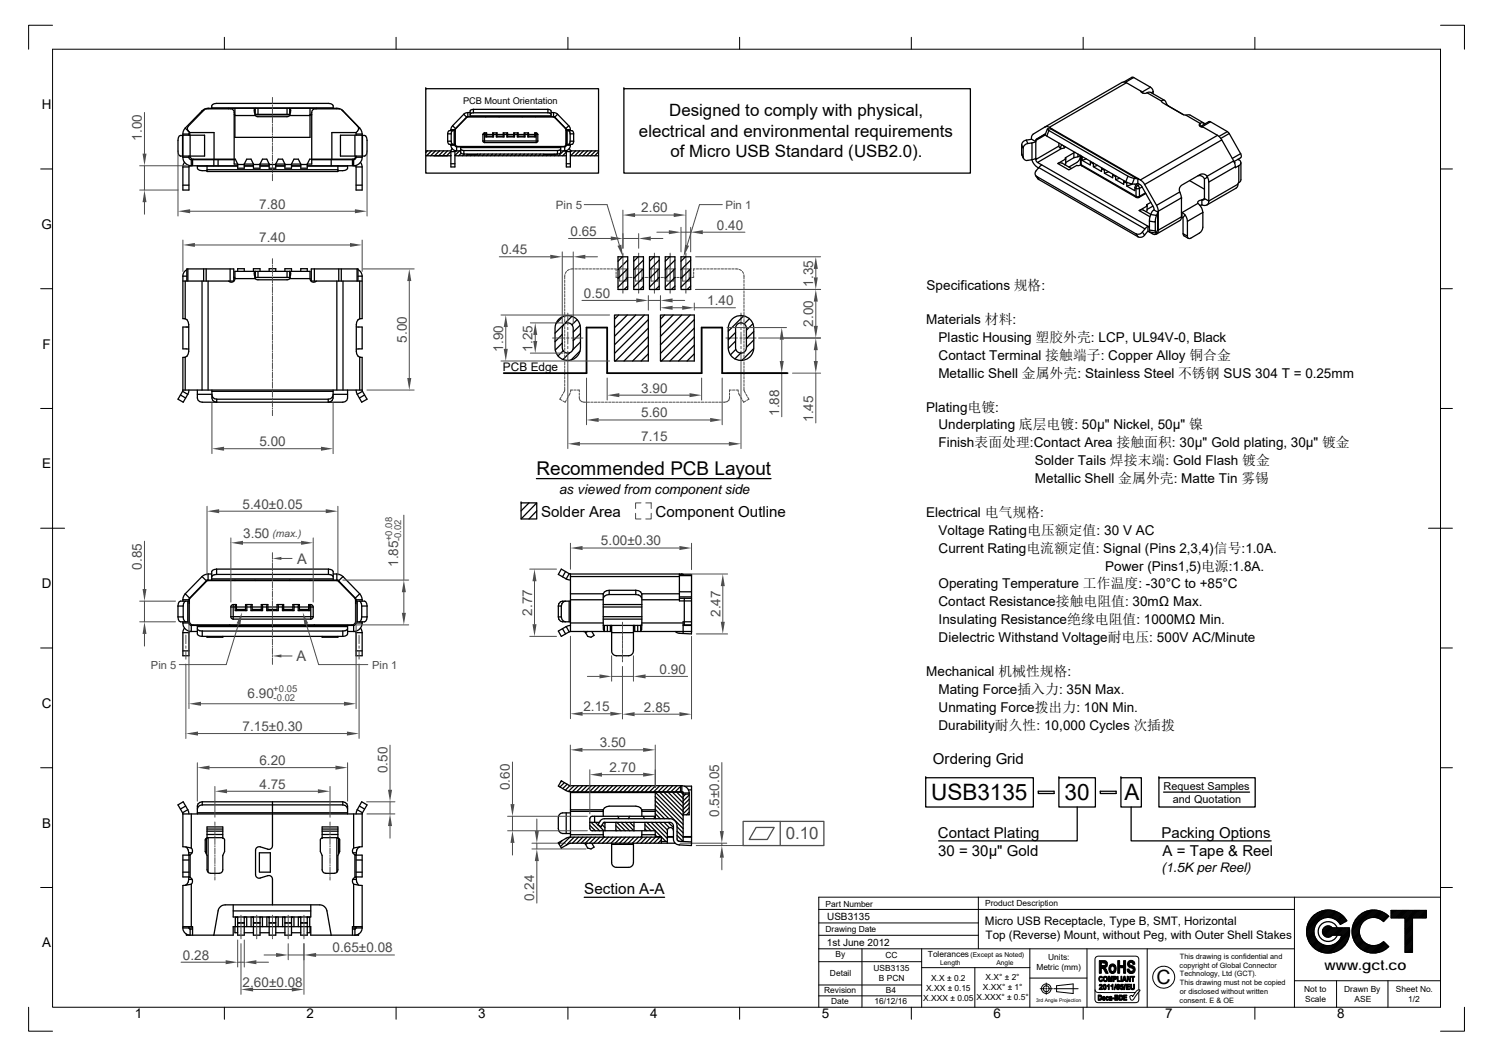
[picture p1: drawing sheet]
<svg xmlns="http://www.w3.org/2000/svg" width="297mm" height="210mm" viewBox="0 0 297 210" stroke-linecap="round" stroke-linejoin="round" font-family="sans-serif">
<defs><g id="words">
<g font-size="4.5">
<text x="185.3" y="159.1">USB3135</text>
<text x="211.8" y="159.1">30</text>
<text x="223.7" y="159.2">A</text>
</g>
<text font-size="3.9" x="230.1" y="195.8">C</text>
<text font-size="3.8" x="106.7" y="94.4">Recommended PCB Layout</text>
<g font-size="3.4">
<text x="133.1" y="23.1">Designed to comply with physical,</text>
<text x="127.1" y="27.2">electrical and environmental requirements</text>
<text x="133.4" y="31.2">of Micro USB Standard (USB2.0).</text>
</g>
<text font-size="3.4" fill="#4b4b4b" x="156.3" y="166.9">0.10</text>
<g font-size="3">
<text x="107.7" y="102.7">Solder Area</text>
<text x="130.4" y="102.8">Component Outline</text>
<text x="185.6" y="151.9">Ordering Grid</text>
<text x="186.6" y="166.6">Contact Plating</text>
<text x="231.1" y="166.5">Packing Options</text>
<text x="186.6" y="170.2">30 = 30µ&quot; Gold</text>
<text x="231.3" y="170.1">A = Tape &amp; Reel</text>
<text x="116.2" y="177.8">Section A-A</text>
</g>
<g font-size="2.9" fill="#4b4b4b">
<text x="59.1" y="112.1">A</text>
<text x="59" y="131.3">A</text>
</g>
<text font-size="2.8" x="263.5" y="192.9">www.gct.co</text>
<g font-size="2.7">
<text x="8.3" y="21.7">H</text>
<text x="8.2" y="45.5">G</text>
<text x="184.3" y="57.7">Specifications 规格:</text>
<text x="184.3" y="64.4">Materials 材料:</text>
<text x="8.5" y="69.3">F</text>
<text x="186.7" y="71.6">Contact Terminal 接触端子: Copper Alloy 铜合金</text>
<text x="186.7" y="68">Plastic Housing 塑胶外壳: LCP, UL94V-0, Black</text>
<text x="186.7" y="75.1">Metallic Shell 金属外壳: Stainless Steel 不锈钢 SUS 304 T = 0.25mm</text>
<text x="184.3" y="81.9">Plating电镀:</text>
<text x="186.7" y="88.9">Finish表面处理:Contact Area 接触面积: 30µ&quot; Gold plating, 30µ&quot; 镀金</text>
<text x="186.7" y="85.4">Underplating 底层电镀: 50µ&quot; Nickel, 50µ&quot; 镍</text>
<text x="8.4" y="93.1">E</text>
<text x="205.9" y="92.5">Solder Tails 焊接末端: Gold Flash 镀金</text>
<text x="111.2" y="98.1">as viewed from component side</text>
<text x="205.9" y="96.1">Metallic Shell 金属外壳: Matte Tin 雾锡</text>
<text x="184.2" y="102.8">Electrical 电气规格:</text>
<text x="186.7" y="106.4">Voltage Rating电压额定值: 30 V AC</text>
<text x="186.7" y="109.9">Current Rating电流额定值: Signal (Pins 2,3,4)信号:1.0A.</text>
<text x="219.9" y="113.5">Power (Pins1,5)电源:1.8A.</text>
<text x="8.3" y="117">D</text>
<text x="186.7" y="117">Operating Temperature 工作温度: -30°C to +85°C</text>
<text x="186.7" y="120.6">Contact Resistance接触电阻值: 30mΩ Max.</text>
<text x="186.7" y="124.1">Insulating Resistance绝缘电阻值: 1000MΩ Min.</text>
<text x="186.7" y="127.7">Dielectric Withstand Voltage耐电压: 500V AC/Minute</text>
<text x="184.3" y="134.4">Mechanical 机械性规格:</text>
<text x="186.7" y="138">Mating Force插入力: 35N Max.</text>
<text x="8.3" y="140.8">C</text>
<text x="186.7" y="141.5">Unmating Force拨出力: 10N Min.</text>
<text x="186.7" y="145.1">Durability耐久性: 10,000 Cycles 次插拨</text>
<text x="8.4" y="164.6">B</text>
<text x="8.4" y="188.4">A</text>
<text x="26.8" y="202.4">1</text>
<text x="61" y="202.4">2</text>
<text x="95.1" y="202.4">3</text>
<text x="129.3" y="202.4">4</text>
<text x="163.5" y="202.4">5</text>
<text x="197.7" y="202.4">6</text>
<text x="231.8" y="202.4">7</text>
<text x="266" y="202.4">8</text>
</g>
<g font-size="2.7" fill="#4b4b4b">
<text x="28.2" y="27.9" transform="rotate(-90 28.2 27.9)">1.00</text>
<text x="51.6" y="41.5">7.80</text>
<text x="113.5" y="46.9">0.65</text>
<text x="127.6" y="42.2">2.60</text>
<text x="142.6" y="45.6">0.40</text>
<text x="51.6" y="48.2">7.40</text>
<text x="99.7" y="50.5">0.45</text>
<text x="116.2" y="59.2">0.50</text>
<text x="161.8" y="57" transform="rotate(-90 161.8 57)">1.35</text>
<text x="140.7" y="60.7">1.40</text>
<text x="161.8" y="65" transform="rotate(-90 161.8 65)">2.00</text>
<text x="80.9" y="68.1" transform="rotate(-90 80.9 68.1)">5.00</text>
<text x="100.1" y="69.9" transform="rotate(-90 100.1 69.9)">1.90</text>
<text x="106" y="69.9" transform="rotate(-90 106 69.9)">1.25</text>
<text x="127.6" y="83">5.60</text>
<text x="127.6" y="78.1">3.90</text>
<text x="155" y="82.7" transform="rotate(-90 155 82.7)">1.88</text>
<text x="161.8" y="83.9" transform="rotate(-90 161.8 83.9)">1.45</text>
<text x="51.6" y="88.7">5.00</text>
<text x="127.6" y="87.7">7.15</text>
<text x="48.2" y="101.1">5.40±0.05</text>
<text x="48.4" y="107">3.50</text>
<text x="28.2" y="113.2" transform="rotate(-90 28.2 113.2)">0.85</text>
<text x="79.2" y="112.7" transform="rotate(-90 79.2 112.7)">1.85</text>
<text x="119.6" y="108.5">5.00±0.30</text>
<text x="105.9" y="122.5" transform="rotate(-90 105.9 122.5)">2.77</text>
<text x="143.3" y="122.7" transform="rotate(-90 143.3 122.7)">2.47</text>
<text x="131.2" y="134">0.90</text>
<text x="49.3" y="138.8">6.90</text>
<text x="116.1" y="141.4">2.15</text>
<text x="128.1" y="141.5">2.85</text>
<text x="48.2" y="145.4">7.15±0.30</text>
<text x="119.3" y="148.6">3.50</text>
<text x="51.6" y="152.1">6.20</text>
<text x="77.1" y="153.8" transform="rotate(-90 77.1 153.8)">0.50</text>
<text x="121.3" y="153.5">2.70</text>
<text x="51.6" y="156.8">4.75</text>
<text x="101.4" y="157.1" transform="rotate(-90 101.4 157.1)">0.60</text>
<text x="143.1" y="162.5" transform="rotate(-90 143.1 162.5)">0.5±0.05</text>
<text x="106.3" y="179.2" transform="rotate(-90 106.3 179.2)">0.24</text>
<text x="36.4" y="190.8">0.28</text>
<text x="66.1" y="189.4">0.65±0.08</text>
<text x="48.3" y="196.2">2.60±0.08</text>
</g>
<text font-size="2.6" x="231.1" y="173.5">(1.5K per Reel)</text>
<g font-size="2.3" fill="#4b4b4b">
<text x="110.6" y="41.5">Pin 5</text>
<text x="144.3" y="41.5">Pin 1</text>
</g>
<g font-size="2.3">
<text x="100" y="73.7">PCB Edge</text>
<text x="195.9" y="183.8">Micro USB Receptacle, Type B, SMT, Horizontal</text>
<text x="196.1" y="186.7">Top (Reverse) Mount, without Peg, with Outer Shell Stakes</text>
</g>
<g font-size="2.2" fill="#4b4b4b">
<text x="30" y="133">Pin 5</text>
<text x="74" y="133">Pin 1</text>
</g>
<g font-size="2.2">
<text x="231.5" y="157.1">Request Samples</text>
<text x="233.3" y="159.7">and Quotation</text>
</g>
<text font-size="2" fill="#4b4b4b" x="54.2" y="106.8">(max.)</text>
<g font-size="2">
<text x="164.5" y="182.9">USB3135</text>
<text x="164.5" y="188.1">1st June 2012</text>
</g>
<g font-size="1.9" fill="#4b4b4b">
<text x="78" y="107.6" transform="rotate(-90 78 107.6)">+0.08</text>
<text x="79.8" y="107.6" transform="rotate(-90 79.8 107.6)">-0.02</text>
<text x="54.4" y="137.6">+0.05</text>
<text x="54.4" y="139.4">-0.02</text>
</g>
<text font-size="1.8" x="92.1" y="20.7">PCB Mount Orientation</text>
<g font-size="1.7">
<text x="164.3" y="180.3">Part Number</text>
<text x="164.3" y="185.3">Drawing Date</text>
<text x="196" y="180.2">Product Description</text>
<text x="166.2" y="190.4">By</text>
<text x="176.2" y="190.5">CC</text>
<text x="184.6" y="190.4">Tolerances</text>
<text x="208.5" y="191">Units:</text>
<text x="164" y="197.5">Revision</text>
<text x="165.1" y="194.1">Detail</text>
<text x="173.8" y="193.2">USB3135</text>
<text x="174.9" y="195.1">B PCN</text>
<text x="176.3" y="197.5">B4</text>
<text x="184.2" y="197">X.XX ± 0.15</text>
<text x="185.3" y="195">X.X ± 0.2</text>
<text x="195.5" y="196.9">X.XX° ± 1°</text>
<text x="196.1" y="195">X.X° ± 2°</text>
<text x="206.2" y="192.9">Metric (mm)</text>
<text x="259.5" y="197.2">Not to</text>
<text x="267.4" y="197.2">Drawn By</text>
<text x="277.7" y="197.3">Sheet No.</text>
<text x="165.4" y="199.7">Date</text>
<text x="174" y="199.7">16/12/16</text>
<text x="183.7" y="199">X.XXX ± 0.05</text>
<text x="194.3" y="198.9">X.XXX° ± 0.5°</text>
<text x="259.7" y="199.2">Scale</text>
<text x="269.5" y="199.2">ASE</text>
<text x="280.1" y="199.2">1/2</text>
</g>
<g font-size="1.5">
<text x="234.7" y="190.6">This drawing is confidential and</text>
<text x="234.7" y="192.4">copyright of Global Connector</text>
<text x="234.7" y="197.6">or disclosed without written</text>
<text x="234.7" y="194.1">Technology, Ltd (GCT).</text>
<text x="234.7" y="195.9">This drawing must not be copied</text>
<text x="234.7" y="199.4">consent. E &amp; OE</text>
</g>
<g font-size="1.3">
<text x="187" y="191.9">Length</text>
<text x="193.1" y="190.4">(Except as Noted)</text>
<text x="198.2" y="191.9">Angle</text>
</g>
<text font-size="1" x="206.1" y="199.2">3rd Angle Projection</text>
</g></defs>
<path d="M184.2 154.7h21.4v5.8h-21.4zM184.2 154.7h.1M206.6 157.3h3.1v.5h-3.1zM210.7 154.7h7.2v5.8h-7.2zM210.7 154.7h.1M218.9 157.3h3.2v.5h-3.2zM223 154.7h4.1v5.8h-4.1zM223 154.7h.1M214.3 160.5v6.7h-27.5M225 160.5v6.7h27.9" fill="none" stroke="#000" stroke-width=".25"/>
<path d="M105.8 168.8h10.8M105.8 167.7h6.7M106.8 162.8v2.5M106.8 167.7v1.1M106.8 171.2v8.4" fill="none" stroke="#4b4b4b" stroke-width=".2"/>
<g fill="#4b4b4b">
<path d="M106.4 165.3h.8l-.4 2.4z"/>
<path d="M106.8 168.8l.4 2.4h-.8z"/>
</g>
<path d="M147.8 163.3h16.1v4.8h-16.1zM150.4 164.5h3.6l-1.3 2.4h-3.6zM155.2 163.3v4.8" fill="none" stroke="#4b4b4b" stroke-width=".25"/>
<path d="M143.6 151.6v13.7M135.3 167.7h9.3M138.5 168.1h6.1M143.6 167.7v.4M143.6 170.5v2.5" fill="none" stroke="#4b4b4b" stroke-width=".2"/>
<g fill="#4b4b4b">
<path d="M143.6 168.1l.4 2.4h-.8z"/>
<path d="M143.2 165.3h.8l-.4 2.4z"/>
</g>
<g fill="none" stroke="#000" stroke-width=".25">
<path d="M111.8 155.3l-.3 .2M112.3 155.6l-.9 .9M112.8 155.9l-.8 .9M113.4 156.2l-.9 .9M113.5 157.4h22.2M113.5 157.6h16.9M113.5 157.4v9M114.2 156.2l-1.1 1.2M115.1 156.2l-1.2 1.2M115.9 156.2l-1.2 1.2M116.8 156.2l-1.2 1.2M117.6 156.2l-1.2 1.2"/>
<path d="M118.5 156.2l-1.2 1.2M119.3 156.2l-1.2 1.2M120.2 156.2l-1.2 1.2M121.1 156.2l-1.3 1.2M121.9 156.2l-1.2 1.2M122.7 156.2l-1.2 1.2M123.6 156.2l-1.2 1.2M124.5 156.2l-1.2 1.2M125.3 156.2l-1.2 1.2M126.2 156.2l-1.3 1.2M127 156.2l-1.2 1.2M127.9 156.2l-1.2 1.2"/>
<path d="M128.7 156.2l-1.2 1.2M129.6 156.2l-1.2 1.2M130.4 156.2l-1.2 1.2M131.3 156.2l-1.2 1.2M132.1 156.2l-1.2 1.2M133 156.2l-1.2 1.2M133.8 156.2l-1.2 1.2M134.7 156.2l-1.2 1.2M135.4 157.2l-.2 .2M135.4 156.2v1.2M135.4 156.3l-1.1 1.1M135.7 156.2h-22.2l-1.8-.9-.6 1 1.5 .9 .9 .2"/>
<path d="M135.7 156.2v1.2M135.7 157.4l.1 .1M135.7 156.2a1.46 1.46 0 0 1 1.4 1.5M135.9 157.7h1.2M135.9 157.9h1.2M136.2 156.3h1.4v11.8l-2.5-.1M136.4 157.9l-.5 .5M136.9 157.1h.7M137.1 158.1l-1.2 1.2M137.1 158.9l-1.2 1.2M137.1 159.8l-1.2 1.2M137.1 157.7v4.3h-1.2"/>
<path d="M111.8 167.1l-.6 .7M112.6 161.6v4.1M113.4 166.5l-1.9 1.8M113.5 161h6.5M113.5 161.3h6.5M113.5 161.6h-1.6l-.4 .2-.3 .3-.1 .5 .1 2.7 .3 .3 .4 .1h1.6M113.5 166h6.5M114.2 166.5l-1.6 1.6M115.1 166.5l-1.2 1.2M116 166.5l-1.3 1.2M116.1 167.7l.4 .2M116.8 166.5l-1.2 1.2"/>
<path d="M116.9 167.7l-.4 .2M117.6 166.5l-1.2 1.2M117.8 167.7l.4 .8-.6 .3-.7-.2-.4-.7M118.3 162.3v1.2M118.5 166.5l-1.2 1.2M119.3 163.5h-1.9M119.4 166.5l-1.2 1.2M120 161l.2-.3 1-.4h5.3l1 .4 .2 .3M120 161v1.3M120 165.2v.8M120 166v.3l.2 .2M120.2 166.5l-1.2 1.2"/>
<path d="M121.1 166.5l-1.3 1.2M121.7 167.7v3.8l.1 .5 .6 .5h2.7l.4-.2 .5-.5v-4.1M121.7 167.9h4.3M121.9 166.5l-1.2 1.2M122.8 166.5l-1.2 1.2M123.6 166.5l-1.2 1.2M124.5 166.5l-1.2 1.2M125.3 166.5l-1.2 1.2M126.2 166.5l-1.2 1.2M127 166.5l-1.2 1.2M127.7 161h2.7M127.7 161v.2"/>
<path d="M127.7 161.3h2.7M127.7 166v.3l-.2 .2M127.7 161v1.3M127.7 165.2v.8M127.7 166h2.7M127.9 166.5l-1.2 1.2M128.7 166.5l-1.2 1.2M129.6 166.5l-1.2 1.2M130.4 162.8v-5.3h5.5v9.8M130.4 162.3h-12.6l-.3 .2-.2 .3v1.9l.2 .4 .3 .1h12.6v1.2h1.2v1.3M130.4 166.5l-1.2 1.2M131.3 166.5l-1.2 1.2"/>
<path d="M131.6 167l-.7 .7M131.6 166.5h-18.1l-.9 .2-1.5 .9 .6 1 1.8-.9h20.8M132.8 167.3v.4M132.8 166.5h1.2M132.8 166.4h1.2M134 165.1a.6 .6 0 0 0-.6-.5 .6 .6 0 0 0-.6 .5v2.2h-1.2M135.9 166.4h1.7M135.9 166.5h1.7M137.1 161.5l-.5 .5M137.1 160.6l-1.2 1.2M137.6 167.4l-2.5-.1-.3-.2-.1-.3v-2.6a1.44 1.44 0 0 0-1.5-1.4h-13.2a1.61 1.61 0 0 0-1 1.2l.6 .4 .4-.8 .2-.1h13.3l.3 .3 .2 .4v2.6a1.16 1.16 0 0 0 1.2 1.2"/>
</g>
<path d="M102 151.5v8.4M101 165.2h15.9M101 162.3h15.9M102 162.3v2.9M102 167.6v2.4" fill="none" stroke="#4b4b4b" stroke-width=".2"/>
<g fill="#4b4b4b">
<path d="M102 165.2l.4 2.4h-.8z"/>
<path d="M101.6 159.9h.8l-.4 2.4z"/>
</g>
<path d="M117.3 153.1v8.7M119.8 154h8.2M130.4 153.1v3.5" fill="none" stroke="#4b4b4b" stroke-width=".2"/>
<g fill="#4b4b4b">
<path d="M117.3 154l2.5-.4v.8z"/>
<path d="M128 153.6l2.4 .4-2.4 .4z"/>
</g>
<path d="M113.5 148.2v8.3M115.9 149.1h12.1M130.4 148.2v8.4" fill="none" stroke="#4b4b4b" stroke-width=".2"/>
<g fill="#4b4b4b">
<path d="M128 148.7l2.4 .4-2.4 .4z"/>
<path d="M113.5 149.1l2.4-.4v.8z"/>
</g>
<g fill="none" stroke="#000" stroke-width=".25">
<path d="M130.4 159.2l5.5 5.6M130.4 158.4l5.5 5.5M130.4 157.5l5.5 5.6M131.2 157.5l4.7 4.7M132.1 157.5l3.8 3.9M132.9 157.5l3 3M133.8 157.5l2.1 2.2M134.6 157.5l1.3 1.3M135.5 157.5l.4 .5M117.3 164.1l1.1 1.1M117.6 163.5l1.7 1.7M118.4 163.5l1.7 1.7"/>
<path d="M119.8 164l.6 .6M120.2 163.5l.2 .2M120.4 163.5v1.7M122.5 163.5v1.7M122.5 164.2l1 1M122.5 165l.2 .2M122.7 163.5l1.7 1.7M122.9 162.3l.3 .5M123.6 163.5l1.7 1.7M124.4 163.5l1.7 1.7M125.3 163.5l.8 .9M125.3 162.3l-.3 .5"/>
<path d="M126.1 163.5v1.7M128 162.3l.2 .5M128.3 164l1.2 1.2M128.3 164.9l.4 .3M128.3 163.5v1.7M128.7 163.5l2.8 2.9M129.5 163.5l3.3 3.3M130.4 162.6l.1 .2M130.4 160.1l2.7 2.7M130.4 166l.3 .4M130.4 160.9l1.8 1.9M130.4 161.8l1 1"/>
<path d="M130.4 162.3l-.3 .5M130.4 163.5l2.4 2.4M131.2 163.5l1.6 1.5M131.6 166.4l.9 .9M131.6 167.2v.1M132.1 163.5l1.1 1.1M132.9 163.5l1.1 1M134.7 166.1l1.2 1.2M134.7 165.3l1.2 1.2M134.7 164.4l1.2 1.2M134.7 167l.3 .2"/>
</g>
<path d="M138.4 57.6h24.9M138.4 51.1h24.9M162.3 53.5v1.7" fill="none" stroke="#4b4b4b" stroke-width=".2"/>
<g fill="#4b4b4b">
<path d="M161.9 55.2h.8l-.4 2.4z"/>
<path d="M162.3 51.1l.4 2.4h-.8z"/>
</g>
<g fill="none" stroke="#4b4b4b" stroke-width=".2">
<path d="M54.2 51.4v1.1M54.2 52.7v.3M54.2 53.2v1.2M54.2 54.6v.2M54.2 55.1v1.2M54.2 56.5v.3M54.2 57v1.2M54.2 58.4v.2M54.2 58.9v1.2M112.4 55.7v.5M112.4 56.4v.5M112.4 57.1v.5"/>
<path d="M112.4 57.9v.4M112.4 58.6v.4M112.4 59.3v.4M112.4 60v.5M112.4 54.6v.9M112.7 54l-.2 .4M113.3 53.6l-.4 .2M114.2 53.5h-.7M114.4 53.5h.5M115.1 53.5h.5M115.8 53.5h.5M116.5 53.5h.5"/>
<path d="M117.2 53.5h.5M118 53.5h.4M118.7 53.5h.4M119.4 53.5h.4M120.1 53.5h.4M120.8 53.5h.5M121.5 53.5h.5M122.2 53.5h.4v.3M122.6 54.1v.5M122.6 54.8v.4h.7M123.3 53.5h1.3v2.4h-1.3zM124.6 55.2h.4"/>
<path d="M125.3 55.2h.4M126 55.2h.4M126.4 53.5h1.3v2.4h-1.3zM127.7 55.2h.4M128.4 55.2h.5M129.1 55.2h.4M129.5 53.5h1.4v2.4h-1.4zM130.9 55.2h.4M131.5 55.2h.5M132.2 55.2h.5M132.7 53.5h1.3v2.4h-1.3zM134 55.2h.4"/>
<path d="M134.7 55.2h.4M135.4 55.2h.4M135.8 53.5h1.3v2.4h-1.3zM137.1 55.2h.3M138 54.1v.5M138 54.8v.4h-.3M138.3 53.5h-.3v.3M138.5 53.5h.5M139.2 53.5h.5M139.9 53.5h.5M140.6 53.5h.5M141.4 53.5h.4"/>
<path d="M142 53.5h.5M142.8 53.5h.4M143.5 53.5h.5M144.2 53.5h.5M144.9 53.5h.5M145.6 53.5h.5M146.3 53.5h.6M147.1 53.6l.4 .2M147.7 54l.2 .4M148 54.6v.9M148 55.7v.5M148 56.4v.5"/>
<path d="M148 57.1v.5M148 57.9v.4M148 58.6v.4M148 59.3v.4M148 60v.5M54.2 60.3v.2M54.2 60.8v1.2M54.2 62.2v.2M54.2 62.7v1.1M54.2 64.1v.2M54.2 64.6v1.1M54.2 66v.2"/>
<path d="M54.2 66.4v1.2M54.2 67.9v.2M54.2 68.3v1.2M54.2 69.8v.2M54.2 70.2v1.2M54.2 71.7v.2M54.2 72.1v1.2M54.2 73.5v.3M54.2 74v1.2M54.2 75.4v.3M54.2 75.9v1.2M54.2 77.3v.3"/>
<path d="M54.2 77.8v1.2M54.2 79.2v.3M54.2 79.7v1.2M109.9 67.2h2.3M111.6 79l-.2 .4 .4 .2M112 78.4l-.3 .4M112.4 77v.6l-.3 .6M112.4 60.7v.5M112.4 61.4v.5M112.4 62.1v.5M112.4 62.8v.5M112.4 63.5v.5"/>
<path d="M112.4 64.2v.5M112.4 64.9v.5M112.4 65.6v.5M112.4 66.4v.4M112.4 67.1v.4M112.4 67.8v.4M112.4 68.5v.5M112.4 69.2v.5M112.4 69.9v.5M112.4 70.6v.5M112.4 71.3v.5M112.4 72v.5"/>
<path d="M112.4 72.8v.4M112.4 73.5v.4M112.4 74.2v.4M112.4 74.9v.5M112.4 75.6v.5M112.4 76.3v.5M112.6 79.6l-.2 .4-.4-.3M112.7 67.2h.5M113 62.3v2.3M113 65.1v.5M113 66v2.4M113 68.9v.4"/>
<path d="M113 69.8v2.3M113 79l-.2 .4M113.5 78.1l-.4 .7M113.7 67.2h2.3M113.9 77.6h-.3l-.1 .3M114.2 77.6h.4M114.9 77.6h.4v.3M115.3 78.8a1 1 0 0 0 1.3 1.2M115.3 78.1v.5M116.8 80h.5M117.5 80h.5M118.2 80h.5"/>
<path d="M119 80h.4M119.7 80h.4M120.4 80h.4M121.1 80h.5M121.8 80h.5M122.5 80h.5M123.2 80h.5M123.9 80h.5M124.6 80h.5M125.3 80h.5M126 80h.5M126.8 80h.4"/>
<path d="M127.5 80h.5M128.2 80h.5M128.9 80h.5M129.6 80h.5M130.3 80h.5M131 80h.5M131.7 80h.5M132.4 80h.5M133.2 80h.4M133.9 80h.4M134.6 80h.4M135.3 80h.5"/>
<path d="M136 80h.5M136.7 80h.5M137.4 80h.5M138.1 80h.5M138.8 80h.5M139.5 80h.5M140.3 80h.4M140.9 80h.5M141.7 80h.4M142.4 80h.5M143.1 80h.5M144.4 67.2h2.3"/>
<path d="M145.1 78.1v.5M145.1 78.8a1 1 0 0 1-1.3 1.2M145.5 77.6h-.4v.3M145.7 77.6h.5M146.5 77.6h.3l.1 .3M146.9 78.1l.4 .7M147.2 67.2h.5M147.4 79l.2 .4M147.4 62.3v2.3M147.4 65.1v.5M147.4 66v2.4M147.4 68.9v.4"/>
<path d="M147.4 69.8v2.3M147.7 79.6l.3 .4 .4-.3M148 60.7v.5M148 61.4v.5M148 62.1v.5M148 62.8v.5M148 63.5v.5M148 64.2v.5M148 64.9v.5M148 65.6v.5M148 66.4v.4M148 67.1v.4"/>
<path d="M148 67.8v.4M148 68.5v.5M148 69.2v.5M148 69.9v.5M148 70.6v.5M148 71.3v.5M148 72v.5M148 72.8v.4M148 73.5v.4M148 74.2v.4M148 74.9v.5M148 75.6v.5"/>
<path d="M148 76.3v.5M148 77v.6l.3 .6M148.1 67.2h2.3M148.4 78.4l.3 .4M148.8 79l.2 .4-.4 .2M42.2 80.1v10.1M44.6 89.2h19.3M54.2 81.1v.3M54.2 81.6v1M66.3 80.1v10.1"/>
</g>
<g fill="none" stroke="#000" stroke-width=".25">
<path d="M35.6 27.1l.3-.2h4.8v4.1h-4.8l-.3-.1a6.1 6.1 0 0 1-.1-3.5zM36.3 26.9v4.1M36.4 36.8h1.2M36.4 33.2h1.2M36.4 26.7v4.6M36.4 31.3h1.2M36.4 26.7h1.2M36.4 31.3a1.67 1.67 0 0 0 1.7 1.7v-1.2M36.7 32.3l-.3 .9M36.9 25.5l.8 .8-.1 .4M36.9 25.5l-.5 .7v.5M37.6 33.2v4.6h-1.2v-4.6"/>
<path d="M37.6 26.7v.2M37.6 31v.3M37.6 31.3l.1 .3 .4 .2M37.8 26.4l-.4-.5a.69 .69 0 0 1 .1-.8l3.4-3.4 5-.1 .4 .2 .3 .6v10.2h.7M37.8 26.4v.5M37.8 26.4h4.8v5.3M37.8 26.9v4.1l.3 .5 .4 .2h8.3l.5 .9M38.1 31.8h8.5M38.3 31.8v1.2M39.3 33v.5l.5 .4h1.4M39.3 33h8M40.2 22l-3.3 3.5"/>
<path d="M40.2 22l.1 .2M41.2 33v1.1h26v-1.1M41.2 33.7h26M41.4 21.5v.1M41.4 21.5l-.7 .2-.5 .3M41.4 21.5h25.6M42.1 21.5l.1-.7 .9-.2h22.2l.9 .2 .1 .7M42.1 21.5h24.2M42.5 31.8v1.2M43.4 31.8v1.2M45.5 21.5v.1M46.6 22.7h.1"/>
<path d="M46.7 21.5v5.8h15v-5.8M46.7 23h4.1M47.3 33h-9.5l-.2 .2M47.3 32.7h1.3M48.6 32.6v.9h-1.3v-.9M48.6 32.6h1.8M48.6 33h1.8M50.4 32.6l-.4-.9h-.9l-.5 .9M50.4 32.6v.9h1.3v-.9M50.4 32.7h1.3M50.8 22.8h6.9M50.8 23l-.2-1.1 .2-.4v1.2h6.8v-1.2l.2 .4-.2 1.1"/>
<path d="M50.8 23l.5 .2h5.8l.5-.2M51.3 21.5v1.2M51.7 32.6h1.9M51.7 33h1.9M53.6 32.7h1.3M53.6 32.6l-.5-.9h-.9l-.5 .9M53.6 32.6v.9h1.3v-.9M54.9 32.6h1.8M54.9 33h1.8M54.9 32.6l.5-.9h.8l.5 .9v.9h1.3v-.9M56.7 32.7h1.3M57.1 21.5v1.2"/>
<path d="M57.6 23h4.1M58 32.6h1.8M58 33h1.8M59.8 32.7h1.3M61.1 33h9.5l.2 .2M61.1 33h8.1M61.1 32.6v.9h-1.3v-.9l-.4-.9h-.9l-.5 .9M61.7 22.8h.3M61.7 22.7h.3M62 31.8h8.4M62.9 21.5v.1M65.9 31.8v1.2"/>
<path d="M67 21.5l.6 .1M67 21.5v.1M67.7 26.9h4.8l.3 .2a5.6 5.6 0 0 1 .2 3.5l-.5 .4h-4.8zM68 21.9l-.5-.3h-4.8l-.6 .3-.1 .5v10.2h-.9M68 21.9l3.6 3.6M68 21.9l3.1 3.2a.81 .81 0 0 1-.3 1.3M69.2 33v.5l-.5 .4h-1.5M70.1 31.8v1.2M70.6 26.9v4.1M70.8 36.8h1.3M70.8 33.2h1.3M70.8 31.3h1.3"/>
<path d="M70.8 26.7h1.3M70.8 31.3l-.1 .3-.3 .2M70.8 26.4h-4.8v5.3M70.8 31.3v-.2a.74 .74 0 0 1-.7 .6h-8.5l-.5 .9M70.8 33.2v4.6h1.3v-4.6M70.8 26.4v.5M71.6 25.5l.4 .7 .1 .5M71.6 25.5l-.3 .2M71.7 32.3l.4 .9M72.1 31.3a1.71 1.71 0 0 1-1.7 1.7v-1.2M72.1 26.7v4.6M72.1 26.9v4.1"/>
<path d="M36.4 54.9v8.5h.5M36.4 54.9h.8M36.4 55.9h10.1v-2.4h-9.3v2.4M36.9 55.9v7.5M37.2 53.6l-.7 .7-.1 .6M37.4 53.5v2.4M40.2 55.9v21.7M40.5 53.5v2.4M41 53.5v2.4M41.4 55.9v21.7M45.8 53.5v2.4M46.5 55.2h.2"/>
<path d="M46.7 55.4a.72 .72 0 0 1-.4 .7 .72 .72 0 0 1-.8-.2M46.7 55.4h4.1M47.3 54v-.6h1.3v.6M50.7 55.2h7M50.8 55.4l.5 .2h5.8l.5-.2M50.8 55.2v-1.2l-.2 .4 .2 1M51.3 54v1.2M51.7 54v-.6h-1.3v.6M54.9 54v-.6h-1.3v.6M56.7 54v-.6h1.3v.6M57.1 54v1.2M57.6 55.2v-1.2l.2 .4-.2 1"/>
<path d="M57.6 55.4h4.1M61.1 54v-.6h-1.3v.6M61.7 55.4a.73 .73 0 0 0 .4 .7 .73 .73 0 0 0 .8-.2M61.7 55.4v-1.4h-15v1.4M62.5 53.5v2.4M67 55.9v21.7M67.4 53.5v2.4M67.9 53.5v2.4M68.2 55.9v21.7M71 53.5v2.4M71.2 53.6l.5 .4 .4 .9M71.2 54.9h.9"/>
<path d="M71.6 55.9v7.5M72.1 54.9v8.5h-.5M72.1 55.9h-10.2v-2.4h9.3v2.4M124.9 51.7l-1.9 1.9M35.9 78.5l1 .6M36.3 77.8l-.9 1.6 1 .6 1-1.6M36.3 77.8l1.1 .6M36.4 77.6h35.7M36.4 77.6l-.1 .2M36.9 71l-.5 .1v6.5M36.9 63.4l.3 .2 .3 1v5.3l-.3 .9-.3 .2M36.9 71v6.6"/>
<path d="M37.5 65h-1.1v4.4h1.1M37.6 77.6l-.2 .8M39.3 77.6v1.5l.1 .5 .4 .3 .4 .1h28l.5-.1 .3-.3 .2-.5v-1.5M39.3 78.4h2.9M42.2 77.8h24.1M42.2 77.6v1.5l.1 .5 .4 .3 .4 .1v-.6M42.2 78.5l.1 .5 .4 .3 .4 .1M43.1 79.4h22.2M66.3 78.4h2.9M66.3 78.5l-.2 .5-.3 .3-.5 .1M66.3 77.6v1.5l-.2 .5-.3 .3-.5 .1v-.6M70.8 77.6l.3 .8"/>
<path d="M70.9 65h1.2v4.4h-1.2M71.6 71l.5 .1v6.5M71.6 71v6.6M71.6 63.4l-.4 .2-.2 .4-.1 .6v5.3l.1 .5 .6 .6M72.1 77.6v.2M72.1 77.8l-1 .6M72.1 77.8l.9 1.6-1 .6-.9-1.6M72.5 78.5l-1 .6M111 63.7a2.52 2.52 0 0 1 2.8-.8 2.52 2.52 0 0 1 1.7 2.4v3.8a2.53 2.53 0 0 1-2.5 2.6 2.53 2.53 0 0 1-2.6-2.6l.1-4.3zM111.9 68.2l-1.4 1.4M111.9 66.5l-1.5 1.5M112 62.9l-1.4 1.5"/>
<path d="M112.1 69.7l-1.1 1.1M112.4 64.4a1.09 1.09 0 0 1 1.6 .9v3.8a1.09 1.09 0 0 1-1 1.1 1.09 1.09 0 0 1-1.1-1.1v-3.8l.1-.6zM113.3 70.2l-1.3 1.3M113.8 62.9l-3.4 3.3M114.8 63.6l-1 1M115.4 69.8l-1.8 1.8M115.4 64.7l-1.4 1.3M115.5 66.3l-1.5 1.4M115.5 68l-1.5 1.5M145.4 63.7a2.54 2.54 0 0 1 2.9-.8 2.54 2.54 0 0 1 1.7 2.4v3.8a2.54 2.54 0 0 1-2.6 2.6 2.54 2.54 0 0 1-2.5-2.6v-4.3zM146.3 67.8l-1.4 1.5M146.3 66.1l-1.4 1.5"/>
<path d="M146.4 69.5l-1.1 1.1M146.8 64.4a1.08 1.08 0 0 1 1.7 .9v3.8a1.08 1.08 0 0 1-1.1 1.1 1.08 1.08 0 0 1-1.1-1.1l.1-4.1zM147.4 70.2l-1.2 1.2M148 62.8l-3.1 3.1M149.1 63.4l-1 1M149.8 64.4l-1.3 1.2M149.9 69.3l-2.3 2.4M150 65.9l-1.5 1.5M150 67.6l-1.5 1.5M36.4 119.3v.2M36.4 119.3h1.2M36.9 118.1l.8 .8"/>
<path d="M36.9 118.1l-.5 .7v.5M36.9 119.5l-.4 .5-.1 .5M37.4 119.5v4.1M37.6 119.3v4.6M37.6 119.5h-1.7l-.3 .2-.2 .8M37.7 118.9l3.5-3.6h26l3.5 3.6M37.7 118.9l-.1 .4M40.2 114.6l-3.3 3.5M41.1 115.6l.3-.1h25.7l3.6 3.6v4.7l-.3 .3-.4 .2-31.8-.1-.4-.2-.1-.5v-4.4zM41.4 114.1h.7M41.4 114.1v1.2l-.3 .2-.9-.9M41.4 114.1l-.7 .2-.5 .3"/>
<path d="M42.1 115.1h24.2M43.1 114.2h22.2M43.1 113.2v1M43.1 113.2l-.9 .2-.1 .3v1.6M43.1 113.2h22.2M43.1 114.2l-.9 .3-.1 .2M46.7 115.3v.2M50.7 115.3l.1 .2M57.7 115.3v.2M61.7 115.3v.2M65.3 113.2l.9 .2 .1 .3v1.6M65.3 113.2v1"/>
<path d="M65.3 114.2l.9 .3 .1 .2M66.3 114.1h.7M67 114.1v1.2l.4 .2 .8-.9M67 114.1l.7 .2 .5 .3M68.2 114.6l3.4 3.5M70.7 118.9l.1 .4M70.8 119.3h1.3M70.8 119.5h1.7l.5 .5v.5M70.8 119.3v4.6M71.1 119.5v4.1M71.5 119.5l.2 .2 .3 .8M71.6 118.1l-.9 .8"/>
<path d="M71.6 118.1l.4 .7 .1 .5M72.1 119.3v.2M112.5 119.5l-.4 .2-.3 .3-.1 .5M112.5 113.7l-.6 1M112.6 115.1l.9 .2M113.2 114.1l-1.5-.9-.6 1 1.5 .9M113.2 114.1h.3M113.2 119.5v4.1M113.2 114.1l-.6 1M113.5 114.6h21.7M113.5 114.1h22.2M113.5 118.1h6.5"/>
<path d="M113.5 119.3h6.5M113.5 119.5h-1.6l-.4 .2-.3 .3-.1 .5M113.5 114.1v11.5M120 118.1v7l.2 .5v-1.2M121.2 117.4v.8M126.5 117.4l.5 .1 .5 .2 .2 .4M126.5 117.4h-5.3l-.5 .1-.5 .2-.2 .4M126.5 118.2l.5 .1 .5 .3 .2 .3M126.5 118.2h-5.3l-.5 .1-.5 .3-.2 .3M126.5 117.4v.8M127.7 118.1v5.8v1.2l-.2 .5v-1.2l.2-.2M127.7 118.1h7.5"/>
<path d="M127.7 119.3h7.5M135.2 114.2h2.4v10.1h-1.7M135.2 114.5h2.4M135.2 114.1v5.4h2.4M135.2 117.7h2.4M135.2 118.7h2.4M135.2 119h2.4M135.7 114.1v.1M135.7 114.1l.5 .1M136.1 119v5.3M35.4 120.5h1M35.4 122.7l.2 .8 .3 .1h1.7"/>
<path d="M35.4 120.5v2.2M35.4 122.7h1M36.4 125.8v4.6h1.2v-4.6M36.4 123.6v.3M36.4 129.4h1.2M36.4 123.9a1.66 1.66 0 0 0 1.7 1.7v-1.2M36.4 125.8h1.2M36.4 123.9h1.2M36.4 122.7l.1 .5 .4 .4M36.4 120.5v2.2M36.7 124.9l-.3 .9M37.6 123.9l.1 .3 .4 .2"/>
<path d="M38.1 124.4h32.3M39.3 124.4v1.7l.5 .4h.4M39.3 125l.1 .3 .8 .2M39.3 124.6h29.9M39.3 125.6h-1.5l-.2 .2M40.2 125.5v1M40.2 125.5h28M40.2 126.5h28M41.2 126.5v.2h3.1v-.2M45.7 124.3v.1M45.9 120.7v1.9M45.9 120.7h.9"/>
<path d="M45.9 122.6h16.4M45.9 122.6l.2 .4 .3 .1M46.4 120.2v2.9M46.4 120.2h.6v1.2M46.4 120.2l-.3 .2-.2 .3M46.4 123.1h15.4M46.9 120.2l-.1 .5M47 120.7h1.9M47 121.2h1.9M48.9 121.4v-1.2h1.3v1.2M49 120.2l.1 1.2h-2.3v-.7M49.1 120.7h.8"/>
<path d="M50 120.2l-.1 .5M50.2 120.7h1.8M50.2 121.2h1.8M52 121.4v-1.2h1.3v1.2M52.1 120.2l.1 .5M52.2 120.7h.9M52.2 120.7v.7h-2.3v-.7M53.1 120.7v.7h2.3v-.7M53.2 120.2l-.1 .5M53.3 120.7h1.8M53.3 121.2h1.8M55.1 121.4v-1.2h1.3v1.2"/>
<path d="M55.2 120.2l.2 .5M55.4 120.7h.8M56.2 120.7v.7h2.3v-.7M56.3 120.2l-.1 .5M56.4 120.7h1.9M56.4 121.2h1.9M58.3 121.4v-1.2h1.3v1.2M58.4 120.2l.1 .5M58.5 120.7h.8M59.3 120.7v.7h2.3v-.7M59.4 120.2l-.1 .5M59.6 120.7h1.8"/>
<path d="M59.6 121.2h1.8M61.5 120.2l.1 .5M61.6 120.7h.7M61.8 120.2v2.9M61.8 120.2h-.4v1.2M61.8 120.2l.4 .2 .1 .3M62.3 120.7v1.9M62.3 122.6l-.1 .4-.4 .1M62.5 124.3l.1 .1M64.1 126.5v.2h3.1v-.2M68.2 125.5v1M69.2 124.4v1.7l-.5 .4h-.5"/>
<path d="M69.2 125l-.2 .3-.8 .2M69.2 125.6h1.4l.2 .2M70.8 129.4h1.3M70.8 125.8h1.3M70.8 125.8v4.6h1.3v-4.6M70.8 123.9h1.3M70.8 123.9l-.1 .3-.3 .2M71.7 124.9l.4 .9M72 120.5h1M72 122.7h1M72 120.5v2.2M72 122.7l-.3 .8-.2 .1"/>
<path d="M72.1 123.6v.3M72.1 123.9a1.7 1.7 0 0 1-1.7 1.7v-1.2M73 122.7v.5l-.5 .4h-1.7M73 120.5v2.2M111.1 120.5h.6M111.1 122.7h.6M111.1 122.7l.1 .5 .3 .3 .4 .1h1.6M111.1 120.5v2.2M111.7 122.7l.1 .5 .3 .3 .4 .1M111.7 120.5v2.2M111.9 125l.6 1.1M112.6 124.6l-1.5 .9 .6 1 1.5-.9"/>
<path d="M112.6 124.6l.6 1M113.5 125.6h-.3M113.5 123.9h6.5M113.5 124.4l-.9 .2M113.5 125.6h8.2M116.1 125.6l.4 .2M116.9 125.6l-.4 .2M117.8 125.6l.4 .8-.6 .3-.7-.2-.4-.7M120 120.2h7.7M120 120.7h7.7M120 122.6h7.7M120 123.1h7.7"/>
<path d="M120 124.4h7.7M120.8 124.4v1.2M121.4 124.4v1.2M121.7 125.8h4.3M126 125.6h11.6M126.1 125.6v-1.2l-.1 5-.1 .5-.4 .4-.4 .1h-2.5l-.4-.1-.5-.6-.1-5.3v1.2M126.3 124.4v1.2M126.9 124.4v1.2M127.7 123.9h8.2M135.9 124.4h1.7v1.2M137.6 125.6v.5l-2.5-.2-.8-.3M137.6 123.6h-1.7v2.4"/>
<path d="M40.2 159.4v.6M40.2 159.4l-.4 .2-.4 .3-.1 .4v1.5M40.2 159.4h28M54.2 159.4v9a.71 .71 0 0 1-.9 .5l-1.7-.5a.7 .7 0 0 0-.8 .7l.1 5a.71 .71 0 0 0 .9 .5l1.7-.5 .6 .3 .1 5.5M68.2 159.4l.5 .2 .3 .3 .2 .4v1.5M68.2 159.4v.6M36.3 161.6l.1 .2M36.4 171h1.2M36.4 173.4h1.2M36.4 161.8h35.7M36.4 161.8v6.6l1.7 .2M36.9 160.3l-1 .6"/>
<path d="M37.1 168.4l.3 .6 .1 .6M37.4 161l-1-1.6-1 .6 .9 1.6M37.4 161l-1.1 .6M37.4 161l.2 .8M37.5 174.9h.7M37.5 169.6h.7M37.5 174.9l-.3 .9-.3 .2M37.5 169.6v.4M37.5 174.4v.5M37.6 170v4.4M37.8 170h-1.4v4.4l1.4 .1M37.8 170v4.5"/>
<path d="M37.8 174.5a.84 .84 0 0 1 .3 1.3M38.1 175.8l-1.7 .3v8.4M38.1 161.8v6.8M38.1 175.8v8.5M38.1 168.6a.84 .84 0 0 1-.3 1.4M39.3 161.6h29.9M40.2 160h28M40.2 160l-.4 .2-.4 .3-.1 .4M41.1 166.7v3.1M41.2 166.7h.1M41.2 164.4h3.1v2.3h.2l.2 .3v2.3l-.4 .8v3.1l-.5 .4-1.9 .1-.4-.2-.3-.3v-3.1l-.4-.8v-2.3l.4-.3zM41.2 164.9h3.1"/>
<path d="M41.2 165.3h3.1M41.2 165.9h3.1M41.2 166.6h3.1M41.4 166.6v6.8M51.6 169.6h2.2v3.8h-2.2zM61.8 179.9v2.4h-15.4v-2.4M64.1 164.4h3.1v2.3h.2l.2 .3v2.3l-.4 .8v2.8a.7 .7 0 0 1-.7 .8l-1.9-.1-.5-.4v-3.1l-.4-.8v-2.3l.2-.3h.2zM64.1 164.9h3.1M64.1 165.3h3.1M64.1 165.9h3.1M64.1 166.6h3.1M67 166.6v6.8"/>
<path d="M67.2 166.7h.1M67.4 166.7v3.1M68.2 160l.5 .2 .3 .3 .2 .4M70.2 174.9h.7M70.2 169.6h.7M70.4 175.8l1.7 .3v8.4M70.4 161.8v6.8M70.4 175.8v8.5M70.4 168.6a.83 .83 0 0 0 .2 1.4M70.6 170h1.5v4.4l-1.5 .1M70.6 170v4.5M70.6 174.5a.83 .83 0 0 0-.2 1.3"/>
<path d="M70.8 171h1.3M70.8 173.4h1.3M70.8 170v4.4M70.9 174.9l.1 .5 .3 .6M70.9 174.4v.5M71.1 161l.9-1.6 1 .6-.9 1.6M71.1 161l1 .6M71.1 161l-.3 .8M71.5 160.3l1 .6M71.5 168.4a1.42 1.42 0 0 0-.6 1.6M72.1 161.8v6.6l-1.7 .2M72.1 161.6v.2"/>
<path d="M36.4 184.3h1.9v1.7M36.4 184.5h1.9M36.4 184.5a1.44 1.44 0 0 0 1.4 1.5v-1.3M37.1 185.7v.3h9.3v-1.7h15.4v1.7h4M37.6 184.3v.3l.2 .1M37.8 184.7h.5M46.4 181.1h15.4M46.7 184.3v1.2h.6M46.8 182.3v2M47 182.3l.3 .2M47.3 183.5h1.3M47.3 182.3v3.7h1.3v-3.7"/>
<path d="M48.6 185.5h1.8M48.9 182.3l-.3 .2M49.1 182.3v2M50 182.3v2M50.1 182.3l.3 .2M50.4 183.5h1.3M50.4 182.3v3.7h1.3v-3.7M51.7 185.5h1.9M52 182.3l-.3 .2M52.2 182.3v2M53.1 182.3v2M53.3 182.3l.3 .2"/>
<path d="M53.6 183.5h1.3M54.9 185.5h1.8M54.9 182.3v3.7h-1.3v-3.7M55.1 182.3l-.2 .2M55.4 182.3v2M56.2 182.3v2M56.4 182.3l.3 .2M56.7 183.5h1.3M56.7 182.3v3.7h1.3v-3.7M58 185.5h1.8M58.3 182.3l-.3 .2M58.5 182.3v2"/>
<path d="M59.4 182.3v2M59.5 182.3l.3 .2M59.8 183.5h1.3M61.1 182.3v3.7h-1.3v-3.7M61.4 182.3l-.3 .2M61.6 182.3v2M61.7 184.3v1.2h-.6M70.1 184.5h.6M70.1 184.7h.5M70.7 184.3v.4M70.8 184.5h1.3M70.8 184.3v.2"/>
<path d="M70.8 184.5l-.2 .2M71.3 185.7v.3h-5.4l-1-5.2a1.47 1.47 0 0 0-1.3-.9h-18.8a1.43 1.43 0 0 0-1.4 1.2l-.9 4.9M72.1 184.3h-2v1.7M72.1 184.5a1.46 1.46 0 0 1-1.5 1.5v-1.3"/>
</g>
<g fill="#4b4b4b">
<path d="M42.2 89.2l2.4-.4v.8z"/>
<path d="M63.9 88.8l2.4 .4-2.4 .4z"/>
</g>
<path d="M35.4 29.9v13.1M73 29.9v13.1M37.8 42h32.8" fill="none" stroke="#4b4b4b" stroke-width=".2"/>
<g fill="#4b4b4b">
<path d="M35.4 42l2.4-.4v.8z"/>
<path d="M70.6 41.6l2.4 .4-2.4 .4z"/>
</g>
<path d="M36.4 47.7v6.3M38.8 48.7h30.8M72.1 47.7v6.3" fill="none" stroke="#4b4b4b" stroke-width=".2"/>
<g fill="#4b4b4b">
<path d="M36.4 48.7l2.4-.4v.8z"/>
<path d="M69.6 48.3l2.5 .4-2.5 .4z"/>
</g>
<path d="M72.2 53.5h10.2M81.4 55.9v19.3M73 77.6h9.4" fill="none" stroke="#4b4b4b" stroke-width=".2"/>
<g fill="#4b4b4b">
<path d="M81 75.2h.8l-.4 2.4z"/>
<path d="M81.4 53.5l.4 2.4h-.8z"/>
</g>
<g fill="none" stroke="#4b4b4b" stroke-width=".2">
<path d="M54.2 109.9v1.3M54.2 111.4v.3M54.2 111.9v1.2M54.2 113.3v.3M54.2 113.8v1.2M54.2 115.2v.3M54.2 115.7v1.2M54.2 117.1v.2M54.2 117.6v1.2M54.2 119v.2M54.2 119.5v1.2M54.2 120.9v.2"/>
<path d="M54.2 121.4v1.1M54.2 122.8v.2M54.2 123.3v1.1M54.2 124.7v.2M54.2 125.1v1.2M54.2 126.6v.2M54.2 127v1.2M54.2 128.5v.2M54.2 128.9v1.2M54.2 130.4v.2M54.2 130.8v1.3"/>
</g>
<path d="M54.2 111l1.8-.3v.6z" fill="#4b4b4b"/>
<path d="M56 111h2.1" fill="none" stroke="#4b4b4b" stroke-width=".2"/>
<path d="M54.2 130.4l1.8-.3v.6z" fill="#4b4b4b"/>
<path d="M41.2 100.7v13.7M43.6 101.6h21.2M67.2 100.7v13.7M56 130.4h2.1" fill="none" stroke="#4b4b4b" stroke-width=".2"/>
<g fill="#4b4b4b">
<path d="M41.2 101.6l2.4-.4v.9z"/>
<path d="M64.8 101.2l2.4 .4-2.4 .5z"/>
</g>
<path d="M37.6 120.2v20.7M40 139.9h28.4M70.8 120.2v20.7" fill="none" stroke="#4b4b4b" stroke-width=".2"/>
<g fill="#4b4b4b">
<path d="M37.6 139.9l2.4-.4v.8z"/>
<path d="M68.4 139.5l2.4 .4-2.4 .4z"/>
</g>
<path d="M68.2 115.3h13.1M80.3 102.4v12.9M80.3 117.8v4.1M71 124.3h10.3" fill="none" stroke="#4b4b4b" stroke-width=".2"/>
<g fill="#4b4b4b">
<path d="M79.9 121.9h.9l-.5 2.4z"/>
<path d="M80.3 115.3l.5 2.5h-.9z"/>
</g>
<path d="M45.9 107v12.7M48.3 107.9h11.6M62.3 107v12.7" fill="none" stroke="#4b4b4b" stroke-width=".2"/>
<g fill="#4b4b4b">
<path d="M59.9 107.5l2.4 .4-2.4 .4z"/>
<path d="M45.9 107.9l2.4-.4v.8z"/>
</g>
<path d="M37 126.3v1.7M37 128.4v.5M37 129.4v1.7M37 132v14.8M71.4 126.3v1.7M71.4 128.4v.5M71.4 129.4v1.7M71.4 132v14.8M39.4 145.9h29.6" fill="none" stroke="#4b4b4b" stroke-width=".2"/>
<g fill="#4b4b4b">
<path d="M37 145.9l2.4-.4v.8z"/>
<path d="M69 145.5l2.4 .4-2.4 .4z"/>
</g>
<g fill="none" stroke="#4b4b4b" stroke-width=".2">
<path d="M42.8 156.4v6.1M45.2 157.3h18M65.7 156.4v6.1M42.8 163.5v.6M42.8 164.4v.2M42.8 164.9v1.1M42.8 166.3v.2M42.8 166.7v1.2M42.8 168.2v.2M42.8 168.6v1.2M42.8 170.1v.2M42.8 170.5v1.2"/>
<path d="M42.8 171.9v.3M42.8 172.4v1.2M42.8 173.8v.3M42.8 174.3v.7M65.7 163.5v.6M65.7 164.4v.2M65.7 164.9v1.1M65.7 166.3v.2M65.7 166.7v1.2M65.7 168.2v.2M65.7 168.6v1.2M65.7 170.1v.2"/>
<path d="M65.7 170.5v1.2M65.7 171.9v.3M65.7 172.4v1.2M65.7 173.8v.3M65.7 174.3v.7"/>
</g>
<g fill="#4b4b4b">
<path d="M42.8 157.3l2.4-.4v.8z"/>
<path d="M63.2 156.9l2.5 .4-2.5 .4z"/>
</g>
<path d="M39.3 151.7v7.6M41.7 152.6h25M69.2 151.7v7.6" fill="none" stroke="#4b4b4b" stroke-width=".2"/>
<g fill="#4b4b4b">
<path d="M39.3 152.6l2.4-.4v.8z"/>
<path d="M66.7 152.2l2.5 .4-2.5 .4z"/>
</g>
<path d="M52.5 189.9h2.4M57.3 187.6v3.2M57.3 189.9h3.2M60.5 187.6v3.2M62.9 189.9h15.6" fill="none" stroke="#4b4b4b" stroke-width=".2"/>
<g fill="#4b4b4b">
<path d="M54.9 189.5l2.4 .4-2.4 .4z"/>
<path d="M60.5 189.9l2.4-.4v.8z"/>
</g>
<path d="M47.9 187.6v10.1M50.4 196.8h7.7M60.5 187.6v10.1" fill="none" stroke="#4b4b4b" stroke-width=".2"/>
<g fill="#4b4b4b">
<path d="M47.9 196.8l2.5-.5v.9z"/>
<path d="M58.1 196.3l2.4 .5-2.4 .4z"/>
</g>
<path d="M36 191.3h8.9M47.3 191.3h1.3M47.3 186.9v5.4M48.6 186.9v5.4M51 191.3h2.4" fill="none" stroke="#4b4b4b" stroke-width=".2"/>
<g fill="#4b4b4b">
<path d="M48.6 191.3l2.4-.4v.8z"/>
<path d="M44.9 190.9l2.4 .4-2.4 .4z"/>
</g>
<g fill="none" stroke="#4b4b4b" stroke-width=".2">
<path d="M116.9 134.5h2.4M121.7 130.4v5.1M121.7 134.5h4.3M123.8 123.7v.5M123.8 124.3v.1M123.8 124.5v.6M123.8 125.2v.2M123.8 125.5v.6M123.8 126.2v.1M123.8 126.4v.6M123.8 127.1v.1M123.8 127.4v.6"/>
<path d="M123.8 128.1v.1M123.8 128.3v.6M123.8 129v.1M123.8 129.3v.5M123.8 130v.1M123.8 130.2v.6M123.8 130.9v.1M123.8 131.2v.4M126 130.4v5.1M128.4 134.5h8.4M47.9 182v.3M47.9 182.3v.1"/>
<path d="M47.9 182.5v.3M47.9 182.9v.1M47.9 183v.4M47.9 183.5h.1M47.9 183.6v.3M47.9 184v.1M47.9 184.2v.3M47.9 184.6v.1M47.9 184.7v.4M47.9 185.2h.1M47.9 185.3v.4M47.9 185.7v.1"/>
<path d="M47.9 185.9v.3M47.9 186.3v.1M47.9 186.4v.3M51.1 182v.3M51.1 182.3v.1M51.1 182.5v.3M51.1 182.9v.1M51.1 183v.4M51.1 183.5h.1M51.1 183.6v.3M51.1 184v.1M51.1 184.2v.3"/>
<path d="M51.1 184.6v.1M51.1 184.7v.4M51.1 185.2h.1M51.1 185.3v.4M51.1 185.7v.1M51.1 185.9v.3M51.1 186.3v.1M51.1 186.4v.3M54.2 182v.3M54.2 182.3v.1M54.2 182.5v.3M54.2 182.9v.1"/>
<path d="M54.2 183v.4M54.2 183.5h.1M54.2 183.6v.3M54.2 184v.1M54.2 184.2v.3M54.2 184.6v.1M54.2 184.7v.4M54.2 185.2h.1M54.2 185.3v.4M54.2 185.7v.1M54.2 185.9v.3M54.2 186.3v.1"/>
<path d="M54.2 186.4v.3M57.3 182v.3M57.3 182.3v.1M57.3 182.5v.3M57.3 182.9v.1M57.3 183v.4M57.3 183.5h.1M57.3 183.6v.3M57.3 184v.1M57.3 184.2v.3M57.3 184.6v.1M57.3 184.7v.4"/>
<path d="M57.3 185.2h.1M57.3 185.3v.4M57.3 185.7v.1M57.3 185.9v.3M57.3 186.3v.1M57.3 186.4v.3M60.5 182v.3M60.5 182.3v.1M60.5 182.5v.3M60.5 182.9v.1M60.5 183v.4M60.5 183.5h.1"/>
<path d="M60.5 183.6v.3M60.5 184v.1M60.5 184.2v.3M60.5 184.6v.1M60.5 184.7v.4M60.5 185.2h.1M60.5 185.3v.4M60.5 185.7v.1M60.5 185.9v.3M60.5 186.3v.1M60.5 186.4v.3"/>
</g>
<g fill="#4b4b4b">
<path d="M119.3 134.1l2.4 .4-2.4 .4z"/>
<path d="M126 134.5l2.4-.4v.8z"/>
</g>
<path d="M113.5 126.5v16.4M123.8 132.6v10.3M115.9 141.9h5.5" fill="none" stroke="#4b4b4b" stroke-width=".2"/>
<g fill="#4b4b4b">
<path d="M113.5 141.9l2.4-.4v.8z"/>
<path d="M121.4 141.5l2.4 .4-2.4 .4z"/>
</g>
<path d="M113.5 108v5.2M115.9 109h19.3M137.6 108v5.3" fill="none" stroke="#4b4b4b" stroke-width=".2"/>
<g fill="#4b4b4b">
<path d="M113.5 109l2.4-.4v.8z"/>
<path d="M135.2 108.6l2.4 .4-2.4 .4z"/>
</g>
<path d="M105.4 113.2h5.3M106.3 115.6v8.5M105.4 126.5h5.3" fill="none" stroke="#4b4b4b" stroke-width=".2"/>
<g fill="#4b4b4b">
<path d="M106.3 113.2l.4 2.4h-.8z"/>
<path d="M105.9 124.1h.8l-.4 2.4z"/>
</g>
<path d="M27.8 119.5h7.1M28.7 107.6v9.5M28.7 119.5v4.1M27.8 123.6h7.1M28.7 126.1v2.4" fill="none" stroke="#4b4b4b" stroke-width=".2"/>
<g fill="#4b4b4b">
<path d="M28.7 123.6l.4 2.5h-.7z"/>
<path d="M28.4 117.1h.7l-.4 2.4z"/>
</g>
<g fill="none" stroke="#4b4b4b" stroke-width=".2">
<path d="M54.2 19.4v1.3M27.8 33h9.3M27.8 37.8h7.6M28.7 22.4v8.2M28.7 33v4.8M54.2 20.9v.3M54.2 21.4v1.2M54.2 22.8v.2M54.2 23.3v1.2M54.2 24.7v.2M54.2 25.2v1.2M54.2 26.6v.2"/>
<path d="M54.2 27.1v1.1M54.2 28.5v.2M54.2 29v1.1M54.2 30.4v.2M54.2 30.8v1.2M54.2 32.3v.2M54.2 32.8v1.1M54.2 34.2v.2M54.2 34.6v1.3M28.7 40.2v2.4"/>
</g>
<g fill="#4b4b4b">
<path d="M28.7 37.8l.4 2.4h-.7z"/>
<path d="M28.4 30.6h.7l-.4 2.4z"/>
</g>
<path d="M138.4 57.6h24.9M162.3 60v4.8M155.5 67.2h7.8" fill="none" stroke="#4b4b4b" stroke-width=".2"/>
<g fill="#4b4b4b">
<path d="M161.9 64.8h.8l-.4 2.4z"/>
<path d="M162.3 57.6l.4 2.4h-.8z"/>
</g>
<path d="M144.7 74.2h11.8M144.7 65.1h11.8M155.5 67.5v4.3M155.5 74.2v8.7" fill="none" stroke="#4b4b4b" stroke-width=".2"/>
<g fill="#4b4b4b">
<path d="M155.5 65.1l.4 2.4h-.8z"/>
<path d="M155.1 71.8h.8l-.4 2.4z"/>
</g>
<path d="M113 72.3v16.9M147.4 72.3v16.9M115.4 88.3h29.6" fill="none" stroke="#4b4b4b" stroke-width=".2"/>
<g fill="#4b4b4b">
<path d="M113 88.3l2.4-.5v.9z"/>
<path d="M145 87.8l2.4 .5-2.4 .4z"/>
</g>
<path d="M116.7 75.2v9.3M143.7 75.2v9.3M119.1 83.5h22.2" fill="none" stroke="#4b4b4b" stroke-width=".2"/>
<g fill="#4b4b4b">
<path d="M116.7 83.5l2.4-.4v.8z"/>
<path d="M141.3 83.1l2.4 .4-2.4 .4z"/>
</g>
<path d="M120.8 75.2v4.4M123.2 78.6h14M139.6 75.2v4.4" fill="none" stroke="#4b4b4b" stroke-width=".2"/>
<g fill="#4b4b4b">
<path d="M120.8 78.6l2.4-.4v.8z"/>
<path d="M137.2 78.2l2.4 .4-2.4 .4z"/>
</g>
<path d="M113.1 47.4h8.4M123.9 46.4v3M123.9 47.4h3.2M127.1 46.4v3M129.5 47.4h2.4" fill="none" stroke="#4b4b4b" stroke-width=".2"/>
<g fill="#4b4b4b">
<path d="M127.1 47.4l2.4-.4v.8z"/>
<path d="M121.5 47l2.4 .4-2.4 .4z"/>
</g>
<path d="M150.9 67.2h12.4M157.7 74.2h5.6M162.3 69.6v2.2M162.3 74.2v9.9" fill="none" stroke="#4b4b4b" stroke-width=".2"/>
<g fill="#4b4b4b">
<path d="M162.3 67.2l.4 2.4h-.8z"/>
<path d="M161.9 71.8h.8l-.4 2.4z"/>
</g>
<path d="M123.9 41.8v7.6M126.3 42.8h7.7M136.5 41.8v7.6" fill="none" stroke="#4b4b4b" stroke-width=".2"/>
<g fill="#4b4b4b">
<path d="M123.9 42.8l2.4-.4v.8z"/>
<path d="M134 42.4l2.5 .4-2.5 .4z"/>
</g>
<path d="M130.7 46.2h2.4M135.5 45.2v4.9M135.5 46.2h1.9M137.4 45.2v4.9M139.8 46.2h8.4" fill="none" stroke="#4b4b4b" stroke-width=".2"/>
<g fill="#4b4b4b">
<path d="M133.1 45.8l2.4 .4-2.4 .4z"/>
<path d="M137.4 46.2l2.4-.4v.8z"/>
</g>
<g fill="none" stroke="#4b4b4b" stroke-width=".2">
<path d="M123.9 50.3v.2M123.9 50.6v.1M123.9 50.7v.4M123.9 51.2h.1M123.9 51.3v.4M123.9 51.7v.1M123.9 51.9v.3M123.9 52.3v.1M123.9 52.4v.4M123.9 52.9h.1M123.9 53v.3M123.9 53.4v.1"/>
<path d="M123.9 53.6v.3M123.9 54v.1M123.9 54.1v.4M123.9 54.6h.1M123.9 54.7v.4M123.9 55.1v.1M123.9 55.3v.3M123.9 55.7v.1M123.9 55.8v.4M123.9 56.3h.1M123.9 56.4v.4M123.9 56.8v.1"/>
<path d="M123.9 57v.3M123.9 57.4v.1M123.9 57.5v.4M123.9 58h.1M123.9 58.1v.2M127.1 50.3v.2M127.1 50.6v.1M127.1 50.7v.4M127.1 51.2h.1M127.1 51.3v.4M127.1 51.7v.1M127.1 51.9v.3"/>
<path d="M127.1 52.3v.1M127.1 52.4v.4M127.1 52.9h.1M127.1 53v.3M127.1 53.4v.1M127.1 53.6v.3M127.1 54v.1M127.1 54.1v.4M127.1 54.6h.1M127.1 54.7v.4M127.1 55.1v.1M127.1 55.3v.3"/>
<path d="M127.1 55.7v.1M127.1 55.8v.4M127.1 56.3h.1M127.1 56.4v.4M127.1 56.8v.1M127.1 57v.3M127.1 57.4v.1M127.1 57.5v.4M127.1 58h.1M127.1 58.1v.2M130.2 50.3v.2M130.2 50.6v.1"/>
<path d="M130.2 50.7v.4M130.2 51.2h.1M130.2 51.3v.4M130.2 51.7v.1M130.2 51.9v.3M130.2 52.3v.1M130.2 52.4v.4M130.2 52.9h.1M130.2 53v.3M130.2 53.4v.1M130.2 53.6v.3M130.2 54v.1"/>
<path d="M130.2 54.1v.4M130.2 54.6h.1M130.2 54.7v.4M130.2 55.1v.1M130.2 55.3v.3M130.2 55.7v.1M130.2 55.8v.4M130.2 56.3h.1M130.2 56.4v.4M130.2 56.8v.1M130.2 57v.3M130.2 57.4v.1"/>
<path d="M130.2 57.5v.4M130.2 58h.1M130.2 58.1v.2M133.3 50.3v.2M133.3 50.6v.1M133.3 50.7v.4M133.3 51.2h.1M133.3 51.3v.4M133.3 51.7v.1M133.3 51.9v.3M133.3 52.3v.1M133.3 52.4v.4"/>
<path d="M133.3 52.9h.1M133.3 53v.3M133.3 53.4v.1M133.3 53.6v.3M133.3 54v.1M133.3 54.1v.4M133.3 54.6h.1M133.3 54.7v.4M133.3 55.1v.1M133.3 55.3v.3M133.3 55.7v.1M133.3 55.8v.4"/>
<path d="M133.3 56.3h.1M133.3 56.4v.4M133.3 56.8v.1M133.3 57v.3M133.3 57.4v.1M133.3 57.5v.4M133.3 58h.1M133.3 58.1v.2M136.5 50.3v.2M136.5 50.6v.1M136.5 50.7v.4M136.5 51.2h.1"/>
<path d="M136.5 51.3v.4M136.5 51.7v.1M136.5 51.9v.3M136.5 52.3v.1M136.5 52.4v.4M136.5 52.9h.1M136.5 53v.3M136.5 53.4v.1M136.5 53.6v.3M136.5 54v.1M136.5 54.1v.4M136.5 54.6h.1"/>
<path d="M136.5 54.7v.4M136.5 55.1v.1M136.5 55.3v.3M136.5 55.7v.1M136.5 55.8v.4M136.5 56.3h.1M136.5 56.4v.4M136.5 56.8v.1M136.5 57v.3M136.5 57.4v.1M136.5 57.5v.4M136.5 58h.1"/>
<path d="M136.5 58.1v.2M105.5 70.2h6.5M105.5 64.2h6.5M106.5 66.6v1.2"/>
</g>
<path d="M100.2 74.2h16.5v-9.1h4.1v9.1h18.8v-9.1h4.1v9.1h13" fill="none" stroke="#000" stroke-width=".36"/>
<path d="M123 51.1h1.9v6.5h-1.9zM126.1 51.1h1.9v6.5h-1.9zM129.2 51.1h1.9v6.5h-1.9zM132.4 51.1h1.9v6.5h-1.9zM135.5 51.1h1.9v6.5h-1.9z" fill="none" stroke="#000" stroke-width=".25"/>
<g fill="#4b4b4b">
<path d="M106.1 67.8h.8l-.4 2.4z"/>
<path d="M106.5 64.2l.4 2.4h-.8z"/>
</g>
<path d="M99.3 51.1h10.2M111.9 51.1h2.1M111.9 50.1v14.2M114 50.1v14.2M116.5 51.1h2.4" fill="none" stroke="#4b4b4b" stroke-width=".2"/>
<g fill="#4b4b4b">
<path d="M114 51.1l2.5-.4v.8z"/>
<path d="M109.5 50.7l2.4 .4-2.4 .4z"/>
</g>
<path d="M136.1 114.1h8.7M143.8 116.6v7M138.5 126.1h6.3" fill="none" stroke="#4b4b4b" stroke-width=".2"/>
<g fill="#4b4b4b">
<path d="M143.8 114.1l.4 2.5h-.8z"/>
<path d="M143.4 123.6h.8l-.4 2.5z"/>
</g>
<g fill="none" stroke="#000" stroke-width=".25">
<path d="M124.1 17.6h69v16.8h-69zM124.1 17.6h.1M223.2 16.4l.6-.1 .3 .2M223.3 16.4l-15.4 8.8M225.6 15.4l-1.7 1M225.6 15.4l3.3 1.9M225.6 15.4h-.4l-1.6 .9M227 18.1l-2.9-1.6-15.3 8.8 17.6 10.2h-.2M227 18.1a.85 .85 0 0 0 1.2 .3M227 18.1v.1M227 18.2l.4 .3M228.2 18.4h.7l2.8 1.5"/>
<path d="M228.2 18.4l7.2 4.4 .5 .1 2.9 1.6M228.9 17.3l.4 .4 .1 .5M228.9 17.3l-1.7 1M229.4 18.2l-.3 .2M229.4 18.2v.4M203.3 30.6l.3 .9M203.3 28.8v1.8l.3 .6M203.6 29.5v1.7M204.2 27.9l.3 .6M204.2 27.9a1.05 1.05 0 0 0-.9 .9M204.5 28.5l.8-.1v3.4a1.46 1.46 0 0 1-1.4 0l-.3-.6M204.5 28.5l-.3 .1a1.06 1.06 0 0 0-.6 .9l-.3-.7"/>
<path d="M205.2 27.7l-1 .2M205.3 31.8a2.63 2.63 0 0 0 1.3 1.6M205.3 28.4l.8-.2v3.3l-.8 .3M206 34.9l.7 .8M206.1 31.7l.3 .6M206.2 35.1l19.8 11.4M206.2 35.1l-.3-.5a1.53 1.53 0 0 1 .8-1.3l21.1 12.2-.5 .7M206.2 35.1l.5 .6 19.7 11.4M207.3 32.8l-.6 .5M207.9 25.2h.3l.6 .1M207.9 25.2l-2.4 1.5a.99 .99 0 0 0-.3 1l.9 .5 .1-.5 1.8-1.1M208 26.8l-1.9 1.1"/>
<path d="M208 26.7l-1.8 1M208.4 25.7l-.5 1.1 .4 .3M208.7 26l-.3-.4 .7 .1 17.1 9.8h-.5M208.7 26l15.7 9M208.7 26l-.4 1.1 15.7 9M209.3 25.6l-.2 .1M210.5 32.5l.2-.1h.6l1.9 1.1M210.7 29a.51 .51 0 0 0 .5 .5M210.7 28.5v.5l-4.6 2.7v-.2M211.3 28.8l-.3 .7M211.6 29l.2 .4M211.9 32.7v.1"/>
<path d="M212 29.2l-5.6 3.1 22 12.7-.6 .5M212 32.6l-.2 .1M212 31.3v1.3M213.7 30.4v1l-1.7 .9M213.9 30.3l-1.9 1.1v.2l-1.5 .9 2.2 1.3 1.5-.9h.4l.4-.1M214.5 30.6v.6l-.8 .2M214.5 31.2l.5-.3v1.7l.2 .4M214.9 30.9v.2a1.45 1.45 0 0 1-.7 1.2l-1.5 .9M215 32.6l.2 .4M215 31l.1 .2v-.2M215.2 33l10.9 6.3M215.3 31.1v.2"/>
<path d="M216.1 31.6l-.8 .3M217 32.1l-.1 .1M217.6 32.4l-.1 .2M218.4 32.9l-.9 .3M219.2 33.3v.2M219.8 33.7l-.1 .2M220.6 34.1l-.9 .3M221.4 34.6v.2M222 35v.1M222.8 35.4l-.8 .3M223.6 35.9v.2M224 36.1l.4-1.1 1.3 .5-.4 1.1"/>
<path d="M224 36.1l1.3 .5M224.2 36.2v.2M225 36.5v.2M225.2 36.6l-1 .4M225.8 37.3v.6l-1.6-.9v-.6l-.6-.3v.6l-1.6-1v-.6l-.6-.3v.6l-1.7-1v-.5l-.5-.4v.6l-1.7-.9v-.6l-.6-.4v.6l-1.6-.9v-.6l-.2-.1v1.6l10.9 6.2M225.8 37.3l.2 .2M226 37.5h.7M226 39h.7M226 37.5v1.5M226 39l.1 .3M226.1 36.7l-.3 .6M226.1 39.3h.5"/>
<path d="M226.3 36.5l-.2 .2 .3 .2M226.4 36.9l-.4 .6M226.4 36.9l.3 .6M226.4 36.5l.7 .5 2.4 4.2 .1 .5 .8 .5v-.2M226.4 36.5l-.6 .1h-.5M226.7 37.5v1.5M226.7 39l-.1 .3M226.7 36.7l-.3 .2M226.9 35.8l.8 .9M226.9 35.8l-.5-.3v1M227.2 37.2l-.5 .3M227.7 36.7l2.4 4.1"/>
<path d="M227.7 36.7l15.4-8.9 2.3 4.2-5.3 3.1a1.07 1.07 0 0 0-1.3-.4l-3.7 2.1a1.06 1.06 0 0 0-.4 1.4l-4.6 2.6M227.9 38.4l-1.2 .6M228 38.5l-1.4 .8M231.1 20.1l.3-.2 .4 .2 .3 .6-.2 .1M232.1 20.7l.4 .4M232.5 21.1h.1M232.5 21.1l3 1.7M234.7 38.2l.4 1.1M235.1 39.3v.2M235.1 39.3l-4.7 2.7M235.1 39.3v3.8l-4.7 2.7v-.2M235.9 22.9h.9"/>
<path d="M236.7 35.9l2.9 1.7M236.8 22.9l2.7 1.6M238.4 35h.7l.5 .6 .6-.4-.1-.1M238.8 24.5l-.1 .1a.5 .5 0 0 0 .1 .6 .5 .5 0 0 0 .6 .1l2.8 1.6M238.8 24.5l.4-.1 .5 .2M238.8 24.5v.6M239.1 39.8a.59 .59 0 0 0-.8 .6l-3.2 1.9M239.1 39.8v1M239.1 39.8l.5-.3-.1 .2zM239.1 25.2l1.7-1 3.4 2M239.1 25.2l.1 .1M239.6 35.6v3.9l.9 .5v-3.8"/>
<path d="M240.8 24.2h-.3l-1.7 1h.3M242.2 26.9l.9 .9M242.2 26.9l-15.3 8.9M244.2 26.2l.4 .4M244.2 26.2l-1.7 .9M244.6 26.6l2.2 4M244.6 26.5l-1.7 1M245.4 32l.4 1.2M245.6 32.2v.1M245.6 32.3v.1M245.6 32.3h.1M245.8 33.2l-5.3 3-.3-1"/>
<path d="M245.8 33.2v.1l.7-.4v3.4l-.2 .3-5.8 3.4a.88 .88 0 0 1-.4 .8 .88 .88 0 0 1-1 0M246.3 36.6v.3l-.4 .5-5.8 3.4M246.3 31.7a.67 .67 0 0 1 .6 .5 .67 .67 0 0 1-.4 .7M246.8 30.6l.2 .5-.1 .2-1.4 .9M246.8 30.6l-1.6 .9M246.9 32.3v3.4l-.4 .6M226 46.5l.4 .6M226.7 41.9l1.5-.9v.9l-.2 .2M226.7 41.9l.5-.2 .3 .1 1.4 .8M226.7 41.9l2.1 1.2M227.3 46.2a1.05 1.05 0 0 1-1.3 .3M227.3 46.2l.4 .6"/>
<path d="M227.7 46.8a1.01 1.01 0 0 1-1.3 .3M228.4 46l-.7 .8M228.7 44v1.7l1.1 .2M228.7 45.2l-.3-.2v1a2.02 2.02 0 0 0 1.5 .6l.5-.4v-.4M228.7 45.7v.5l1.3 .1M228.9 42.7l1.2 .1-.3 1.4-1.1-.2M228.9 42.7l-.2 1.3M229 40.2l-.8 .5v.2v-.2M229.4 41l-1.2 .6M229.6 41.7l-.4 .5-.3 .5M229.8 44.2v1.7M230.1 40.8l.3 1.2"/>
<path d="M230.1 42.8l.2-.4v3.3l-.4 .6-.1-.4M230.3 42.4l.1-.2v3.4l-.1 .1M235.1 43.1l-.1 .5-.3 .3-4.6 2.7M235.2 43.3h.1M235.4 46.5l.2 .4 .8 .5M235.8 42.7l-.5 .6 .1 3.2 .8 .5v-3M238.3 40.4l.3 .3a2.42 2.42 0 0 1 .7 1.5M239.1 40.8h-.4M239.3 42.2l-3.1 1.8a2.02 2.02 0 0 0-1-1.7v1l-.2-.1M239.3 42.2v3a1.55 1.55 0 0 1-.7 1.2l-1.8 1h-.4l-.2-.4M103.7 100h3.1v3.2h-3.1zM103.7 100h.1"/>
<path d="M105.2 100l-1.5 1.6M106.7 95.2h46.7M106.8 100l-3.1 3.2M106.8 101.6l-1.6 1.6M116.2 178.4h16"/>
</g>
<path d="M127.5 100h-1.1v1.1M128.5 100h1.1v1.1M126.4 102.1v1.1h1.1M129.6 102.1v1.1h-1.1M123.8 132.6v10.4M137.6 126.5v16.5M126.3 142h8.9M144.6 168.1h3.2" fill="none" stroke="#4b4b4b" stroke-width=".2"/>
<g fill="#4b4b4b">
<path d="M123.8 142l2.5-.4v.8z"/>
<path d="M135.2 141.6l2.4 .4-2.4 .4z"/>
</g>
<path d="M72.9 159.4h5.7M77.6 148.2v8.8M77.6 159.4v2.4M73 161.8h5.6M77.6 164.3v2.4" fill="none" stroke="#4b4b4b" stroke-width=".2"/>
<g fill="#4b4b4b">
<path d="M77.6 161.8l.4 2.5h-.8z"/>
<path d="M77.2 157h.8l-.4 2.4z"/>
</g>
<g fill="none" stroke="#000" stroke-width=".25">
<path d="M84.7 17.6h34.4v16.8h-34.4zM84.7 17.6h.1M84.7 31h5M84.7 30h5M85 30l-.3 .3M85.9 30l-1 1M86.6 30l-.9 1M87.4 30l-.9 1M88.2 30l-.9 1M89 30l-.9 1M89.1 26.6h.7M89.1 28.1v.3l.3 .3h1.1"/>
<path d="M89.1 28.1h.7M89.1 26.6v1.5M89.7 28.9v.3a1.16 1.16 0 0 0 1.1 .8v-.8M89.7 25.8h.8M89.7 28.9h.8M89.7 30.1h.8M89.7 32.6h.8M89.7 25.8v.2M89.7 28.7v.2M89.7 30.9v.1M89.7 30.1l-.8 .9M89.8 28.1l.1 .5 .2 .1"/>
<path d="M89.8 26.6v1.5M89.9 29.5l-.2 .6M90 25l-.3 .8M90 25l.6 .6M90.1 26l-.2 .1-.1 .5M90.4 26v2.7M90.5 28.9l.3 .3M90.5 31h22.2M90.5 30.1v3.1h-.8v-3.1M90.5 25.8v3.1M90.5 26h-1.1l-.3 .3v.3M90.6 25.6l-.1 .2"/>
<path d="M90.8 29.2h21.6M91.4 30l-.9 .9M91.7 30h-1l-.2 .1M91.7 29.2v1.1v.2l.6 .1M91.7 29.6v.2l.6 .1M91.7 29.3h19.8M91.7 30.5l-.5 .5M92.3 22.7l-2.3 2.3M92.3 29.9h18.6M92.3 30.6h18.6M92.3 29.9v.7M92.4 30.6l-.4 .4"/>
<path d="M92.9 23.3h17.3l2.4 2.4v3.1l-.5 .3h-21.2l-.3-.5v-2.8zM92.9 30.6v.2h2.1v-.2M93 30.8l-.2 .2M93.1 22.4l-.8 .3M93.1 22.4v.8l-.3 .1-.5-.6M93.1 22.4h.4M93.5 23h16.1M93.9 30.8l-.3 .2M94.2 21.7h14.8M94.2 22.4l-.6 .2-.1 .2M94.2 22.4h14.8M94.2 21.7v.7"/>
<path d="M94.2 21.7l-.6 .2-.1 .2v1.1M94.6 30.8l-.2 .2M95.6 30.6l-.4 .4M95.9 29.1v.1M96.1 28l.3 .3M96.1 26.7h.5M96.1 26.7v1.3M96.1 28h10.9M96.4 30.6l-.4 .4M96.4 26.4l-.3 .3M96.4 26.4h.4v.8M96.4 28.3h10.3"/>
<path d="M96.4 26.4v1.9M96.6 23.2h.1M96.7 26.4l-.1 .3M96.8 26.7h1.2M96.8 27.1h1.2M97.2 30.6l-.4 .4M98 30.6l-.4 .4M98.1 26.4l.1 .8h-1.6v-.5M98.2 26.7h.5M98.7 26.7v.5h1.6v-.5M98.7 30.6l-.3 .4M98.8 26.4l-.1 .3"/>
<path d="M98.9 26.7h1.2M98.9 27.1h1.2M98.9 27.2v-.8h-.9v.8M99.3 23.2h.1M99.5 30.6l-.3 .4M100.1 27.2v-.8h.9v.8M100.2 26.4l.1 .3M100.3 26.7h.5M100.3 30.6l-.3 .4M100.9 26.4l-.1 .3M101 26.7h1.2M101 27.1h1.2"/>
<path d="M101.1 30.6l-.3 .4M101.9 30.6l-.3 .4M102.2 27.2v-.8h.9v.8M102.3 26.4l.1 .3M102.4 26.7h.5M102.4 26.7v.5h-1.6v-.5M102.7 30.6l-.3 .4M103 26.4l-.1 .3M103.1 26.7h1.2M103.1 27.1h1.2M103.5 30.6l-.3 .4M103.9 23.2h.1"/>
<path d="M104.3 27.2v-.8h.9v.8M104.3 30.6l-.3 .4M104.4 26.4l.1 .3M104.5 26.7h.5M104.5 26.7v.5h-1.6v-.5M105.1 26.4l-.1 .3M105.1 30.6l-.3 .4M105.2 26.7h1.2M105.2 27.1h1.2M105.9 30.6l-.3 .4M106.5 26.4l.1 .3M106.6 26.7v.5h-1.6v-.5"/>
<path d="M106.6 26.7h.4M106.6 23.2h.1M106.7 26.4l.3 .3M106.7 26.4v1.9M106.7 26.4h-.3v.8M106.7 30.6l-.3 .4M107 28l-.3 .3M107 26.7v1.3M107.1 29.1l.1 .1M107.5 30.6l-.3 .4M108.2 30.6v.2M108.2 30.8l-.2 .2"/>
<path d="M109 30.8l-.2 .2M109 22.4l.3 .1 .3 .3M109 21.7l.6 .2v.2v1.1M109 21.7v.7M109.6 22.4h.5M109.8 30.8l-.2 .2M110.1 22.4l.8 .3M110.1 22.4v.8l.3 .1 .5-.6M110.3 30.6v.2h-2.1M110.7 30.6l-.3 .4M110.9 29.9v.7M110.9 22.7l2.3 2.3"/>
<path d="M111.5 30h1l.2 .1M111.5 29.2v1.1v.2l-.6 .1M111.5 29.6v.2l-.6 .1M112.1 30l-1 1M112.6 25.6l.1 .2M112.6 25.6l-2.3-2.4h-17.4l-2.3 2.4M112.7 28.9l-.3 .3M112.7 26h1.1l.3 .3v.3M112.7 30.1v3.1h.8v-3.1M112.7 25.8v3.1M112.7 25.8h.8M112.7 28.9h.8"/>
<path d="M112.7 30.1h.8M112.7 32.6h.8M112.7 30.2l-.7 .8M112.8 26v2.7M113.1 26l.3 .3v.3M113.2 25l.3 .8M113.2 25l-.6 .6M113.3 29.5l.2 .6M113.4 26.6v1.5M113.4 26.6h.7M113.4 28.1v.3l-.3 .3M113.4 28.1h.7"/>
<path d="M113.5 28.9v.3a1.16 1.16 0 0 1-1.1 .8v-.8M113.5 30h5.6M113.5 31h5.6M113.5 25.8v.2M113.5 28.7v.2M113.7 30l-.2 .2M114.1 28.1v.3l-.3 .3h-1.1M114.1 26.6v1.5M114.5 30l-1 1M115.3 30l-1 1M116.1 30l-1 1M116.9 30l-1 1"/>
<path d="M117.7 30l-1 1M118.5 30l-1 1M119.1 30.2l-.8 .8"/>
</g>
<path d="M47.5 124.1l-2.5 8.1" fill="none" stroke="#4b4b4b" stroke-width=".2"/>
<path d="M48.2 121.8l-.4 2.4-.7-.2z" fill="#4b4b4b"/>
<path d="M35.7 132.2h9.3M60.9 124.1l2.5 8.1" fill="none" stroke="#4b4b4b" stroke-width=".2"/>
<path d="M60.2 121.8l1.1 2.2-.7 .2z" fill="#4b4b4b"/>
<path d="M120.8 40.7l2.4 8.1M63.4 132.2h9.8" fill="none" stroke="#4b4b4b" stroke-width=".2"/>
<path d="M122.9 48.9l.7-.3 .3 2.5z" fill="#4b4b4b"/>
<path d="M116.2 40.7h4.6M139.2 40.7l-2.5 8.1" fill="none" stroke="#4b4b4b" stroke-width=".2"/>
<path d="M136.3 48.6l.8 .3-1.1 2.2z" fill="#4b4b4b"/>
<path d="M139.2 40.7h4.5M131.4 60.2v1.5M133.8 61.2h1.9M138.1 60.2v1.5M138.1 61.2h8.2" fill="none" stroke="#4b4b4b" stroke-width=".2"/>
<g fill="none" stroke="#000" stroke-width=".25">
<path d="M123.8 51.1l-.8 .9M124.9 53.4l-1.9 2M124.9 55.2l-1.9 1.9M124.9 56.9l-.7 .7M127 51.1l-.9 .9M128 51.7l-1.9 1.9M128 53.4l-1.9 2M128 55.2l-1.9 1.9M128 56.9l-.7 .7M130.1 51.1l-.9 .9M131.1 51.7l-1.9 1.9M131.1 53.4l-1.9 2"/>
<path d="M131.1 55.2l-1.9 1.9M131.1 56.9l-.6 .7M133.2 51.1l-.8 .9M134.3 51.7l-1.9 1.9M134.3 53.4l-1.9 2M134.3 55.2l-1.9 1.9M134.3 56.9l-.7 .7M136.4 51.1l-.9 .9M137.4 51.7l-1.9 1.9M137.4 53.4l-1.9 2M137.4 55.2l-1.9 1.9M137.4 56.9l-.7 .7"/>
<path d="M122.3 62.6h6.7v9.2h-6.7zM123.1 62.6l-.8 .9M124.8 62.6l-2.5 2.6M126.5 62.6l-4.2 4.3M128.2 62.6l-5.9 6M129 70.4l-1.4 1.4M129 68.7l-3.1 3.1M129 67l-4.9 4.8M129 63.5l-6.7 6.8M129 65.2l-6.6 6.6M131.4 62.6h6.7v9.2h-6.7zM132.2 62.6l-.8 .9"/>
<path d="M133.9 62.6l-2.5 2.6M135.6 62.6l-4.2 4.3M137.3 62.6l-5.9 6M138.1 70.4l-1.4 1.4M138.1 68.7l-3.1 3.1M138.1 67l-4.8 4.8M138.1 63.5l-6.7 6.8M138.1 65.2l-6.5 6.6M230.6 154.7h19.1v5.8h-19.1zM230.6 154.7h.1M231.5 157.5h17.1"/>
</g>
<g fill="#4b4b4b">
<path d="M131.4 61.2l2.4-.4v.8z"/>
<path d="M135.7 60.8l2.4 .4-2.4 .4z"/>
</g>
<path d="M115.8 59.7h10.8M129 59.7h2.4M129 58.8v2.9M131.4 58.8v2.9M133.8 59.7h2.4" fill="none" stroke="#4b4b4b" stroke-width=".2"/>
<g fill="#4b4b4b">
<path d="M131.4 59.7l2.4-.4v.8z"/>
<path d="M126.6 59.3l2.4 .4-2.4 .4z"/>
</g>
<path d="M99.7 71.8h21.6M99.7 62.6h21.6M100.6 65v4.4" fill="none" stroke="#4b4b4b" stroke-width=".2"/>
<g fill="#4b4b4b">
<path d="M100.2 69.4h.8l-.4 2.4z"/>
<path d="M100.6 62.6l.4 2.4h-.8z"/>
</g>
<g fill="none" stroke="#000" stroke-width=".2">
<path d="M10.5 9.8h276.1v190.5h-276.1zM10.5 5h-4.8v4.8M44.6 7.4v2.4M78.8 7.4v2.4M113 7.4v2.4M147.2 7.4v2.4M181.3 7.4v2.4M215.5 7.4v2.4M249.7 7.4v2.4M286.6 5h4.8v4.8M8.1 33.6h2.4M286.6 33.6h2.4"/>
<path d="M8.1 57.4h2.4M286.6 57.4h2.4M8.1 81.2h2.4M286.6 81.2h2.4M8.1 105h4.7M284.2 105h4.8M8.1 128.8h2.4M286.6 128.8h2.4M8.1 152.7h2.4M286.6 152.7h2.4M8.1 176.5h2.4M194.6 178.4v10.3"/>
<path d="M257.5 178.4v21.9M286.6 176.5h2.4M286.6 178.4h-123.7v21.9M162.9 180.8h94.6M162.9 188.7h94.6M162.9 191.2h20.5M162.9 195.9h20.5M162.9 186h31.7M162.9 183.5h31.7M162.9 198h20.5M171.5 188.7v11.6M183.4 188.7v11.6"/>
<path d="M183.4 192.4h21.5M194 192.4v7.9M204.9 188.7v11.6M204.9 194.5h11.4M206.9 196.6h.9M208 196.6h.3M208.2 195.5v.7M208.2 196.5v.2M208.2 197v.7M208.5 196.6h.9M209.7 196.6h4.8M210.2 196l3.3-.3v1.9l-3.3-.4z"/>
<path d="M216.3 188.7v11.6M217.9 196.8v.2a1.29 1.29 0 0 0 1.3 .4h6.6M224.8 198.1l.3-.2 .2 .3 .5-.8a.74 .74 0 0 1 1-.5l-1.2 1.7a.39 .39 0 0 1-.5 .3 .39 .39 0 0 1-.3-.5zM226.6 196.8v-5.1a1.5 1.5 0 0 0-.3-1.5 7 7 0 0 0-2.9-.1h-4.9a.64 .64 0 0 0-.7 .6v7.3a1.28 1.28 0 0 0 .3 1.3l6.8 .1a1.95 1.95 0 0 0 1.6-.3l.1-1.8M228.2 188.7v11.6M257.5 195h29.1M265.9 195v5.3M276.1 195v5.3M5.7 200.3v4.7h4.8M44.6 200.3v2.4M78.8 200.3v2.4M113 200.3v2.4"/>
<path d="M147.2 200.3v2.4M181.3 200.3v2.4M215.5 200.3v2.4M249.7 200.3v2.4M291.4 200.3v4.7h-4.8"/>
<circle cx="208.2" cy="196.6" r=".95"/>
<circle cx="208.2" cy="196.6" r=".59"/>
<circle cx="231.5" cy="194.3" r="2.2"/>
</g>
<g fill="#000" stroke="#000" stroke-width=".2">
<path d="M218.7 195.9h.3l-.1 .2-.2-.1z" fill-rule="evenodd"/>
<path d="M218.5 197.9l.6 .1h-.4v.7h.4l-.1 .2h-.5z" fill-rule="evenodd"/>
<path d="M218.7 194.3l.3-.2 .3 .2h-.4l-.1 .2v.4l.5 .1-.1 .2h-.3l-.3-.3z" fill-rule="evenodd"/>
<path d="M218.8 195.8l.3-.1 .2 .1v.4l-.4 .4h.4v.2h-.6l.4-.7v-.2h-.4z" fill-rule="evenodd"/>
<path d="M218.7 198l.5 .1-.1 .6h-.4h.2l.1-.2v-.4z" fill-rule="evenodd"/>
<path d="M219.2 194.8l.2 .1-.1 .1h-.3z" fill-rule="evenodd"/>
<path d="M219 194.3l.4 .1-.2 .1z" fill-rule="evenodd"/>
<path d="M219.4 198.3h.2l-.1 .2h.4v.1h-.4l.1 .2h.3a.3 .3 0 0 1-.4 .1 .3 .3 0 0 1-.2-.3z" fill-rule="evenodd"/>
<path d="M218.7 191h1.1l.5 .4h-1.2v.7h1.1l-.3 .4h-.8v1h-.4z" fill-rule="evenodd"/>
<path d="M219.6 194.3h.3l-.2 .1v.4l.1 .2h.4l-.1 .2h-.3l-.2-.2z" fill-rule="evenodd"/>
<path d="M219.4 198.2h.4l.1 .3h-.4l.2-.1-.3-.1z" fill-rule="evenodd"/>
<path d="M219.7 198.7l.2 .1h-.3z" fill-rule="evenodd"/>
<path d="M219.6 195.8l.2-.1 .2 .2h-.2l-.2 .2 .1 .5h.3a.31 .31 0 0 1-.3 .2 .31 .31 0 0 1-.2-.4z" fill-rule="evenodd"/>
<path d="M219.2 192.5h.7l.6 1h-.5l-.5-.9z" fill-rule="evenodd"/>
<path d="M219.7 194.1h.3l.3 .2-.1 .7h-.3l.2-.2v-.3l-.1-.2h-.4z" fill-rule="evenodd"/>
<path d="M219.8 195.9h.2v.7h-.2l.1-.3z" fill-rule="evenodd"/>
<path d="M220 198.3h.3l-.1 .3 .4 .2-.1 .1-.4-.1z" fill-rule="evenodd"/>
<path d="M219.4 191.4h.9l-.1 .7h-1.1l.8-.2v-.4z" fill-rule="evenodd"/>
<path d="M220.3 196h.2l-.2 .2z" fill-rule="evenodd"/>
<path d="M220.1 198.2l.3-.1 .2 .3z" fill-rule="evenodd"/>
<path d="M220.4 198.6l.2 .1v.1h-.3z" fill-rule="evenodd"/>
<path d="M220.3 196l.4-.3v1.1h-.2v-.8z" fill-rule="evenodd"/>
<path d="M220.7 198.8h.4l-.2 .1z" fill-rule="evenodd"/>
<path d="M220.5 194.1h.2l-.1 1.1h-.1z" fill-rule="evenodd"/>
<path d="M220.7 194.1l.2 .7-.1 .4-.2-.8z" fill-rule="evenodd"/>
<path d="M220.7 198.6h.4l-.2 .1 .3 .1 .1 .1-.6-.1z" fill-rule="evenodd"/>
<path d="M220.8 198.2l.3-.1 .1 .2-.4 .1-.1-.1z" fill-rule="evenodd"/>
<path d="M221 196h.3l-.3 .2z" fill-rule="evenodd"/>
<path d="M220.9 198.3h.3v.5h-.3l.2-.2-.4-.1 .4-.1z" fill-rule="evenodd"/>
<path d="M221 194.1h.3l-.3 1.1h-.2z" fill-rule="evenodd"/>
<path d="M221.3 194.1v1.1h-.2v-.8z" fill-rule="evenodd"/>
<path d="M221 191.8l.6-.1 .3 .3-.6 .1a.62 .62 0 0 0-.3 .5 .62 .62 0 0 0 .3 .6l-.6-.1a1.19 1.19 0 0 1 .3-1.3z" fill-rule="evenodd"/>
<path d="M221.4 198.4h.3v.2h-.3z" fill-rule="evenodd"/>
<path d="M221 196l.4-.3v1.1h-.1v-.8z" fill-rule="evenodd"/>
<path d="M221.9 195.7h.2l-.3 1.1h-.1z" fill-rule="evenodd"/>
<path d="M221.5 194.1h.5l.1 .2h-.4v.3h.4l-.1 .2h-.3v.4h-.2z" fill-rule="evenodd"/>
<path d="M221.3 192.1l.6-.1a.97 .97 0 0 1-.7 1.6l-.5-.4h.6a.62 .62 0 0 0 .4-.6 .62 .62 0 0 0-.4-.5z" fill-rule="evenodd"/>
<path d="M221.7 194.3h.4v.3h-.4l.3-.1z" fill-rule="evenodd"/>
<path d="M221.8 197.9l.6 .1h-.4v.3h.4l.1 .1h-.5v.3h.5l-.1 .2h-.6z" fill-rule="evenodd"/>
<path d="M222.3 194.1h.2v.9h.4v.2h-.6z" fill-rule="evenodd"/>
<path d="M222.3 195.8l.2-.1 .2 .2h-.4v.3h.4h-.3a.19 .19 0 0 0-.1 .2 .19 .19 0 0 0 .2 .2h-.3l-.1-.1z" fill-rule="evenodd"/>
<path d="M222.1 198h.4v.2l-.5 .1 .3-.1v-.2z" fill-rule="evenodd"/>
<path d="M222.3 196.2h.4z" fill-rule="evenodd"/>
<path d="M222.1 198.4h.4v.3h-.5h.3v-.2z" fill-rule="evenodd"/>
<path d="M222.4 196.2h.3l.1 .3a.32 .32 0 0 1-.3 .3 .32 .32 0 0 1-.3-.1l.3-.1z" fill-rule="evenodd"/>
<path d="M222.4 195.9l.3 .1z" fill-rule="evenodd"/>
<path d="M222.4 191h.4v1l.7 .4h-.7v1.1h-.4z" fill-rule="evenodd"/>
<path d="M222.7 197.9l.6 .1h-.5v.7h.5l-.1 .2h-.5z" fill-rule="evenodd"/>
<path d="M223 194.1h.2v1.1h-.2z" fill-rule="evenodd"/>
<path d="M222.9 196.5l.6 .1-.4 .2z" fill-rule="evenodd"/>
<path d="M223.1 196.1h.3z" fill-rule="evenodd"/>
<path d="M222.9 198h.4v.7h-.5l.4-.1v-.5z" fill-rule="evenodd"/>
<path d="M223.2 196.2h.3v.4h-.3l.1-.1z" fill-rule="evenodd"/>
<path d="M223 195.7h.5v.2h-.4v.2l.4 .1-.6 .1z" fill-rule="evenodd"/>
<path d="M223.8 195.7h.1l-.2 1.1h-.1z" fill-rule="evenodd"/>
<path d="M223.6 194.1h.2l-.2 .7 .3 .2h-.4v.2h-.2z" fill-rule="evenodd"/>
<path d="M223.8 194.1l.4 1.1h-.2l-.4-.4h.2z" fill-rule="evenodd"/>
<path d="M223.5 191h.4v2.5h-.4v-1.1l-.7-.4h.7z" fill-rule="evenodd"/>
<path d="M223.5 197.9h.7v.1h-.5v.3h.5v.1h-.5v.3h.5v.2h-.7z" fill-rule="evenodd"/>
<path d="M224.2 194.1h.2v1.1h-.2z" fill-rule="evenodd"/>
<path d="M224.4 194.1l.4 .7-.1 .4-.3-.7z" fill-rule="evenodd"/>
<path d="M224.2 192.7h.4l.2 .3 .3 .2h-.7z" fill-rule="evenodd"/>
<path d="M224 195.7h.8v.2h-.6v.2h.5v.2h-.5v.3h.6v.2h-.8z" fill-rule="evenodd"/>
<path d="M224.8 194.1h.1v1.1h-.2z" fill-rule="evenodd"/>
<path d="M224.6 191.1a.79 .79 0 0 1 1.1 .3h-.8a.33 .33 0 0 0-.1 .4 .33 .33 0 0 0 .4 .2 .81 .81 0 0 1 .5 1.3 .81 .81 0 0 1-1.3-.1h.7a.37 .37 0 0 0 .3-.5 .37 .37 0 0 0-.5-.3 .76 .76 0 0 1-.6-.5 .76 .76 0 0 1 .3-.8z" fill-rule="evenodd"/>
<path d="M224.9 195.7h.2v.8l.2 .1h-.3z" fill-rule="evenodd"/>
<path d="M225 191.4h.7l.1 .3-.4 .1-.2-.4z" fill-rule="evenodd"/>
<path d="M225.5 195.7h.2v.9l-.3 .2h-.2l-.2-.2 .5-.1z" fill-rule="evenodd"/>
<path d="M225.1 194.1h.6v.2h-.2v.9h-.2v-.9h-.2z" fill-rule="evenodd"/>
</g>
<g fill="none" stroke="#000" stroke-width=".25">
<path d="M261.4 185.3l-1.2 1.3M261.4 185.1l-1.3 1.3M261.4 185.5l-1.2 1.2M261.4 184.9l-1.3 1.3M261.5 185.7l-1.2 1.2M261.5 182a4.3 4.3 0 0 1 6.4 1.1l-1.2 .7a2.82 2.82 0 0 0-4.5-.6 2.82 2.82 0 0 0 .6 4.5 2.82 2.82 0 0 0 4.2-1.7h-1.9a1.11 1.11 0 0 1-1.6 0 1.11 1.11 0 0 1 0-1.6 1.11 1.11 0 0 1 1.6 .1h3.4a4.3 4.3 0 0 1-5.7 4.8 4.3 4.3 0 0 1-1.3-7.3zM261.5 185.9l-1.1 1.1M261.5 184.6l-1.5 1.4M261.5 186.1l-1.1 1.1M261.6 184.3l-1.6 1.6M261.6 181.9l-.7 .7M261.6 186.2l-1.1 1.1"/>
<path d="M261.7 186.4l-1.1 1.1M261.7 186.5l-1 1.1M261.7 183.9l-1.7 1.8M261.8 186.7l-1 1M261.9 186.8l-1.1 1M262 186.9l-1.1 1.1M262.1 187.1l-1.1 1M262.2 187.2l-1 1M262.2 181.5l-1.7 1.7M262.3 187.3l-1 1M262.4 187.4l-1 1M262.5 187.5l-1 1"/>
<path d="M262.6 181.3l-2.3 2.3M262.7 187.6l-1.1 1M262.8 187.6l-1.1 1.1M262.9 187.7l-1 1.1M263 181.2l-2.9 2.8M263.1 187.8l-1.1 1.1M263.2 187.9l-1.1 1.1M263.3 181.1l-3.2 3.2M263.4 187.9l-1.1 1.1M263.5 181l-3.5 3.5M263.5 188l-1.1 1.1M263.7 188l-1.1 1.2"/>
<path d="M263.8 181l-3.8 3.8M263.9 184.2l-.7 .7M263.9 188l-1.2 1.2M264 181l-4 4M264.1 188.1l-1.2 1.2M264.1 184.1l-1 1M264.2 181l-4.3 4.3M264.4 188.1l-1.3 1.2M264.4 184.1l-1.3 1.3M264.5 181l-4.5 4.5M264.5 184.2l-1.3 1.3M264.6 188l-1.4 1.4"/>
<path d="M264.7 181l-1.8 1.8M264.7 184.2l-1.5 1.5M264.8 184.3l-1.5 1.5M264.9 181l-1.6 1.6M264.9 188l-1.5 1.4M265 184.4l-1.6 1.6M265 181l-1.4 1.5M265.1 184.5l-1.6 1.6M265.2 187.9l-1.6 1.6M265.2 181.1l-1.3 1.3M265.3 184.5l-1.7 1.7M265.4 181.1l-1.3 1.3"/>
<path d="M265.5 184.5l-1.7 1.8M265.5 187.7l-1.7 1.8M265.6 181.2l-1.3 1.2M265.7 184.5l-1.8 1.8M265.7 181.2l-1.2 1.2M265.9 181.3l-1.2 1.2M265.9 184.5l-1.8 1.8M266 181.4l-1.1 1.1M266.1 184.5a1.97 1.97 0 0 0-3.1-.8 1.97 1.97 0 0 0 0 3.1 1.97 1.97 0 0 0 3.1-.8M266.1 184.5l-1.8 1.9M266.2 181.4l-1.1 1.1M266.3 181.5l-1.1 1.1"/>
<path d="M266.4 184.5l-1.8 1.8M266.5 181.6l-1.1 1.1M266.6 181.7l-1.1 1M266.6 184.5l-1.5 1.5M266.7 181.8l-1 1M266.8 184.5l-1.5 1.5M266.8 181.8l-1 1.1M267 182l-1.1 1M267 184.5l-1.4 1.5M267.1 182l-1.1 1.1M267.2 182.1l-1 1.1M267.2 184.5l-1.4 1.5"/>
<path d="M267.3 182.3l-1 1M267.4 182.4l-1 1M267.5 184.5l-1.5 1.5M267.5 182.5l-1 1M267.6 182.6l-1 1M267.7 187.8l-.9 .9M267.7 184.5l-1.5 1.5M267.7 182.7l-1 1.1M267.8 182.9l-.8 .7M267.9 184.5l-1.5 1.5M267.9 183l-.4 .3M268 187.2l-1.8 1.8"/>
<path d="M268.1 184.5l-1.4 1.5M268.2 186.8l-2.4 2.4M268.3 186.5l-2.8 2.8M268.3 184.5l-1.4 1.5M268.4 186.2l-3.2 3.2M268.5 184.6l-1.6 1.6M268.5 185.9l-3.6 3.6M268.5 185.7l-3.9 3.8M268.5 184.8l-1.8 1.7M268.5 185.4l-4.1 4.1M268.5 185.2l-4.3 4.3M268.5 185l-4.5 4.5"/>
<path d="M270.2 182.2a4.3 4.3 0 0 1 6.1 0l-1 1a2.82 2.82 0 0 0-4 0 2.82 2.82 0 0 0 0 4 2.82 2.82 0 0 0 4 0l1 1a4.3 4.3 0 0 1-6 .1 4.3 4.3 0 0 1-.1-6.1zM270.4 185l-1.3 1.3M270.4 185.2l-1.2 1.3M270.4 185.4l-1.2 1.3M270.5 185.6l-1.2 1.2M270.5 184.7l-1.4 1.4M270.5 185.8l-1.1 1.2M270.6 184.5l-1.6 1.5M270.6 186l-1.2 1.1M270.6 186.2l-1.1 1M270.7 184.1l-1.7 1.7M270.7 186.3l-1.1 1.1"/>
<path d="M270.7 186.5l-1 1M270.8 186.6l-1.1 1.1M270.9 186.7l-1 1.1M270.9 183.7l-1.9 1.9M271 186.9l-1.1 1M271 181.6l-1.4 1.4M271.1 187l-1.1 1M271.2 187.1l-1 1M271.3 187.2l-1 1.1M271.4 187.3l-1 1.1M271.5 181.3l-2.1 2.2M271.5 187.4l-1 1.1"/>
<path d="M271.6 187.5l-1 1.1M271.8 187.6l-1.1 1.1M271.9 181.2l-2.7 2.6M271.9 187.7l-1.1 1.1M272 187.8l-1 1M272.2 181.1l-3.1 3M272.2 187.8l-1.1 1.1M272.4 187.9l-1.1 1.1M272.5 181l-3.4 3.4M272.5 187.9l-1.1 1.2M272.7 188l-1.2 1.1M272.7 181l-3.7 3.7"/>
<path d="M272.9 188l-1.2 1.2M273 181l-4 3.9M273.1 188.1l-1.2 1.2M273.2 181l-4.2 4.2M273.3 188.1l-1.3 1.2M273.4 181l-4.4 4.4M273.5 188l-1.3 1.4M273.6 181l-1.9 1.9M273.8 188l-1.4 1.4M273.8 181l-1.6 1.6M274 181l-1.5 1.5M274.1 187.9l-1.5 1.5"/>
<path d="M274.2 181.1l-1.4 1.3M274.4 181.1l-1.4 1.3M274.4 187.8l-1.6 1.7M274.5 181.2l-1.2 1.2M274.7 181.2l-1.2 1.2M274.8 181.3l-1.1 1.1M274.9 187.5l-2 2M275 181.3l-1.1 1.2M275.1 181.4l-1.1 1.1M275.3 181.5l-1.1 1.1M275.3 187.3l-2.1 2.2M275.4 181.6l-1 1"/>
<path d="M275.4 187.4l-2 2.1M275.6 181.6l-1.1 1.1M275.6 187.5l-2 2M275.7 187.6l-1.8 1.8M275.7 181.7l-1.1 1.1M275.8 187.8l-1.7 1.6M275.8 181.8l-1 1M275.9 187.9l-1.5 1.4M275.9 181.9l-1 1.1M276 188l-1.3 1.2M276.1 182l-1.1 1M276.1 188.1l-1 1"/>
<path d="M276.2 182.1l-1.1 1M276.2 188.2l-.6 .6M276.8 181h7v1.5h-2.8M276.8 181v1.5h2.7v6.9h1.5v-6.9M276.8 181v.1M277 181l-.2 .3M277.2 181l-.4 .5M277.5 181l-.7 .7M277.7 181l-.9 1M277.9 181l-1.1 1.2M278.1 181l-1.3 1.4M278.3 181l-1.4 1.5"/>
<path d="M278.6 181l-1.5 1.5M278.8 181l-1.5 1.5M279 181l-1.5 1.5M279.2 181l-1.5 1.5M279.4 181l-1.4 1.5M279.7 181l-1.5 1.5M279.9 181l-1.5 1.5M280.1 181l-1.5 1.5M280.3 181l-1.5 1.5M280.5 181l-1.4 1.5M280.7 181l-1.4 1.5M280.9 181l-1.4 1.5"/>
<path d="M281 189.3l-.1 .1M281 189l-.3 .4M281 188.8l-.5 .6M281 188.6l-.8 .8M281 188.4l-1 1M281 188.2l-1.2 1.2M281 183.8l-1.5 1.5M281 184l-1.5 1.5M281 184.3l-1.5 1.4M281 184.5l-1.5 1.4M281 184.7l-1.5 1.4M281 184.9l-1.5 1.5"/>
<path d="M281 185.1l-1.5 1.5M281 185.3l-1.5 1.5M281 185.6l-1.5 1.4M281 185.8l-1.5 1.4M281 186l-1.5 1.5M281 186.2l-1.5 1.5M281 186.4l-1.5 1.5M281 186.7l-1.5 1.4M281 186.9l-1.5 1.4M281 187.1l-1.5 1.4M281 187.3l-1.5 1.5M281 187.5l-1.5 1.5"/>
<path d="M281 187.8l-1.5 1.4M281 188l-1.4 1.4M281 182.5l-1.5 1.5M281 182.7l-1.5 1.5M281 183l-1.5 1.4M281 183.2l-1.5 1.4M281 183.4l-1.5 1.4M281 183.6l-1.5 1.5M281.2 181l-1.7 1.7M281.4 181l-1.9 1.9M281.6 181l-2.1 2.1M281.8 181l-2.3 2.3"/>
<path d="M282 181l-2.5 2.5M282.3 181l-2.8 2.8M282.5 181l-1.5 1.5M282.7 181l-1.5 1.5M282.9 181l-1.4 1.5M283.1 181l-1.4 1.5M283.4 181l-1.5 1.5M283.6 181l-1.5 1.5M283.8 181l-1.5 1.5M283.8 181.7l-.8 .8M283.8 181.5l-1 1M283.8 182.1l-.4 .4"/>
<path d="M283.8 181.3l-1.2 1.2M283.8 181.9l-.6 .6M283.8 182.4l-.2 .1"/>
</g>
<use href="#words"/>
</svg>
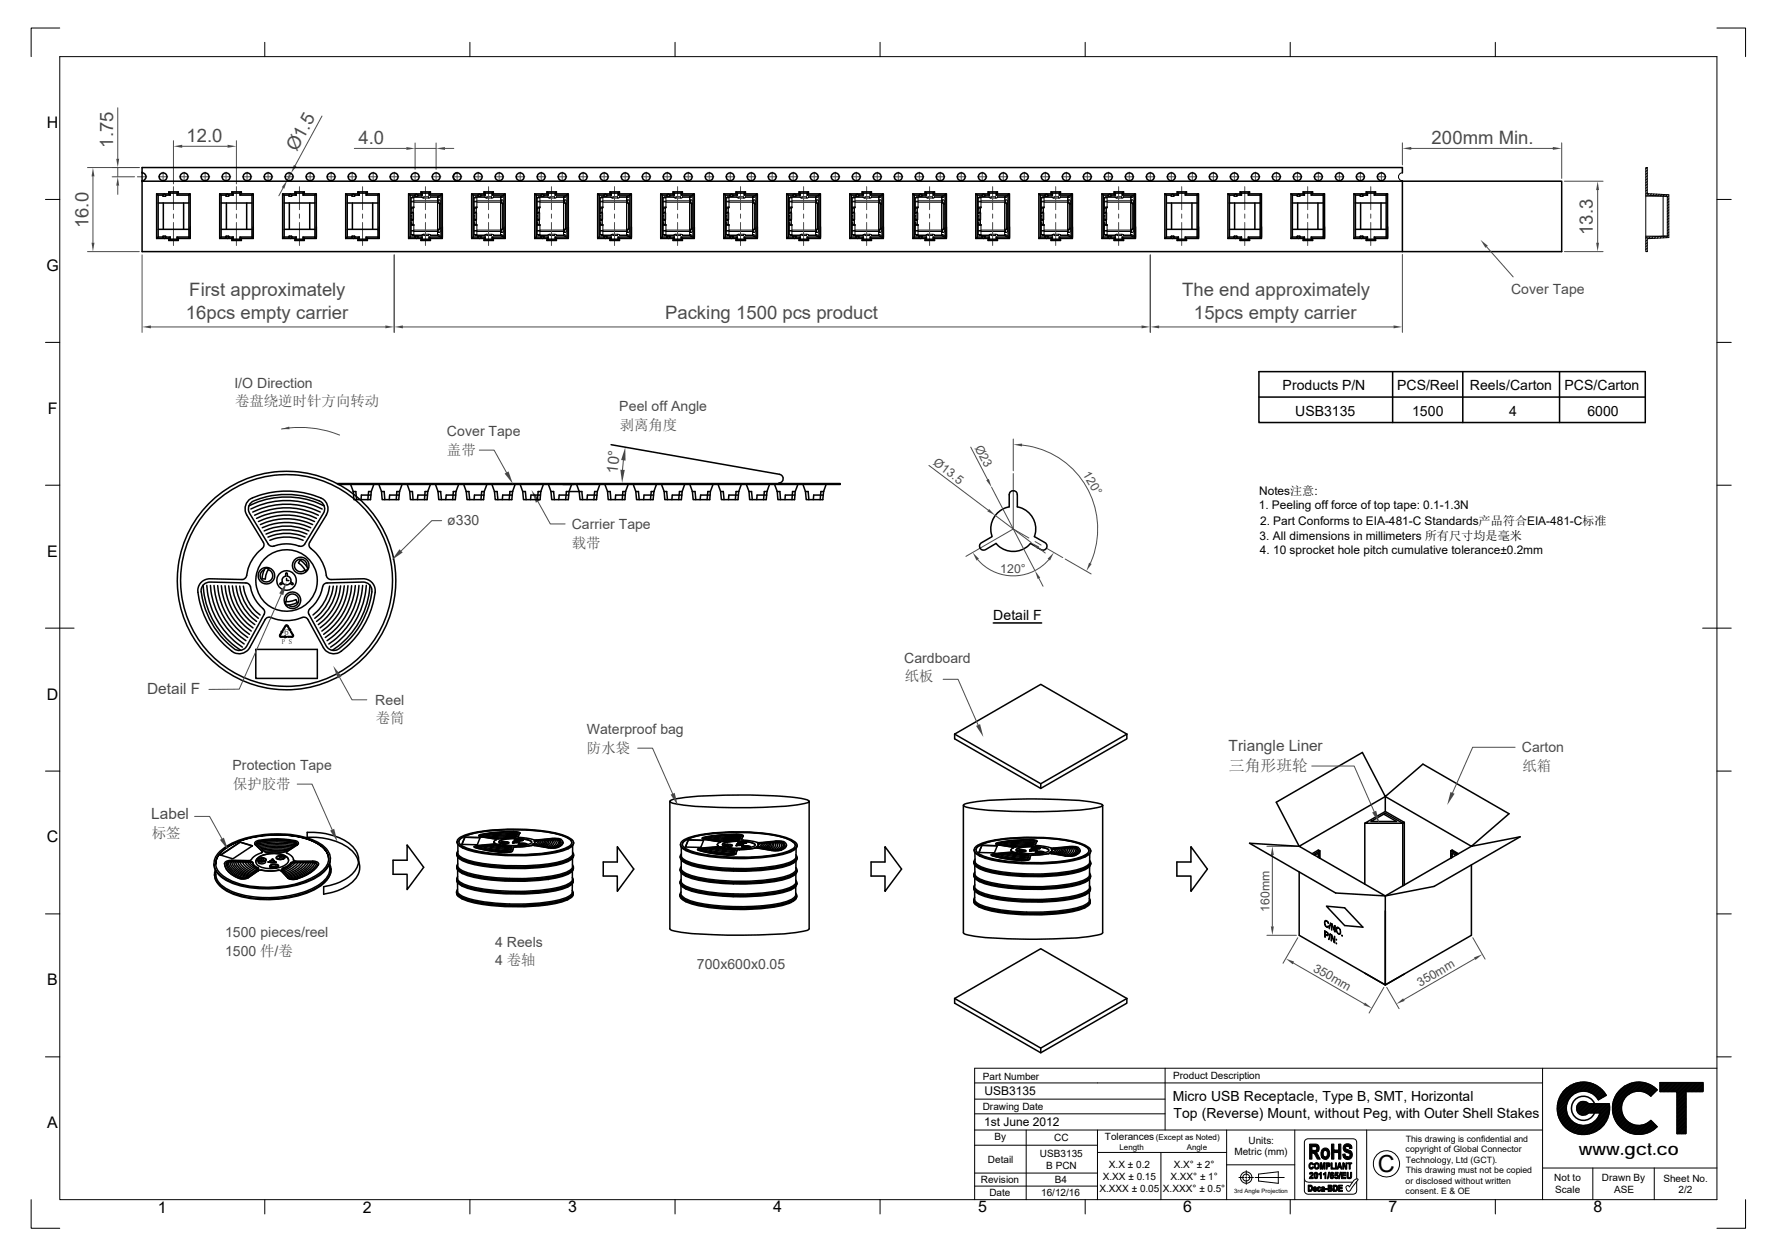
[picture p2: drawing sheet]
<svg xmlns="http://www.w3.org/2000/svg" width="297mm" height="210mm" viewBox="0 0 297 210" stroke-linecap="round" stroke-linejoin="round" font-family="sans-serif">
<defs><g id="words">
<text font-size="3.9" x="230.3" y="196">C</text>
<g font-size="3.1" fill="#4b4b4b">
<text x="31.2" y="23.7">12.0</text>
<text x="18.9" y="24.7" transform="rotate(-90 18.9 24.7)">1.75</text>
<text x="49.6" y="25.4" transform="rotate(-62 49.6 25.4)">Ø1.5</text>
<text x="59.9" y="24.1">4.0</text>
<text x="239.3" y="24">200mm Min.</text>
<text x="14.8" y="38.1" transform="rotate(-90 14.8 38.1)">16.0</text>
<text x="266.3" y="39.3" transform="rotate(-90 266.3 39.3)">13.3</text>
<text x="31.1" y="53.3">16pcs empty carrier</text>
<text x="31.6" y="49.6">First approximately</text>
<text x="111.2" y="53.3">Packing 1500 pcs product</text>
<text x="197.6" y="49.6">The end approximately</text>
<text x="199.6" y="53.3">15pcs empty carrier</text>
</g>
<text font-size="2.9" x="263.9" y="193.1">www.gct.co</text>
<g font-size="2.7">
<text x="7.8" y="21.4">H</text>
<text x="7.7" y="45.3">G</text>
<text x="8" y="69.2">F</text>
<text x="7.9" y="93.1">E</text>
<text x="7.8" y="117">D</text>
<text x="7.8" y="140.9">C</text>
<text x="7.9" y="164.7">B</text>
<text x="7.9" y="188.6">A</text>
<text x="26.4" y="202.7">1</text>
<text x="60.7" y="202.7">2</text>
<text x="95" y="202.7">3</text>
<text x="129.2" y="202.7">4</text>
<text x="163.5" y="202.7">5</text>
<text x="197.8" y="202.7">6</text>
<text x="232.1" y="202.7">7</text>
<text x="266.4" y="202.7">8</text>
</g>
<g font-size="2.6" fill="#4b4b4b">
<text x="103.2" y="79.2" transform="rotate(-84 103.2 79.2)">10°</text>
<text x="24.6" y="116">Detail F</text>
<text x="205.4" y="125.5">Triangle Liner</text>
<text x="205.4" y="128.8">三角形班轮</text>
<text x="25.3" y="137">Label</text>
</g>
<g font-size="2.4" fill="#4b4b4b">
<text x="39.3" y="68">卷盘绕逆时针方向转动</text>
<text x="103.6" y="71.8">剥离角度</text>
<text x="74.7" y="76">盖带</text>
<text x="95.6" y="91.6">载带</text>
<text x="151.3" y="113.9">纸板</text>
<text x="62.8" y="121">卷筒</text>
<text x="98.1" y="125.9">防水袋</text>
<text x="38.9" y="131.8">保护胶带</text>
<text x="254.5" y="128.9">纸箱</text>
<text x="25.4" y="140.1">标签</text>
</g>
<g font-size="2.3" fill="#4b4b4b">
<text x="252.6" y="49.1">Cover Tape</text>
<text x="39.2" y="64.8">I/O Direction</text>
<text x="103.5" y="68.7">Peel off Angle</text>
<text x="74.7" y="72.9">Cover Tape</text>
<text x="74.8" y="87.8">ø330</text>
<text x="95.6" y="88.5">Carrier Tape</text>
<text x="151.1" y="110.8">Cardboard</text>
<text x="62.7" y="117.8">Reel</text>
<text x="98.1" y="122.8">Waterproof bag</text>
<text x="254.4" y="125.8">Carton</text>
<text x="38.9" y="128.7">Protection Tape</text>
<text x="37.6" y="156.7">1500 pieces/reel</text>
<text x="37.6" y="159.8">1500 件/卷</text>
<text x="82.8" y="158.2">4 Reels</text>
<text x="82.8" y="161.4">4 卷轴</text>
<text x="116.5" y="161.9">700x600x0.05</text>
</g>
<g font-size="2.3">
<text x="214.4" y="65.2">Products P/N</text>
<text x="233.5" y="65.2">PCS/Reel</text>
<text x="245.7" y="65.2">Reels/Carton</text>
<text x="261.5" y="65.2">PCS/Carton</text>
<text x="216.5" y="69.5">USB3135</text>
<text x="236.1" y="69.5">1500</text>
<text x="252.2" y="69.5">4</text>
<text x="265.3" y="69.5">6000</text>
<text x="166" y="103.6">Detail F</text>
<text x="196" y="184.1">Micro USB Receptacle, Type B, SMT, Horizontal</text>
<text x="196.2" y="186.9">Top (Reverse) Mount, without Peg, with Outer Shell Stakes</text>
</g>
<g font-size="2.1" fill="#4b4b4b">
<text x="155.9" y="77.6" transform="rotate(37 155.9 77.6)">Ø13.5</text>
<text x="162.9" y="74.8" transform="rotate(63 162.9 74.8)">Ø23</text>
<text x="180.9" y="79.3" transform="rotate(60 180.9 79.3)">120°</text>
<text x="167.2" y="95.8">120°</text>
<text x="212.2" y="152.4" transform="rotate(-90 212.2 152.4)">160mm</text>
<text x="219.4" y="162.3" transform="rotate(30 219.4 162.3)">350mm</text>
<text x="237.4" y="165" transform="rotate(-30 237.4 165)">350mm</text>
</g>
<g font-size="2">
<text x="210.5" y="82.7">Notes注意:</text>
<text x="210.4" y="85.1">1. Peeling off force of top tape: 0.1-1.3N</text>
<text x="210.6" y="87.7">2. Part Conforms to EIA-481-C Standards产品符合EIA-481-C标准</text>
<text x="210.5" y="90.3">3. All dimensions in millimeters 所有尺寸均是毫米</text>
<text x="210.6" y="92.7">4. 10 sprocket hole pitch cumulative tolerance±0.2mm</text>
<text x="164.6" y="183.1">USB3135</text>
<text x="164.5" y="188.3">1st June 2012</text>
</g>
<g font-size="1.7">
<text x="164.3" y="180.5">Part Number</text>
<text x="164.3" y="185.5">Drawing Date</text>
<text x="196.1" y="180.4">Product Description</text>
<text x="166.2" y="190.6">By</text>
<text x="176.2" y="190.8">CC</text>
<text x="184.7" y="190.6">Tolerances</text>
<text x="208.7" y="191.2">Units:</text>
<text x="164" y="197.7">Revision</text>
<text x="165.1" y="194.4">Detail</text>
<text x="173.8" y="193.4">USB3135</text>
<text x="174.9" y="195.4">B PCN</text>
<text x="176.3" y="197.8">B4</text>
<text x="184.3" y="197.2">X.XX ± 0.15</text>
<text x="185.4" y="195.2">X.X ± 0.2</text>
<text x="195.6" y="197.2">X.XX° ± 1°</text>
<text x="196.2" y="195.2">X.X° ± 2°</text>
<text x="206.3" y="193.2">Metric (mm)</text>
<text x="259.8" y="197.5">Not to</text>
<text x="267.8" y="197.5">Drawn By</text>
<text x="278" y="197.5">Sheet No.</text>
<text x="165.4" y="199.9">Date</text>
<text x="174" y="199.9">16/12/16</text>
<text x="183.8" y="199.2">X.XXX ± 0.05</text>
<text x="194.4" y="199.2">X.XXX° ± 0.5°</text>
<text x="260" y="199.4">Scale</text>
<text x="269.8" y="199.4">ASE</text>
<text x="280.6" y="199.5">2/2</text>
</g>
<g font-size="1.5">
<text x="235" y="190.9">This drawing is confidential and</text>
<text x="234.9" y="192.6">copyright of Global Connector</text>
<text x="234.9" y="197.9">or disclosed without written</text>
<text x="235" y="194.4">Technology, Ltd (GCT).</text>
<text x="235" y="196.2">This drawing must not be copied</text>
<text x="234.9" y="199.7">consent. E &amp; OE</text>
</g>
<text font-size="1.4" x="47.5" y="106.2">6</text>
<g font-size="1.3">
<text x="193.2" y="190.6">(Except as Noted)</text>
<text x="187.1" y="192.2">Length</text>
<text x="198.4" y="192.2">Angle</text>
</g>
<text font-size="1.1" x="47.1" y="107.6">P S</text>
<text font-size="1" x="206.3" y="199.4">3rd Angle Projection</text>
</g></defs>
<g fill="none" stroke="#000" stroke-width=".25">
<path d="M210.4 62.1h64.6v8.5h-64.6zM210.4 66.4h64.6M232.8 62.1v8.5M244.5 62.1v8.5M260.7 62.1v8.5M33.9 97.8l.7-.4 .5-.1 6 .2a.83 .83 0 0 1 .8 .6 6.4 6.4 0 0 0 2.2 3.8l.1 .3v.5l-2.9 5.3a1.44 1.44 0 0 1-2.2 .4 14.2 14.2 0 0 1-5.5-9.8zM34 97.8a13.9 13.9 0 0 0 6.2 10.9M34.6 97.9a13.4 13.4 0 0 0 5.9 10.3M35.2 97.9a12.8 12.8 0 0 0 5.6 9.8M35.8 97.9a12.2 12.2 0 0 0 5.3 9.2M36.4 97.9a11.6 11.6 0 0 0 5 8.7M37 97.9a11 11 0 0 0 4.7 8.2"/>
<path d="M37.6 97.9a10.4 10.4 0 0 0 4.4 7.6M38.2 97.9a9.7 9.7 0 0 0 4.1 7.1M38.8 97.9a9 9 0 0 0 3.8 6.5M39.5 98a8.5 8.5 0 0 0 3.4 5.9M40.1 98a7.9 7.9 0 0 0 3.1 5.4M40.7 98a7.2 7.2 0 0 0 2.8 4.8M41.5 83.7a12.4 12.4 0 0 1 6.4-1.6 12.5 12.5 0 0 1 6.4 1.6 2.06 2.06 0 0 1 .2 2.4l-2.7 4.6a.77 .77 0 0 0 .2 1 7 7 0 0 1 2.6 4.7 .81 .81 0 0 0 .8 .5l5.3-.1a2.01 2.01 0 0 1 2 2.2 14.8 14.8 0 0 1-6 10.1 2 2 0 0 1-2.6-.8l-2.6-4.7a.75 .75 0 0 0-1-.4 7 7 0 0 1-5.4 0 .76 .76 0 0 0-.8 .4l-2.6 4.7a2.01 2.01 0 0 1-2.9 .6 14.8 14.8 0 0 1-5.7-10.3 1.99 1.99 0 0 1 2-1.8l5.3 .1 .5-.1a1.45 1.45 0 0 0 .5-1.4 7.2 7.2 0 0 1 2.6-3.9 .77 .77 0 0 0 0-.8l-2.7-4.6a2.02 2.02 0 0 1 .2-2.4zM41.6 84.6a14.1 14.1 0 0 1 12.6 0M41.9 85.1a13.3 13.3 0 0 1 11.9 0M42 84a13.9 13.9 0 0 1 11.7-.1 1.42 1.42 0 0 1 .4 1.9l-3.2 5.2a.79 .79 0 0 1-.9 .3 6.4 6.4 0 0 0-4.5 0h-.2l-.4-.3-3.2-5.2a1.45 1.45 0 0 1 .3-1.8zM42.2 85.6a12.8 12.8 0 0 1 11.3 0M42.6 86.1a12.1 12.1 0 0 1 10.6 0"/>
<path d="M42.9 86.7a11.5 11.5 0 0 1 10 0M43.2 87.2a10.7 10.7 0 0 1 9.4 0M43.5 87.7a10.3 10.3 0 0 1 8.8 0M43.8 88.2a9.8 9.8 0 0 1 8.1 0M44.2 88.8a9 9 0 0 1 7.4 0M44.3 95h.6l-.5 1.2-.1 .6h-.5l.2-1.2zM44.5 89.3a8.5 8.5 0 0 1 6.8 0M44.8 89.8a7.9 7.9 0 0 1 6.2 0M44.8 95.2a1.05 1.05 0 0 1 .6 1.6 1.05 1.05 0 0 1-1.7 .1 1.05 1.05 0 0 1 .5-1.6M45.1 90.3a7.4 7.4 0 0 1 5.6 0M47.8 95.8h.2v.5l.5 .4 .1 .6 .4 .3-.1 .2-.4-.3-.2 .2a.72 .72 0 0 1-1-.2l-.3 .2h-.2v-.2l.4-.2a.72 .72 0 0 1 .6-1zM47.9 96.7v.4h.4"/>
<path d="M50.2 93.6l.5 .4 .8 1-.4 .5-.3-.5-.9-.9zM51.3 94.7a1.06 1.06 0 0 0-1.2-1.2 1.06 1.06 0 0 0-.8 1.5 1.06 1.06 0 0 0 1.7 .3M54.2 97.6l.5-.1 6-.2a1.45 1.45 0 0 1 1.5 1.6 14.2 14.2 0 0 1-5.8 9.7 1.47 1.47 0 0 1-1.9-.6l-2.9-5.3a.77 .77 0 0 1 .2-.9 6.6 6.6 0 0 0 2.2-4zM55.1 98a7.3 7.3 0 0 1-2.8 4.8M55.7 98a7.9 7.9 0 0 1-3.1 5.4M56.3 80.8h84.2M56.3 98a8.4 8.4 0 0 1-3.4 5.9M56.5 81h39.4M56.9 97.9a9 9 0 0 1-3.7 6.5M57.6 97.9a9.7 9.7 0 0 1-4.1 7.1M58.2 97.9a10.2 10.2 0 0 1-4.4 7.6M58.8 97.9a10.9 10.9 0 0 1-4.7 8.2"/>
<path d="M59.4 97.9a11.5 11.5 0 0 1-5 8.7M60 97.9a12.1 12.1 0 0 1-5.3 9.2M60.6 97.9a12.8 12.8 0 0 1-5.6 9.8M61.2 97.9a13.5 13.5 0 0 1-5.9 10.3M61.8 97.8a14 14 0 0 1-6.2 10.9M42.8 108.6h10.2v4.8h-10.2zM47 105.6l.3-.2-.1 .3-.3 .5v.2h.7v-.1l.3 .2-.3 .1v-.1h-.6a.23 .23 0 0 1-.2-.1 .23 .23 0 0 1 0-.2l.3-.6zM47.6 100.6h.7l1.2-.3 .2 .4-1.2 .4-.6 .1zM47.7 104.6a.24 .24 0 0 1 .4 0l.4 .6h.1v.3l-.3-.2h.1l-.5-.7-.1 .1-.4 .6-.1-.1zM47.9 100.6a1.05 1.05 0 0 1 1-1.3 1.05 1.05 0 0 1 1 1.4 1.05 1.05 0 0 1-1.7 .4M48.6 105.7l.1-.1 .3 .6a.23 .23 0 0 1 0 .2 .23 .23 0 0 1-.2 .1h-.7v-.1h.7l.2-.1z"/>
<circle cx="44.5" cy="96.2" r="1.38"/>
<circle cx="47.9" cy="97.1" r="5.2"/>
<circle cx="47.9" cy="97" r="1.63"/>
<circle cx="47.9" cy="97" r="18.3"/>
<circle cx="47.9" cy="97" r="17.7"/>
<circle cx="50.3" cy="94.5" r="1.38"/>
<circle cx="48.9" cy="100.4" r="1.39"/>
</g>
<path d="M47.9 97.3l-.6 2.2-.6-.3z" fill="#4b4b4b"/>
<path d="M47 99.3l-7 15.9-5.1 .1" fill="none" stroke="#4b4b4b" stroke-width=".17"/>
<path d="M66.8 91.8l.5 .6-1.8 1.2z" fill="#4b4b4b"/>
<path d="M169.4 79.2v9.2l-7.9 4.6M73.8 87h-1.6l-5.1 5.1M169.4 88.4l2.6 1.5M173 90.5l1 .6M175 91.7l2.7 1.5" fill="none" stroke="#4b4b4b" stroke-width=".17"/>
<path d="M168.9 82.2a.69 .69 0 0 1 .7-.1 .69 .69 0 0 1 .5 .6v2a3.8 3.8 0 0 1 2.8 5l1.8 1a.67 .67 0 0 1 .2 .9 .67 .67 0 0 1-.9 .3l-1.7-1a3.8 3.8 0 0 1-5.8 0l-1.8 1-.4 .1a.67 .67 0 0 1-.5-.6 .67 .67 0 0 1 .3-.7l1.7-1a3.8 3.8 0 0 1 2.9-5v-2z" fill="none" stroke="#000" stroke-width=".25"/>
<path d="M84.3 79.2l.7-.4 .7 2.1z" fill="#4b4b4b"/>
<path d="M47.1 71.7a17.9 17.9 0 0 1 9.7 1M80.1 75.3h2.5l2.1 3.7" fill="none" stroke="#4b4b4b" stroke-width=".17"/>
<path d="M47.1 71.7l1.2-.4 .1 .5z" fill="#4b4b4b"/>
<g fill="none" stroke="#000" stroke-width=".25">
<path d="M77.7 140h2.6l-.5 1.2h-2.6zM77.7 140h.1M80 139.7h.1M80 139.7l.5 .2M80.3 139.6h.1a22.9 22.9 0 0 1 5.9-.5l.3 .2-.4 .7-2.4 .3-3.3-.5zM80.5 139.9l2.3 .4M80.5 139.9h.1M80.5 139.7h-.1M80.5 139.6v.1M85.8 139.2l.8 .1M85.8 139.2l-2.9 .1-2.4 .4M85.8 139.1v.1"/>
<path d="M86.3 139.9l-4.1 .2M86.4 139.7l-2.7 .1-2 .2M86.4 139.5l-2.4 .1-2.8 .3M86.5 139.4a24.9 24.9 0 0 0-5.8 .4M86.6 139.9l2.7 .5 3-.2a1.58 1.58 0 0 1 1.8 .6 1.06 1.06 0 0 1-.9 .9M86.6 139.9h.1M86.9 139.3l-.3-.2a22.8 22.8 0 0 0-6.4 .5l-.2 .1 .5 .2M86.9 139.3l-.3 .6M86.9 139.2v.1M86.9 139.3h.1M112 134v21.3l.1 .1a33.2 33.2 0 0 0 8.6 .9h4.6a49.1 49.1 0 0 0 9.6-.8l.4-.2v-21.3a5.1 5.1 0 0 0-2.9-.7 100.5 100.5 0 0 0-18.9 .2l-1.3 .3-.2 .1 .2 .3a43.8 43.8 0 0 0 10.4 .8h3.6a34.8 34.8 0 0 0 9-.9l.1-.1M123.1 139.5v.2"/>
<path d="M123.1 139.5l-2.8 .1-2.4 .4M123.1 139.5l.8 .2-.4 .8-2.6 .2-3.2-.5 .2-.2M123.8 140l-3.1 .1-2.2 .3M123.9 139.9a24.8 24.8 0 0 0-5.8 .4M123.9 139.8a18.5 18.5 0 0 0-6.1 .4M124.2 139.7l-.3 .6M124.2 139.7l-.3-.2h-.8a17.6 17.6 0 0 0-5.7 .6l.5 .2M124.2 139.7h.1M159.6 122.7v.8l14.4 8.3v-.8M159.6 122.7l14.4 8.3 14.4-8.3M159.6 122.7l14.4-8.3 14.4 8.3M161 134.6v21.3l.1 .2a32.5 32.5 0 0 0 8.7 .9h4.6a37.1 37.1 0 0 0 9.8-.9l.1-.2v-21.3l-.1 .2a37.6 37.6 0 0 1-9.8 .9h-3.7a40.6 40.6 0 0 1-9.5-.9l-.1-.2a15.1 15.1 0 0 1 5.5-.9l5-.1h3.8a33.7 33.7 0 0 1 8.8 .9l.1 .1"/>
<path d="M188.4 122.7v.8l-14.4 8.3M36 145.4l-.1 .9M36.4 142.7a12.2 12.2 0 0 1 8-3.2 15.3 15.3 0 0 1 9.3 1.7 2.63 2.63 0 0 1 .3 4.6 13.6 13.6 0 0 1-7.9 2.6 15.8 15.8 0 0 1-8.4-1.4 3 3 0 0 1-1.9-3.1zM36.9 142.9l3.2-2.1 2.1 .6-3.3 2.2zM37.5 144.4a2.64 2.64 0 0 0 1.7 2.1l.7 .3M37.8 144.3v.1M37.8 144.4a3.2 3.2 0 0 0 3.1 2.4l.4-.2 1.9-1.3M37.9 144.3a3.8 3.8 0 0 0 2.8 2.5M38.2 144.2a3.3 3.3 0 0 0 2.5 2.3l.4 .2M38.4 144.1a3.3 3.3 0 0 0 2.6 2.3l.3 .2M38.7 144h3.2M38.7 144h-.2a.67 .67 0 0 0-.7 .4"/>
<path d="M38.7 144v.1l3.2 .1M38.7 144.1l-.6 .1-.3 .2M38.7 144.1a3.7 3.7 0 0 0 2.8 2.4M39.1 144.1a3.6 3.6 0 0 0 2.6 2.2M39.4 144.1a3.6 3.6 0 0 0 2.5 2.1M39.7 144.1a3.6 3.6 0 0 0 2.4 2M39.9 146.8h.1M40.1 144.1l.7 .9 1.5 .9M40.1 140.8h.1M40.5 144.1a3.6 3.6 0 0 0 2 1.7M40.9 144.1a3.7 3.7 0 0 0 1.9 1.5M41.3 144.1a3.7 3.7 0 0 0 1.7 1.3"/>
<path d="M41.5 146.7l-.7 .3-.9-.2M41.7 144.2l.6 .6 .9 .5M41.9 144.2l.3 .1M41.9 144l.3 .2M41.9 144v.2M42.2 141.4l-2.1-.6-3.2 2.2M42.2 144.2a1.34 1.34 0 0 0 .9 .9M42.2 144.2v.1M42.2 144.3a1.23 1.23 0 0 0 .9 .9M42.6 141l.1 .2M42.7 141.2l1.2 1.2M42.7 141.2l1.2 1.1"/>
<path d="M42.7 141.2a.46 .46 0 0 1 0-.5 .46 .46 0 0 1 .5-.2 13.7 13.7 0 0 1 6.5 .2l.2 .3-.2 .3M42.7 141.2h.1M42.9 140.9l.2-.2a13.3 13.3 0 0 1 6.4 .1l.1 .2-.2 .2-1.9 1.3h-.5l-1.1-.1-1.6 .1-1.4-1.4zM42.9 143.6a4.7 4.7 0 0 1 4.9-.4 .72 .72 0 0 1 .4 1 3.6 3.6 0 0 1-3.4 1 1.98 1.98 0 0 1-2-1.1zM43.1 143.9l.2 .1M43.1 143.8v.1M43.1 143.6a1 1 0 0 1 1.4 .1 .94 .94 0 0 1-1.5 .1zM43.1 145.1l.1 .1v.1M43.1 145.1v.1M43.1 145.2l.1 .1M43.2 145.5l-1.7 1.2M43.2 145.5v.1"/>
<path d="M43.2 144l.7-.1a.28 .28 0 0 1 .4 0 .28 .28 0 0 1-.1 .4 .89 .89 0 0 1-1-.1zM43.3 140.8a17.8 17.8 0 0 1 6.2 0M43.3 143.9l-.1 .1M43.3 143.9v.1M43.3 143.9h.3v.2M43.4 140.7l-.5 .3M43.4 140.7a14 14 0 0 1 6.1 .3h.1a19.8 19.8 0 0 0-6.7 .1M43.4 140.6v.1M43.7 143.5l-.5 .2-.1 .1M43.7 145.5h.1M43.7 145.5h-.5M43.7 145.5l1.7 .1 1.1-.1"/>
<path d="M43.7 145.5l1.1 .1 1.7-.1M43.7 145.5l-.5 .1M43.9 142.4h.1M43.9 142.3l-.1 .2a3.8 3.8 0 0 0-1.9 1.3h-3.2a1.18 1.18 0 0 0-1.2 .6 3.4 3.4 0 0 0 3.3 2.5l.7-.2M43.9 142.3v.1M44 143.5a.28 .28 0 0 1 .4 .1 .28 .28 0 0 1-.1 .3l-1 .1M44 143.5a.51 .51 0 0 0-.7 .4M44 143.5l-.4 .4M44 143.5v.4l-.2 .2M44.9 144.1h1.2M44.9 144.1v.1M45.1 144l-.2 .1"/>
<path d="M45.1 144.1l.2-.2h.5a.3 .3 0 0 1-.1 .4 .3 .3 0 0 1-.4 0zM45.1 144v.1M45.1 144.8a.84 .84 0 0 1 1.4 0 .92 .92 0 0 1-1.4 0zM45.1 144.9h.1M45.2 144.7a1 1 0 0 1 1.4 0 .93 .93 0 0 1-1.5 .1zM45.2 144.9l.1 .1M45.2 144.9l.9-.1 .1 .1M45.2 144.9h.1M45.3 145h.1M45.5 143.8l-.3 .1-.1 .1M45.5 143.9l-.4 .2M45.5 143.8v.1"/>
<path d="M45.5 143.6h.1v.2M45.5 143.7l.2 .1zM45.5 143.6v.2M45.5 143.6v.3M45.6 143.8l.2 .1v.1M45.6 143.8v.1M45.8 144l.3 .1M45.8 144l.1 .1M46.1 144.1v.1M46.2 143.3a.87 .87 0 0 1 1.4 .1l-.1 .1a1 1 0 0 1-1.3-.1zM46.2 144.9l.2 .1M46.2 144.9l-.9 .1"/>
<path d="M46.2 143.4a.84 .84 0 0 1 1.4 0 1 1 0 0 1-1.4 0zM46.2 144.9v.2M46.5 145.5h.1M46.5 145.5l.5 .1M46.7 143.2l.6 .4M46.7 143.5l-.3 .1M46.7 143.2a.62 .62 0 0 1 .8 .3l-.2 .1M46.7 143.2l.1 .4 .1 .1M47 145.6l1.1 1.2M47 145.6h.1M47.1 145.4l1.3 1.3M47.3 143.6h.1"/>
<path d="M47.3 145.3l-.2 .1M47.3 145.1l-.2 .3M47.3 145.1v.2M47.5 142.4l-3 .1M47.5 143.5h.1M47.8 142.2h-1.8l-1.8 .1M47.9 142.4l-.1 .1a2.09 2.09 0 0 1 1.3 1.3M47.9 142.4l-.1 .1M47.9 142.4h.1M48.1 146.8h.1M48.1 142a17.3 17.3 0 0 0-4.2 .1M48.1 146.8a1.71 1.71 0 0 0 1.5 .1"/>
<path d="M48.2 143.8a1.87 1.87 0 0 0-1.9-1.1 4.7 4.7 0 0 0-3.1 .7l-.4 .5v.2M48.4 141.8a17.5 17.5 0 0 0-4.7 .1M48.6 144.4a2.17 2.17 0 0 1-1.3 .9M48.6 144.2v.2M48.6 144.2l-.5 .5-.8 .4M48.7 141.6a19.1 19.1 0 0 0-5.2 .1M49 144.2l-.5 .5-1.3 .8M49 141.4a18.7 18.7 0 0 0-5.7 .1M49.1 144.1h3.2M49.1 144.2l-.5 .2M49.1 143.8l.3 .2h2.9a.69 .69 0 0 1 .9 .5 6.2 6.2 0 0 1-4.4 2.5l-.7-.2M49.1 144.1l-.5 .1"/>
<path d="M49.1 144.1v.1M49.1 143.7v.1M49.2 140.7v.1M49.3 141.2a17.8 17.8 0 0 0-6.2 .1M49.4 144.2l-.5 .5-1.5 .9M49.6 146.9h.1M49.7 141.3l-1.8 1.1M49.7 141.3h.1M49.8 144.2a5.7 5.7 0 0 1-2.2 1.6M49.9 141l-.2 .3M49.9 140.9v.1M50.3 144.2a6 6 0 0 1-2.5 1.8"/>
<path d="M50.8 144.2a5.7 5.7 0 0 1-2.9 2M51.2 144.2a5.8 5.8 0 0 1-3.1 2.2M51.6 144.2a6 6 0 0 1-3.4 2.3M52 144.2a6.2 6.2 0 0 1-3.6 2.5M52.3 144.2l.6 .3M52.3 144.1l.6 .1v.2a5.8 5.8 0 0 1-4.2 2.5l-.3-.2M52.3 144.1v.1h-3.2M52.4 144.2a6.4 6.4 0 0 1-3.8 2.6M52.7 144.3a6.4 6.4 0 0 1-3.8 2.6M53.2 144.5v.1M53.2 144.6a6.2 6.2 0 0 1-3.6 2.3M53.2 144.4v.2"/>
<path d="M54.9 143.4a2.9 2.9 0 0 0-1.6-2.2 15.6 15.6 0 0 0-10.6-1.3 10.8 10.8 0 0 0-5.8 2.7 2.28 2.28 0 0 0 .1 3.6 10.5 10.5 0 0 0 6.5 2.1 15.3 15.3 0 0 0 10-2.4 2.59 2.59 0 0 0 1-3.6 6.5 6.5 0 0 0-4.3-2.4 18.5 18.5 0 0 0-11.7 1.4 3.8 3.8 0 0 0-2.4 3.2M55.1 144.5a3.1 3.1 0 0 1-1.6 3.3 17.4 17.4 0 0 1-11.3 2.1 9 9 0 0 1-5.5-2.2 2.76 2.76 0 0 1-.7-2.2M55.1 144.4a2.74 2.74 0 0 1-1.3 3.4 16.3 16.3 0 0 1-9.4 2.5 12.3 12.3 0 0 1-7.5-2.1 2.93 2.93 0 0 1-1-1.9M55.2 143.4a2.76 2.76 0 0 1-1.2 2.5 14.2 14.2 0 0 1-8.2 2.7 14.3 14.3 0 0 1-8.5-1.8 2.65 2.65 0 0 1-1.5-2.3M55.3 145.2a2.74 2.74 0 0 1-1.2 2.5 14.2 14.2 0 0 1-8.3 2.7 14.2 14.2 0 0 1-8.4-1.8 2.8 2.8 0 0 1-1.5-2.3M60 144a3.4 3.4 0 0 1-1.8 4 9.7 9.7 0 0 1-4.1 1.5v-1.3a7.6 7.6 0 0 0 5.4-2.9 3 3 0 0 0-.7-3.9 10.5 10.5 0 0 0-7.4-2.2v.8a10.7 10.7 0 0 1 7.4 2.2l1 1.3 .1 .7M68.1 141.3l2.7 3.7-2.7 3.7v-2.5h-2.4v-2.4h2.4zM76.3 149.2l.1 .3a6.8 6.8 0 0 0 3.9 1.5 38.8 38.8 0 0 0 12.9-.2l2-.7 .5-.4 .1-.3M76.3 149.1l.1 .5a6.8 6.8 0 0 0 3.9 1.5 38.8 38.8 0 0 0 12.9-.1l2-.7 .5-.5 .1-.4M76.3 146.9l.1 .6a6.6 6.6 0 0 0 3.9 1.5 38.9 38.9 0 0 0 12.9-.2l2-.7 .5-.4 .1-.6M76.3 147.1l.1 .2a6.6 6.6 0 0 0 3.9 1.6 38.8 38.8 0 0 0 12.9-.2l2-.7 .6-.5v-.3M76.4 142.7l.1 .5a6.6 6.6 0 0 0 3.8 1.5 39 39 0 0 0 12.9-.1l2-.7 .6-.5 .1-.6"/>
<path d="M76.4 144.8v.6a6.3 6.3 0 0 0 3.9 1.5 39.1 39.1 0 0 0 12.9-.2l2-.7 .6-.5v-.5M76.4 145v.2a6.7 6.7 0 0 0 3.9 1.5 38.9 38.9 0 0 0 12.9-.1l2-.7 .6-.5v-.3M76.4 142.8l.1 .3a6.5 6.5 0 0 0 3.8 1.5 39.2 39.2 0 0 0 13-.2l1.9-.7 .6-.4 .1-.3M76.4 140.7l.1 .4a6.5 6.5 0 0 0 3.8 1.5 39.1 39.1 0 0 0 13-.1l2-.8 .5-.4 .1-.4M76.5 147.6v1.5a2.3 2.3 0 0 0 1.9 1.1 35.3 35.3 0 0 0 15.3 .2 2.46 2.46 0 0 0 2-1.2v-1.4M76.5 148.7l-.2 .4M76.5 145.5v1.6a6 6 0 0 0 3.9 1.5 36.8 36.8 0 0 0 13.2-.3 2.6 2.6 0 0 0 2.1-1.2v-1.5M76.5 146.6l-.2 .3M76.5 143.3v1.5a2.22 2.22 0 0 0 1.9 1.2 36 36 0 0 0 15.3 .1 2.58 2.58 0 0 0 2-1.1v-1.5M76.5 144.4l-.1 .4M76.5 141.2l.1 1.6a6.1 6.1 0 0 0 3.8 1.5 38.9 38.9 0 0 0 13-.2l1.1-.3 .8-.5 .4-.4v-1.5M76.5 142.3l-.1 .4"/>
<path d="M76.7 140.7l.1-.3a7 7 0 0 1 4.2-1.4 35.1 35.1 0 0 1 13 .7l.9 .4 .6 .5 .1 .3M76.7 140.1a10.4 10.4 0 0 1 4.6-1.2 35.1 35.1 0 0 1 12.9 .7l1 .5 .6 .5 .1 .3-.1 .2a7.6 7.6 0 0 1-4.3 1.5 37.9 37.9 0 0 1-13-.6l-1.1-.3-.9-.7-.1-.3 .1-.3zM77 140.2a15.6 15.6 0 0 1 6.8-1.5 31.9 31.9 0 0 1 10.3 1l1.3 .7 .2 .6a4.4 4.4 0 0 1-3.1 1.4 35.9 35.9 0 0 1-13.7-.4l-1-.3-1-.7-.1-.3zM77.2 150.3h.1M77.3 148.1v.1M77.3 146h.1M77.3 141.7v.1M79.3 141.5v.1a13.5 13.5 0 0 0 5.8 .9l.5-.2M79.4 141.7l2.1 .5 2.8 .3M79.4 141.7h.1M79.9 141.5l2.1 .5 3.1 .4M80 141.5l-.4 .1"/>
<path d="M80 141.4l-.5 .1a14 14 0 0 0 5.8 .8M80 141.4v.1M80.3 140h-2.6l-.5 1.2M80.4 141.5l2.5 .5 2.4 .3M81 141.5l2.4 .4 2 .2M81.6 141.4l3.9 .5M82.2 141.3l3.3 .5M82.6 140.8l.1 .2M82.6 140.7v.1M82.6 141.3l2.7 .3M82.7 141l-.1 .1-3 .3-.3 .1 .1 .2M82.8 140.3h.2l-.5 .4 .2 .3"/>
<path d="M82.8 140.3h.1M82.8 140.3h.2M83 141.1l-3 .3M83 141.3h.5M83 141.1v.2l-3 .2M83 141.1l.5 .1M83.4 140.8a2.22 2.22 0 0 1 1.9-.6 7.3 7.3 0 0 1 3.5 .5l.1 .1M83.4 140.6a8 8 0 0 1 5.4 0l.1 .3a5.5 5.5 0 0 1-3.5 .5 2.62 2.62 0 0 1-2-.7zM83.5 141.3l1.8 .3M83.5 141.2l1.8 .3M83.5 141.2v.1M83.6 140.9l.6-.2 .9 .2a1.28 1.28 0 0 1-1.5 0z"/>
<path d="M83.7 140.9h.1M83.7 140.9l.2-.1v.2M84.1 141l.3-.1v.1M84.1 141h.1M84.3 140.8l.7 .1-.7 .1-.6-.1M84.3 140.7l.1 .2M84.3 140.7h-.4l.2 .3M84.3 140.7v.2M84.3 142.5h.1M85.3 141.6l.3 .1M85.3 141.5v.1M85.3 141.5h.3l-.3 .8"/>
<path d="M85.6 142.3l-.5 .2h-.8M85.6 142.3h.1M85.7 140.9h.1M85.9 141.7l-.3 .6M85.9 141.7h.1M85.9 140.9h-.2M85.9 140.9h.1M85.9 140.7h-.1h.1M85.9 140.7l-.2 .1 .2 .1M85.9 140.7h.1M85.9 140.7l.1 .1M85.9 140.7l-.1 .2"/>
<path d="M85.9 140.8l.1 .1M86 140.9h-.3M86 140.4l.7-.1a.67 .67 0 0 1 .8 .1l-.2 .1a1.71 1.71 0 0 1-1.3-.1zM86 140.4v.1M86 140.7l.5 .1M86 140.8l.4 .1M86 140.7v.1M86.1 140l-3.3 .2M86.3 141.6l-.4 .1M86.3 141.6h.1M86.4 140.4l.9 .1M86.5 140.8l-.5 .1"/>
<path d="M86.5 140.8h.3M86.5 140.8h.1M86.7 141.1l.7-.1 .7 .1-.7 .2a.6 .6 0 0 1-.7-.2zM86.7 141.2l.9-.2 .5 .2M86.7 141.1v.1M86.8 141.2l.3 .1M86.8 140.8h-.3M86.8 140.8h.1M86.8 141.2h.1M87.1 141.3h.1M87.3 140.4l-.9-.1-.4 .2M87.3 140.5h.1"/>
<path d="M87.4 140.4l-.9-.1-.1 .3M87.4 140.4l-.1 .1M87.4 140.4v.1M87.4 140.5l-.9 .1-.5-.1M87.8 141.1l-.7 .2M87.8 141.1v.2M87.8 141.1l-1 .1M88.1 141.2l-1 .1-.4-.1M88.8 141.3l-2.5 .3M88.8 141.3v.1M88.8 141.4l-2.5 .2M88.8 141.4h.5"/>
<path d="M89.1 141.1v.1M89.3 141.3l2.5 .4h1.4M89.3 141.3h-.5M89.3 141.3v.1M89.4 140.8l-.2 .4M89.5 140.5l-.2 .1 .1 .3-.3 .2M89.5 140.7h-.1M89.5 140.5v.2M90.1 140.6l-.8 .6M90.5 140.6l-.5 .5-.4 .2M90.8 140.5a1.16 1.16 0 0 1-.9 .8M91 140.5a1 1 0 0 1-.8 .9"/>
<path d="M91.2 140.5a1 1 0 0 1-.8 .9M91.4 140.5v.5l-.8 .4M91.7 147v.1M91.7 140.4a.62 .62 0 0 1-.5 .9l-.4 .2M91.9 140.4l.1 .3a1.11 1.11 0 0 1-.9 .8M92.1 140.4l.2 .2a.91 .91 0 0 1-.9 1M92.4 140.4a.51 .51 0 0 1 0 .9l-.6 .4M92.4 140.2l-2.9 .3M92.4 140.4l1.1 .1M92.4 140.2l1.1 .1M92.4 140.2v.2l-2.9 .3M92.6 140.4l.4 .4a1 1 0 0 1-.9 .9"/>
<path d="M93 140.4l.3 .4a1 1 0 0 1-.8 .9M93.2 141.7h.1M93.3 140.4a.49 .49 0 0 1 .1 .9l-.7 .4M93.5 140.5l.3 .4M93.5 140.3l.2 .3a.85 .85 0 0 1-.9 1l-.9 .1-2.7-.5-.1-.1M93.5 140.3v.2M94.1 140.9a1.99 1.99 0 0 1-2.4 .8l-2.4-.3M94.9 150.4h.1M94.9 148.3h.1M95 141.9h.1M95.7 148.9l.1 .2-.2 .5a6.3 6.3 0 0 1-3.4 1.3 36.5 36.5 0 0 1-13.7-.5l-1.6-.6-.5-.5-.1-.2M95.7 146.7l.1 .3a1.24 1.24 0 0 1-1.1 1.1 32.7 32.7 0 0 1-13.1 .8 13.4 13.4 0 0 1-4.7-1.3l-.5-.4-.1-.3"/>
<path d="M95.7 144.6l.1 .3-.1 .5a6.4 6.4 0 0 1-3.5 1.2 37.5 37.5 0 0 1-13.7-.4l-1.6-.7-.5-.4v-.3M95.7 142.5l.2 .2-.2 .5a6.3 6.3 0 0 1-3.4 1.3 36.6 36.6 0 0 1-13.8-.5l-1.6-.6-.4-.5-.1-.2M95.8 149.2v.2M103.2 141.5l2.7 3.8-2.7 3.7v-2.5h-2.4v-2.4h2.4zM113.7 149.5v.6a5.4 5.4 0 0 0 3.1 1.3 37.7 37.7 0 0 0 14.1-.1l1.7-.6 .5-.5 .1-.5M113.7 149.7v.2a5.4 5.4 0 0 0 3.1 1.4 37.6 37.6 0 0 0 14.1-.1l1.7-.7 .5-.4 .1-.3M113.7 147.5l.1 .3a5.1 5.1 0 0 0 3 1.4 37.3 37.3 0 0 0 14.1-.1l1.7-.7 .5-.4 .1-.3M113.7 147.4l.1 .5a5.1 5.1 0 0 0 3 1.4 36.7 36.7 0 0 0 14.1-.1l1.7-.7 .5-.4 .1-.5M113.7 145.3l.1 .5a5 5 0 0 0 3 1.4 37.5 37.5 0 0 0 14.1-.1l1.7-.7 .5-.4 .1-.6M113.7 145.4l.1 .3a6.6 6.6 0 0 0 3.9 1.5 38.9 38.9 0 0 0 12.9-.2l2-.7 .5-.5 .1-.2-.1 .2a5.8 5.8 0 0 1-3.3 1.4 37.6 37.6 0 0 1-14-.4l-1.6-.7-.4-.4zM113.7 143.1l.1 .6a5.3 5.3 0 0 0 3.1 1.3 37.8 37.8 0 0 0 14 0l1.7-.7 .5-.4 .1-.6M113.7 143.3l.1 .2a5.1 5.1 0 0 0 3.1 1.4 37.6 37.6 0 0 0 14.1-.1l1.7-.7 .4-.4 .1-.3"/>
<path d="M113.7 141.1l.1 .4a5.4 5.4 0 0 0 3.1 1.4 37 37 0 0 0 14.1-.1l1.7-.6 .5-.5v-.4M113.8 149.1l-.1 .4M113.8 148v1.5l.4 .5a11 11 0 0 0 4.8 1.3 39.5 39.5 0 0 0 11.7-.4l1.1-.3 .8-.4 .4-.5v-1.5M113.9 147l-.2 .4M113.9 145.9v1.5a2.22 2.22 0 0 0 1.8 1.1 35.9 35.9 0 0 0 15.3 .2 2.63 2.63 0 0 0 2-1.1v-1.5M113.9 143.8v1.5a2.31 2.31 0 0 0 1.9 1.1 35.2 35.2 0 0 0 15.2 .2 2.44 2.44 0 0 0 2-1.2l.1-1.4M113.9 141.7v1.6a4.6 4.6 0 0 0 2.8 1.2 36.2 36.2 0 0 0 14.4 0 2.43 2.43 0 0 0 2-1.2v-1.5M113.9 144.9l-.2 .2 .1 .5a5.6 5.6 0 0 0 3.3 1.3 36.7 36.7 0 0 0 14.3-.3 2.07 2.07 0 0 0 1.8-1.3l-.1-.3M113.9 142.7l-.2 .4M114 141.2l.1-.3a7.2 7.2 0 0 1 4.2-1.5 35 35 0 0 1 13 .7l1 .5 .6 .4v.3M114.1 140.6a10.3 10.3 0 0 1 4.5-1.3 35.2 35.2 0 0 1 13 .8l.9 .4 .7 .5v.3v.3a7.6 7.6 0 0 1-4.3 1.5 37.9 37.9 0 0 1-13.1-.6l-1-.4-1-.7-.1-.3 .1-.2zM114.4 140.6a9.9 9.9 0 0 1 4.4-1.2 32.9 32.9 0 0 1 12.7 .8l.9 .4 .5 .6-.1 .5a8.9 8.9 0 0 1-4.3 1.4 36.1 36.1 0 0 1-12.4-.6l-1-.4-1-.7-.1-.3z"/>
<path d="M114.6 150.7h.1M114.6 148.6h.1M114.6 146.5h.1M114.7 142.2h.1M115.1 140.4h.1M115.1 140.4l2.5 .1-.5 1.2-2.5-.1zM116.6 142h.1M116.6 142l.2 .2M116.8 142.1v.1M116.8 142.2l2.1 .5 2.8 .3M117.3 142l2.1 .5 3 .3M117.4 141.8v.2"/>
<path d="M117.4 142l-.4 .1M117.4 141.8l-.5 .2a15.9 15.9 0 0 0 5.7 .8l.1-.1M117.4 140.1l.1 .2 .4 .1M117.6 140.5l-2.5-.1-.5 1.2M117.8 142l2.5 .5 2.4 .2M117.9 140.3v.1M117.9 140.3l2.3 .4M117.9 140.4l2.3 .3M117.9 140v.2M118.3 141.9l2.5 .4 2 .2M118.9 141.8l3.9 .6M119.5 141.8l3.4 .4"/>
<path d="M119.9 141.2l.2 .3M120 141.8l2.7 .3M120.1 141.4v.1M120.1 141.4l-.2 .1-3 .3-.3 .2a14.3 14.3 0 0 0 6.3 .8l.1-.1M120.1 141.5h.1M120.2 140.7h.1M120.2 140.7l.2 .1M120.2 140.7l.2 .1-.5 .4 .2 .2M120.3 141.6v.1l-2.9 .3M120.3 141.6l-2.9 .2M120.3 141.7l.5 .1M120.3 141.6h.5"/>
<path d="M120.8 141.2a5.1 5.1 0 0 1 3.6-.5 2.43 2.43 0 0 1 1.8 .6M120.8 141.1a8 8 0 0 1 5.1-.2l.3 .4a5.5 5.5 0 0 1-3.4 .5 2.73 2.73 0 0 1-2-.6zM120.8 141.6v.2M120.8 141.8l1.8 .3M120.8 141.6l1.8 .3M121 141.3l.6-.1 .8 .1a1.63 1.63 0 0 1-1.5 0zM121.4 141.4h.3v.1M121.4 141.4v.1M121.6 141.2v.1M121.6 141.2l.8 .2a1.88 1.88 0 0 1-1.4 0l.3-.2v.3M121.6 141.2h-.3l.1 .2M121.6 141.2l.1 .2"/>
<path d="M121.7 142.9v.1M122.6 141.9v.2M122.6 142.1h.3M122.6 141.9l.3 .1-.2 .7M123 142.7v.1M123 142.8l-.6 .1-.7 .1M123 141.4h.1M123.2 141.3l-.2 .1M123.2 141.3v.1M123.2 142.1l-.2 .7M123.3 141.1l.1 .1M123.3 141.1l.1 .2"/>
<path d="M123.3 141.2l-.1 .1M123.3 141.2h-.2l.1 .1M123.3 141.1h-.2l.2 .1M123.3 141.2v.1M123.3 141.3l-.3 .1M123.4 140.8l.7-.1 .7 .2-.7 .1a.65 .65 0 0 1-.7-.2zM123.4 141.2v.1M123.4 141.2l.5 .1M123.4 141.3h.4M123.5 140.5l-3.3 .1M123.6 142.1h-.4M123.6 142v.1"/>
<path d="M123.6 142l-.4 .1M123.7 140.3l-4.1 .2M123.7 140.2h-2.7l-2 .2M123.8 140.8l.9 .1M123.9 141.3h.3M123.9 141.3h.1M123.9 141.3h-.6M123.9 140.3l2.9 .6 3-.3a1.51 1.51 0 0 1 1.7 .6 1.52 1.52 0 0 1-1.7 1h-.8M124 141.5l.7-.1 .7 .1v.1a1.86 1.86 0 0 1-1.4-.1zM124.1 141.5h.8l.5 .1-.7 .1h-.5zM124.2 141.3h.1M124.2 141.7h.1"/>
<path d="M124.2 141.3h-.3M124.2 141.7h.2M124.4 141.7h.1M124.7 140.9v.1M124.7 140.9l-.9-.1-.4 .1 .6 .1 .8-.1M124.7 140.9h.1M124.7 140.9l-.9-.1v.2M125.2 141.6l-1 .1M125.2 141.6v.1M125.2 141.6l-.8 .1M126.2 141.8h.1M126.2 141.8l-2.6 .2"/>
<path d="M126.2 141.8h.5M126.2 141.8l-2.6 .3M126.4 141.5v.1M126.7 141.8h.1M126.7 141.8l2.3 .4M126.7 141.8h-.5M126.8 141.3l-.3 .4M126.9 141v.1M126.9 141.1h-.2M126.9 141h-.3l.1 .3-.3 .2M127.5 141l-.5 .5-.4 .2M127.8 141l-.4 .5-.5 .2"/>
<path d="M128.1 141a1.16 1.16 0 0 1-.8 .8M128.4 141a.99 .99 0 0 1-.9 .8M128.6 140.9a.96 .96 0 0 1-.9 1M128.8 140.9a.93 .93 0 0 1-.8 1M129 142.2h.1M129 140.9a.61 .61 0 0 1-.4 .8l-.4 .3M129.2 140.9l.1 .2a.99 .99 0 0 1-.8 .9M129.5 140.9l.2 .2a.91 .91 0 0 1-.9 .9M129.7 140.8a.51 .51 0 0 1 .1 .9l-.7 .4M129.8 140.7v.1l-2.9 .3M129.8 140.7l-2.9 .3M129.8 140.8l1 .1"/>
<path d="M129.8 140.7l1 .1M130 140.8l.3 .5a1.07 1.07 0 0 1-.8 .8M130.3 140.8l.4 .5a.99 .99 0 0 1-.9 .8M130.6 142.1h.1M130.6 142.1l-.8 .1h-.8M130.6 140.8l.3 .5a1.07 1.07 0 0 1-.9 .8M130.8 140.8v.1M130.8 140.9l.4 .5M130.8 140.8l.4 .4a1.4 1.4 0 0 1-1.6 .9l-3-.4-.2-.2M131.5 141.3a1.16 1.16 0 0 1-.9 .8M132.2 150.9h.1M132.2 148.7h.1"/>
<path d="M132.3 142.3v.1M133 149.3l.2 .3-.2 .5a6.3 6.3 0 0 1-3.4 1.2 36.7 36.7 0 0 1-13.8-.4l-1.6-.7-.5-.4v-.3M133 147.2l.2 .2a1.24 1.24 0 0 1-1.1 1.1 32.9 32.9 0 0 1-13.2 .9l-1-.2a10.3 10.3 0 0 1-3.7-1.1l-.4-.4-.1-.3M133.1 142.9l.1 .3a1.24 1.24 0 0 1-1.1 1.1 32.3 32.3 0 0 1-12.1 .9l-1-.1a13.8 13.8 0 0 1-4.8-1.3l-.4-.4-.1-.3M162.8 150.4v.6a6.6 6.6 0 0 0 3.9 1.5 38.9 38.9 0 0 0 12.9-.2l2-.7 .6-.4v-.6M162.8 148.4l.1 .3a6.4 6.4 0 0 0 3.8 1.5 39.1 39.1 0 0 0 13-.1l2-.8 .5-.4 .1-.3M162.8 150.6v.2a6.6 6.6 0 0 0 3.9 1.5 39.1 39.1 0 0 0 12.9-.1l2-.7 .6-.5v-.3M162.8 146.3l.1 .3a6.6 6.6 0 0 0 3.9 1.5 39 39 0 0 0 12.9-.2l2-.7 .5-.4 .1-.3M162.8 146.2l.1 .5a6.3 6.3 0 0 0 3.8 1.5 39.2 39.2 0 0 0 13-.1l2-.8 .5-.4 .1-.6M162.8 148.3v.1M162.8 144.2l.1 .2a6.6 6.6 0 0 0 3.9 1.6 39 39 0 0 0 12.9-.2l2-.7 .5-.5 .1-.3M162.8 144l.1 .6a6.8 6.8 0 0 0 3.9 1.5 38.8 38.8 0 0 0 12.9-.2l2-.7 .5-.4 .1-.6"/>
<path d="M162.8 142.1l.1 .4a6.7 6.7 0 0 0 3.9 1.5 38.8 38.8 0 0 0 12.9-.2l2-.7 .5-.5 .1-.4M162.9 148.9v1.5a2.32 2.32 0 0 0 1.9 1.2 35.4 35.4 0 0 0 15.3 .2 2.58 2.58 0 0 0 2-1.2v-1.5M162.9 150l-.1 .4M162.9 144.7l.1 1.5a2.25 2.25 0 0 0 1.8 1.1 36.1 36.1 0 0 0 15.3 .2 2.44 2.44 0 0 0 2-1.2v-1.4M162.9 146.8v1.5a2.28 2.28 0 0 0 1.9 1.2 36 36 0 0 0 15.3 .1 2.67 2.67 0 0 0 2-1.1v-1.5M162.9 147.9l-.1 .4M163 142.6v1.6a6.1 6.1 0 0 0 3.9 1.5 36.8 36.8 0 0 0 13.2-.3 2.58 2.58 0 0 0 2-1.2l.1-1.4M163 145.8l-.2 .4M163 143.6l-.2 .4M163.1 142.1l.1-.3a7.2 7.2 0 0 1 4.2-1.4 35 35 0 0 1 13 .7l1 .4 .5 .5 .1 .2M163.2 141.5a10.3 10.3 0 0 1 4.5-1.3 35.1 35.1 0 0 1 13 .8l.9 .4 .6 .5 .1 .3-.1 .3a7.8 7.8 0 0 1-4.3 1.5 37.8 37.8 0 0 1-13-.6l-1-.4-.7-.4a.64 .64 0 0 1 0-1.1zM163.5 141.5a15.5 15.5 0 0 1 6.8-1.4 31.8 31.8 0 0 1 10.2 1l1.3 .7 .2 .6a4.4 4.4 0 0 1-3 1.3 36.3 36.3 0 0 1-13.8-.3l-1-.4-1-.7-.1-.2z"/>
<path d="M163.7 151.6h.1M163.7 149.5h.1M163.7 147.4h.1M163.7 143.1h.1M164.1 141.3h.1M164.1 141.3l2.6 .1-.5 1.2-2.6-.1zM165.7 142.9a14.7 14.7 0 0 0 6.3 .8h.1M165.7 142.9h.1M165.9 143l2.1 .5 2.8 .3M165.9 143v.1M166.3 142.9l2.1 .5 3.1 .3M166.5 142.8v.1"/>
<path d="M166.5 142.9l-.4 .1M166.5 142.8l-.5 .1a16.5 16.5 0 0 0 5.5 .9l.3-.2M166.5 141l.4 .3M166.7 141.4l-2.6-.1-.5 1.2M166.8 141a17.9 17.9 0 0 1 6.2-.4l-.4 .8-2.4 .2-3.1-.4zM166.8 142.9l2.6 .5 2.4 .2M166.9 141.2v.1M166.9 141.2l2.4 .4M166.9 141.3l2.4 .3M167 140.9v.2M167 141.1h-.2M167.4 142.8l2.4 .4 2.1 .2"/>
<path d="M168 142.8l3.9 .5M168.6 142.7l3.4 .4M169 142.1l.2 .3M169.1 142.7l2.7 .3M169.2 142.4h.1M169.2 142.4l-.2 .1-3 .2-.3 .2 .2 .1M169.3 141.6l.2 .1M169.3 141.6h.1M169.3 141.6l.2 .1-.5 .4 .2 .3M169.4 142.5v.1l-2.9 .3M169.4 142.6l.5 .1M169.4 142.5h.5"/>
<path d="M169.4 142.5l-2.9 .3M169.8 142.1a2.25 2.25 0 0 1 1.9-.5 7.3 7.3 0 0 1 3.6 .5v.1M169.9 142a8 8 0 0 1 5.3 0l.1 .2a5.4 5.4 0 0 1-3.5 .5 2.6 2.6 0 0 1-2-.6zM169.9 142.5v.2M169.9 142.7l1.8 .3M169.9 142.5l1.8 .3M170.1 142.2l.8-.1a.33 .33 0 0 1 .6 .2 1.83 1.83 0 0 1-1.5-.1zM170.1 142.3l.3-.2v.3M170.1 142.3h.1M170.5 142.3h.3v.1M170.5 142.3v.1M170.7 142.1v.1"/>
<path d="M170.7 142.1h.3a.28 .28 0 0 1 .4 .2l-.7 .1-.6-.1M170.7 142.1l.1 .2M170.7 142.1h-.3l.1 .2M170.8 143.8v.1M171.7 142.8v.2M171.7 143h.3M171.7 142.8l.3 .1-.2 .7M172.1 143.7l-1.3 .1M172.1 142.3h.1M172.2 140.4v.2M172.2 140.6l-2.8 .1-2.4 .4M172.2 140.6l.8 .1"/>
<path d="M172.3 143l-.2 .7M172.3 142.2l-.2 .1M172.3 142.2v.1M172.3 142.1l-.1 .1h.1M172.3 142.1v.1M172.3 142.1h.1M172.4 142h-.2l.1 .1M172.4 142l.1 .2M172.4 142l.1 .1M172.4 142.1v.1M172.4 142.2l-.3 .1M172.4 141.8l.7-.2 .7 .1v.1a1.96 1.96 0 0 1-1.4 0z"/>
<path d="M172.5 141.8l.4 .1 .9-.1M172.5 142.2h.4M172.5 141.8h.1M172.5 142.1v.1M172.5 142.1l.5 .1M172.5 141.4l-3.3 .1M172.7 142.9l-.4 .1M172.7 142.9h.1M172.7 141.2l-4 .2M172.8 141.1h-2.7l-2 .2M172.9 140.9l-3.1 .1-2.2 .3M172.9 141.7l.9 .1"/>
<path d="M173 140.8a24.8 24.8 0 0 0-5.8 .4M173 142.2h.2M173 142.2h-.6M173 142.2h.1M173.1 142.4l.7-.1 .7 .2a1.59 1.59 0 0 1-1.4 0zM173.1 142.5h.1M173.1 142.5l.9-.1 .5 .1M173.2 142.2h.1h-.1M173.2 142.2h.1M173.3 142.6h.1M173.3 142.6h.2M173.3 140.6v.1"/>
<path d="M173.3 140.6l-.3 .7 2.9 .5 2.8-.3a1.58 1.58 0 0 1 1.9 .6 1.06 1.06 0 0 1-.9 .9M173.3 140.6a1.07 1.07 0 0 0-1.1-.2 19 19 0 0 0-5.7 .6v.1l.4 .1M173.5 142.6h.1M173.8 141.8v.1M173.8 141.8l-.9-.1-.4 .1M173.8 141.8l-.9-.1v.2M174.3 142.5l-1 .1M174.3 142.5v.1M174.3 142.5l-.8 .1M174.5 142.5l-.9 .1-.5-.1M175.2 142.7l-2.5 .2M175.2 142.7h.6"/>
<path d="M175.2 142.7h.1M175.5 142.5h.1M175.8 142.7h.1M175.8 142.7h-.6M175.8 142.7l2.3 .4M175.9 142.2l-.3 .4M176 141.9v.1M176 141.9l-.3 .1 .1 .2-.3 .3M176 142h-.2M176.6 142l-.9 .6M176.9 141.9l-.4 .5-.5 .2M177.2 141.9a1.15 1.15 0 0 1-.9 .8"/>
<path d="M177.5 141.9a1.07 1.07 0 0 1-.9 .8M177.7 141.8a.96 .96 0 0 1-.9 1M177.9 141.8a.93 .93 0 0 1-.9 1M178.1 143.1h.1M178.1 141.8a.62 .62 0 0 1-.4 .8l-.4 .3M178.3 141.8l.1 .2a1.04 1.04 0 0 1-.8 .9M178.6 141.8l.1 .2a.91 .91 0 0 1-.8 .9M178.8 141.7l.2 .3a.61 .61 0 0 1-.4 .8l-.4 .2M178.9 141.6v.1l-2.9 .3M178.9 141.6l-2.9 .3M178.9 141.6l1 .1M178.9 141.7l1 .1"/>
<path d="M179.1 141.7l.3 .5a1.07 1.07 0 0 1-.9 .9M179.4 141.7l.4 .5a1.07 1.07 0 0 1-.9 .9M179.7 143h.1M179.7 143l-1.6 .1M179.7 141.7l.3 .5a1.07 1.07 0 0 1-.9 .8M179.9 141.7v.1M179.9 141.8l.4 .5M179.9 141.7l.2 .2a.84 .84 0 0 1-.8 1.1h-.9l-2.7-.4-.2-.1M180.6 142.2h.1M180.6 142.2a2.03 2.03 0 0 1-2.5 .9M181.3 151.8h.1M181.3 149.6v.1"/>
<path d="M181.4 143.2v.1M182.1 150.2l.1 .3-.1 .5a6.4 6.4 0 0 1-3.5 1.2 36.4 36.4 0 0 1-13.7-.4l-1.6-.7-.5-.4v-.3M182.1 148.1l.2 .2a1.24 1.24 0 0 1-1.1 1.1 32.8 32.8 0 0 1-13.2 .9 13.6 13.6 0 0 1-4.7-1.3l-.4-.4-.1-.3M182.1 143.8l.2 .3-.2 .5a6.3 6.3 0 0 1-3.4 1.2 36.7 36.7 0 0 1-13.8-.4l-1.6-.7-.4-.4-.1-.3M182.1 145.9l.2 .3-.2 .5a6.4 6.4 0 0 1-3.4 1.3 37.6 37.6 0 0 1-13.8-.5l-1.6-.6-.4-.5-.1-.2M182.3 148.4l-.1 .6a6.5 6.5 0 0 1-3.9 1.5 39.1 39.1 0 0 1-12.9-.4l-2-.8-.5-.4-.1-.5M159.6 166.9l14.4-8.3 14.4 8.3-14.4 8.3zM174 175.2v.8M188.4 166.9v.8l-14.4 8.3-14.4-8.3"/>
</g>
<path d="M55.7 111.3l1.4 1.8-.6 .3z" fill="#4b4b4b"/>
<path d="M56.8 113.2l2 3.8h2.5" fill="none" stroke="#4b4b4b" stroke-width=".17"/>
<path d="M88.8 81.9l1.4 1.8-.6 .3z" fill="#4b4b4b"/>
<path d="M89.9 83.8l2.1 3.8h2.5" fill="none" stroke="#4b4b4b" stroke-width=".17"/>
<path d="M36.8 140.4l.6-.4 .8 2.2z" fill="#4b4b4b"/>
<path d="M32.5 136.5h2.5l2.1 3.7" fill="none" stroke="#4b4b4b" stroke-width=".17"/>
<path d="M55.2 138.9l.7-.3 .5 2.1z" fill="#4b4b4b"/>
<path d="M49.7 131.1h2.5l3.3 7.6" fill="none" stroke="#4b4b4b" stroke-width=".17"/>
<path d="M112.1 132.8l.7-.2 .5 2.1z" fill="#4b4b4b"/>
<path d="M106.6 125.1h2.5l3.3 7.6" fill="none" stroke="#4b4b4b" stroke-width=".17"/>
<path d="M147.9 141.5l2.8 3.8-2.8 3.7v-2.5h-2.3v-2.4h2.3z" fill="none" stroke="#000" stroke-width=".25"/>
<path d="M163.2 121.4l.6-.3 .6 2.1z" fill="#4b4b4b"/>
<path d="M157.6 113.6h2.5l3.4 7.6M211.8 156.4h4.9M211.8 141.5h4.9M212.7 143v11.9" fill="none" stroke="#4b4b4b" stroke-width=".17"/>
<path d="M252.2 136l-6.2 5.5 8.1-1.6M199.1 141.5l2.7 3.8-2.7 3.7v-2.5h-2.4v-2.4h2.4zM221.7 151.5l3.1 .3 3 3.2-3-.3zM242.7 142.6v.7v-.7l.7 .4M242.8 142.1l-.3 .1v1.3M243.8 142.7l-1-.6-.3 .1 1.1 .7M246 144.6v11.8M159.6 166.9v.8" fill="none" stroke="#000" stroke-width=".25"/>
<g fill="#000" stroke="#000" stroke-width=".17">
<path d="M221.4 155.6l.6 .4-.5-.2v.4l.5 .2-.5-.1v.4h-.1z" fill-rule="evenodd"/>
<path d="M221.5 153.9h.2l.3 .3-.3-.2-.1 .1a.73 .73 0 0 0 .2 .8l-.3-.1-.1-.3z" fill-rule="evenodd"/>
<path d="M221.7 155.9l.3 .2v.3l-.5-.2 .4 .1v-.3z" fill-rule="evenodd"/>
<path d="M221.5 154.8l.4 .1 .1-.1 .1 .2-.2 .1z" fill-rule="evenodd"/>
<path d="M221.8 154l.2 .2 .1 .2z" fill-rule="evenodd"/>
<path d="M222.3 156.1h.1l-.2 1h-.1z" fill-rule="evenodd"/>
<path d="M222.4 154.3h.1l-.3 1-.1-.1z" fill-rule="evenodd"/>
<path d="M222.5 156.2l.1 .1v1h-.1z" fill-rule="evenodd"/>
<path d="M222.6 156.3l.4 1.1v.2z" fill-rule="evenodd"/>
<path d="M222.5 154.4h.2v1.1h-.2z" fill-rule="evenodd"/>
<path d="M222.7 154.4l.4 1.1v.3l-.4-1.1z" fill-rule="evenodd"/>
<path d="M223 156.5l.1 .1v1.1l-.1-.1z" fill-rule="evenodd"/>
<path d="M223.1 154.7l.1 .1v1h-.1z" fill-rule="evenodd"/>
<path d="M223.3 157.6l.1 .2z" fill-rule="evenodd"/>
<path d="M223.3 157l.1 .2z" fill-rule="evenodd"/>
<path d="M223.4 155.1l.1-.1 .2 .2h-.2v.4l.1 .4 .4 .2h-.3l-.3-.4z" fill-rule="evenodd"/>
<path d="M223.5 155h.2l.3 .4 .1 .4-.1 .4-.3-.2 .2 .1 .1-.2-.1-.6z" fill-rule="evenodd"/>
<path d="M224.3 156.3l.1 .2z" fill-rule="evenodd"/>
</g>
<g fill="#4b4b4b">
<path d="M212.4 154.9h.5l-.2 1.5z"/>
<path d="M212.7 141.5l.2 1.5h-.5z"/>
</g>
<g fill="none" stroke="#000" stroke-width=".25">
<path d="M228.1 137.6v10.2M231.3 136.1l2.1 1.2h-4.2l2.4-1.3 2.9 1.6M231.6 133.2v2.5l3.1 1.8M231.6 135.7l-3.5 1.9h6.4M231.6 133.2l14.4 8.3-14.4 8.3M231.6 133.2l-14.4 8.3 14.4 8.3M234.5 137.6v10.5M234.7 137.5l-.2 .1M234.7 137.5v10.5M252.2 136l-14.4-8.3-6.2 5.5-3.9-7.4-14.4 8.3 3.9 7.4-8.3-.5 14.4 8.3 8.3 .5 8.1-1.6 14.4-8.3M217.2 145.8v10.6l14.4 8.3v-12.4M219.3 142.7l1.1-.6 .2 .1v1.3"/>
<path d="M220.4 142.1l.2 .1-1 .7M220.4 142.6v.7v-.7l-.6 .4M231.6 149.8v14.9l14.4-8.3M228.1 162.7l3.5 2zM231.6 164.7l3.1-1.9z"/>
</g>
<path d="M216.9 156.8l-2.4 4.2M216.2 161l11.8 6.8M231.3 165.1l-2.4 4.3" fill="none" stroke="#4b4b4b" stroke-width=".17"/>
<g fill="#4b4b4b">
<path d="M214.9 160.3l1.4 .5-.2 .4z"/>
<path d="M228.2 167.6l1.1 1-1.4-.6z"/>
</g>
<path d="M246.2 156.8l2 3.5M231.8 165.1l2.1 3.5M246.5 160.3l-11.8 6.8" fill="none" stroke="#4b4b4b" stroke-width=".17"/>
<g fill="#4b4b4b">
<path d="M233.4 167.9l1.1-1 .3 .4z"/>
<path d="M246.4 160.1l1.4-.6-1.2 1z"/>
<path d="M229.4 135.8l.6-.3 .6 2.2z"/>
</g>
<path d="M219.3 128.1h7.1l3.3 7.6" fill="none" stroke="#4b4b4b" stroke-width=".17"/>
<path d="M242.5 132.4l.6 .3-1.2 1.9z" fill="#4b4b4b"/>
<path d="M104.2 76.9l-.1 1.6M253.3 124.9h-7.1l-3.4 7.7" fill="none" stroke="#4b4b4b" stroke-width=".17"/>
<path d="M130.3 79.3a.74 .74 0 0 1 .6 .8 .74 .74 0 0 1-.7 .7" fill="none" stroke="#000" stroke-width=".25"/>
<g fill="#4b4b4b">
<path d="M103.7 78.5l.7 .1-.4 2.2z"/>
<path d="M104.5 74.7l.1 2.3-.8-.1z"/>
</g>
<path d="M102.2 74.3l28.1 5M94.1 81h46.4M137.7 82.2l-.2 1.3M166 104.1h8.1" fill="none" stroke="#000" stroke-width=".25"/>
<path d="M169.4 73.4v5.3M170.9 74.4a14.1 14.1 0 0 1 11.4 19.8M178.1 93.5l4.3 2.5" fill="none" stroke="#4b4b4b" stroke-width=".17"/>
<g fill="#4b4b4b">
<path d="M182.1 94.1l.4 .2-.9 1.2z"/>
<path d="M169.4 74.3l1.5-.1-.1 .4z"/>
</g>
<path d="M163.4 93.6a7.9 7.9 0 0 0 11.9 0" fill="none" stroke="#4b4b4b" stroke-width=".17"/>
<g fill="#4b4b4b">
<path d="M162.6 92.4l1 1-.4 .3z"/>
<path d="M176.2 92.4l-.7 1.3-.4-.3z"/>
</g>
<path d="M155.3 77.8l9.9 7.5M166.4 86.2l6 4.5M173.6 91.6l1.1 .9" fill="none" stroke="#4b4b4b" stroke-width=".17"/>
<g fill="#4b4b4b">
<path d="M172.4 90.7l1.3 .7-.3 .4z"/>
<path d="M165.3 85.1l1.1 1.1-1.4-.7z"/>
</g>
<path d="M162.3 74.7l2.8 5.5M165.8 81.5l7.2 13.9M173.7 96.7l.6 1.3" fill="none" stroke="#4b4b4b" stroke-width=".17"/>
<g fill="#4b4b4b">
<path d="M173 95.4l.9 1.2-.4 .2z"/>
<path d="M164.9 80.3l.4-.2 .5 1.4z"/>
</g>
<g fill="none" stroke="#000" stroke-width=".25">
<path d="M58.6 81l.5 1.2M59.1 82.2h.4l.1 1.3M59.1 82.2l.1 1.3h2.7l.2-1.3M62 82.8h-1.6l-.1 .7M62.1 82.2h-.5l-.1 1.3M62.5 81l-.4 1.2M63.3 81l.5 1.2M63.8 82.2h.4l.1 1.3M63.8 82.2l.1 1.3h2.8l.1-1.3M66.7 82.8h-1.6v.7M66.8 82.2h-.5l-.1 1.3M67.2 81l-.4 1.2"/>
<path d="M68.1 81l.4 1.2M68.5 82.2h.4l.1 1.3M68.5 82.2l.1 1.3h2.8l.1-1.3M71.5 82.8h-1.7v.7M71.5 82.2h-.4l-.1 1.3M71.9 81l-.4 1.2M72.8 81l.4 1.2M73.2 82.2h.5l.1 1.3M73.2 82.2l.1 1.3h2.8l.1-1.3M76.2 82.8h-1.6l-.1 .7M76.2 82.2h-.4l-.1 1.3M76.7 81l-.5 1.2"/>
<path d="M77.5 81l.4 1.2M77.9 82.2l.2 1.3h2.7l.1-1.3M77.9 82.2h.5l.1 1.3M80.9 82.8h-1.6l-.1 .7M80.9 82.2h-.4l-.1 1.3M81.4 81l-.5 1.2M82.2 81l.5 1.2M82.7 82.2l.1 1.3h2.8l.1-1.3M82.7 82.2h.4l.1 1.3M85.6 82.8h-1.6v.7M85.7 82.2h-.5l-.1 1.3M86.1 81l-.4 1.2"/>
<path d="M87 81l.4 1.2M87.4 82.2l.1 1.3h2.8l.1-1.3M87.4 82.2h.4l.1 1.3M90.3 82.8h-1.5l-.1 .7M90.4 82.2h-.4l-.2 1.3M90.8 81l-.4 1.2M91.7 81l.4 1.2M92.1 82.2h.4l.2 1.3M94.6 83.5l.1-1.3h2.6l.1 1.3M95.1 82.8h-1.6l-.1 .7M95.5 81l-.4 1.2-.1 1.3h-2.8l-.1-1.3M96.4 81l.4 1.2 .1 1.3h2.8l.1-1.3"/>
<path d="M99.8 82.8h-1.6l-.1 .7M99.8 82.2h-.4l-.1 1.3M100.3 81l-.5 1.2M101.1 81l.5 1.2M101.6 82.2l.1 1.3h2.8l.1-1.3M101.6 82.2h.4l.1 1.3M104.5 82.8h-1.6l-.1 .7M104.6 82.2h-.5l-.1 1.3M105 81l-.4 1.2M105.9 81l.4 1.2M106.3 82.2l.1 1.3h2.8l.1-1.3M106.3 82.2h.4l.1 1.3"/>
<path d="M109.2 82.8h-1.5l-.1 .7M109.3 82.2h-.4l-.2 1.3M109.7 81l-.4 1.2M110.6 81l.4 1.2M111 82.2l.1 1.3h2.8l.1-1.3M111 82.2h.4l.2 1.3M114 82.8h-1.6l-.1 .7M114 82.2h-.4l-.1 1.3M114.4 81l-.4 1.2M115.3 81l.4 1.2M115.7 82.2l.2 1.3h2.7l.1-1.3M115.7 82.2h.5l.1 1.3"/>
<path d="M118.7 82.8h-1.6l-.1 .7M118.7 82.2h-.4l-.1 1.3M119.2 81l-.5 1.2M120 81l.5 1.2M120.5 82.2h.4l.1 1.3M120.5 82.2l.1 1.3h2.8l.1-1.3M123.4 82.8h-1.6v.7M123.5 82.2h-.5l-.1 1.3M123.9 81l-.4 1.2M124.8 81l.4 1.2M125.2 82.2h.4l.2 1.3M125.2 82.2l.1 1.3h2.8l.1-1.3"/>
<path d="M128.2 82.8h-1.6l-.1 .7M128.2 82.2h-.4l-.2 1.3M128.6 81l-.4 1.2M129.5 81l.4 1.2M129.9 82.2h.5l.1 1.3M129.9 82.2l.1 1.3h2.8l.1-1.3M132.9 82.8h-1.6l-.1 .7M132.9 82.2h-.4l-.1 1.3M133.4 81l-.5 1.2M134.2 81l.4 1.2M134.6 82.2h.5l.1 1.3M134.6 82.2l.2 1.3h2.7"/>
<path d="M137.6 82.8h-1.6v.7M138.1 81l-.4 1.2h-.5l-.1 1.3"/>
</g>
<g fill="none" stroke="#000" stroke-width=".17">
<path d="M68.7 39.2h.5M68.7 38.6h.5M68.7 38.5h.5M68.7 37.7h.5M68.7 34.6h.5M68.7 33.7h.5M68.7 33.6h.5M68.8 39.3l.2 .1M68.8 37.2h-.1v.2h.1M68.8 36.7h.2M68.8 35.6h.2M68.8 36.6h-.1v.2h.1"/>
<path d="M68.8 36h-.1v.3h.1M68.8 35.4h-.1v.3h.1M68.8 34.9h-.1v.2h.1M69 32.9l-.2 .1M69 32.9h1.5v.1M69 32.9v.1M69 39.3v.1M69 37.5h.1M69.1 37.5h.1v.2M69.1 35.5v1.3M69.1 36.8h-.3h.2M69.1 34.8h-.3v2.7h.3"/>
<path d="M69.1 35.5h-.3h.2v1.3M69.1 34.8v.7M69.1 36.8v.7M69.2 39.3h-.5v-1.8h.5v1.9M69.2 39.3h1.3M69.2 38.7h3.9M69.2 38.5h3.9M69.2 34.6v.1l-.1 .1M69.2 32.9v1.8h-.5v-1.7h.5M69.2 33h1.3M69.2 33.8h3.9M69.2 33.6h3.9"/>
<path d="M70.5 39.3l.3-.1h.9l.2 .1M70.5 39.3v.1h-1.5M70.8 39.2v.2h.8v-.2M70.8 33.1v-.2h.8v.2M71.9 39.3h1.2M71.9 33l-.2 .1h-.9l-.3-.1M71.9 39.3v.1h1.2M71.9 33h1.2M73.1 39.2h.2M73.1 32.9v6.5M73.1 32.9h-1.2v.1M73.1 39.4h.1"/>
<path d="M73.1 33.4h.3l.2 .2v5.1l-.2 .2h-.3M73.1 33.9l.4 .1 .1 .1h-.1M73.2 33.9v4.4M73.2 32.9l.1 .2M73.2 32.9h-.1M73.2 32.9l.3-.2 .1 .2-.3 .2M73.3 33.4v.5l.2 .2M73.3 33.1h-.2M73.3 39.2l.3 .2-.1 .2-.3-.2M73.3 39.2l-.1 .2M73.3 32.8l.1 .2M73.4 39.3l-.1 .2"/>
<path d="M73.5 34.1v4M73.5 38.1l-.2 .2v.6M73.5 38.1h.1l-.1 .2h-.4M79.3 39.2h.4M79.3 38.6h.4M79.3 38.5h.4M79.3 37.7h.4M79.3 34.6h.4M79.3 33.7h.4M79.3 33.6h.4M79.3 39.3l.2 .1M79.4 37.2l-.1 .2h.1"/>
<path d="M79.4 36.7h.2M79.4 35.6h.2M79.4 36.6l-.1 .2h.1M79.4 36l-.1 .3h.1M79.4 35.4l-.1 .3h.1M79.4 34.9l-.1 .2h.1M79.5 32.9l-.2 .1M79.5 32.9l1.6 .1M79.5 32.9v.1M79.5 39.3v.1M79.6 37.5h.1M79.6 37.5l.1 .2"/>
<path d="M79.6 35.5l.1 .1M79.6 36.8h-.2h.2M79.6 34.8h-.2v2.7h.2M79.6 35.5h-.2h.2v1.3M79.6 34.8v.7M79.6 36.8v.7M79.7 36.7l-.1 .1M79.7 35.6v1.1M79.7 39.3h-.4v-1.8h.4v1.9M79.7 39.3h1.4M79.7 38.7h4M79.7 38.5h4"/>
<path d="M79.7 34.6l-.1 .2M79.7 32.9v1.8h-.4v-1.7h.4M79.7 33h1.4M79.7 33.8h4M79.7 33.6h4M81.1 39.3l.2-.1h1l.2 .1M81.1 39.3l-1.6 .1M81.4 39.2v.2h.8v-.2M81.4 33.1v-.2h.8v.2M82.5 39.3h1.2M82.5 39.3l1.2 .1M82.5 33l-.2 .1h-1l-.2-.1"/>
<path d="M82.5 33h1.2M83.7 38.3h.2M83.7 39.2h.1M83.7 32.9v6.5M83.7 32.9l-1.2 .1M83.7 39.4h.1M83.7 33.4h.2l.2 .2v5.1l-.2 .2h-.2M83.7 33.9h.2M83.7 33.9v4.4M83.7 32.9l.1 .2M83.7 32.9h.1M83.7 32.9l.3-.2 .1 .2-.3 .2"/>
<path d="M83.8 33.4v.5l.3 .1-.1 .1M83.8 33.1h-.1M83.8 39.2l.3 .2-.1 .2-.3-.2M83.8 39.2l-.1 .2M83.8 32.8l.1 .2M83.9 34l.1 .1M83.9 39.3l-.1 .2M84 34.1v4M84 38.1l-.1 .2M84 38.1h.1l-.1 .2h-.2v.6M89.8 39.2h.5M89.8 38.6h.5"/>
<path d="M89.8 38.5h.5M89.8 37.7h.5M89.8 34.6h.5M89.8 33.7h.5M89.8 33.6h.5M89.8 39.3l.3 .1M89.9 37.2l-.1 .2h.1M89.9 36.7h.2M89.9 35.6h.2M89.9 36.6l-.1 .2h.1M89.9 36l-.1 .3h.1M89.9 35.4l-.1 .3h.1"/>
<path d="M89.9 34.9l-.1 .2h.1M90.1 32.9l-.3 .1M90.1 32.9h1.5v.1M90.1 32.9v.1M90.1 39.3v.1M90.1 35.5v1.3M90.1 37.5h.1M90.1 35.5h.1M90.2 36.8h-.3h.2M90.2 34.8h-.3v2.7h.3M90.2 37.5l.1 .2M90.2 35.5v1.3"/>
<path d="M90.2 35.5h-.3h.2M90.2 34.8v.7M90.2 36.8v.7M90.3 39.3h-.5v-1.8h.5v1.9M90.3 39.3h1.3M90.3 38.7h3.9M90.3 38.5h3.9M90.3 32.9v1.8h-.5v-1.7h.5M90.3 33h1.3M90.3 34.6l-.1 .2M90.3 33.8h3.9M90.3 33.6h3.9"/>
<path d="M91.6 39.3l.2-.1h1l.2 .1M91.6 39.3v.1h-1.5M91.9 33.1v-.2h.8v.2M91.9 39.2v.2h.8v-.2M93 39.3h1.2M93 33l-.2 .1h-1l-.2-.1M93 39.3v.1h1.2M93 33h1.2M94.2 32.9v6.5M94.2 39.2h.2M94.2 32.9h-1.2v.1M94.2 39.4h.1"/>
<path d="M94.2 33.4h.3l.1 .2v5.1l-.1 .2h-.3M94.2 33.9h.3M94.2 33.9v4.4M94.2 32.9l.2 .2M94.2 32.9l.3-.2 .1 .2-.2 .2M94.2 32.9h.1M94.4 33.4v.5M94.4 38.3v.6M94.4 39.2l.2 .2-.1 .2-.3-.2M94.4 39.2l-.2 .2M94.4 33.1h-.2M94.4 32.8l.1 .2"/>
<path d="M94.4 33.9l.2 .1-.1 .1M94.4 34l.1 .1M94.5 39.3l-.1 .2M94.5 34.1v4M94.5 38.1l-.1 .2M94.5 38.1h.1v.2h-.4M100.4 39.2h.4M100.4 38.6h.4M100.4 38.5h.4M100.4 37.7h.4M100.4 34.6h.4M100.4 33.7h.4"/>
<path d="M100.4 33.6h.4M100.4 39.3l.2 .1M100.4 37.2h-.1v.2h.1M100.4 36.7h.2M100.4 35.6h.2M100.4 36.6h-.1v.2h.1M100.4 36h-.1v.3h.1M100.4 35.4h-.1v.3h.1M100.4 34.9h-.1v.2h.1M100.6 32.9l-.2 .1M100.6 32.9h1.6v.1M100.6 32.9v.1"/>
<path d="M100.6 39.3v.1M100.6 37.5h.1M100.7 37.5h.1v.2M100.7 35.5v1.3M100.7 36.8h-.3h.2M100.7 34.8h-.3v2.7h.3M100.7 35.5h-.3h.2v1.3M100.7 34.8v.7M100.7 36.8v.7M100.8 39.3h-.4v-1.8h.4v1.9M100.8 39.3h1.4M100.8 38.7h3.9"/>
<path d="M100.8 38.5h3.9M100.8 34.6v.1l-.1 .1M100.8 32.9v1.8h-.4v-1.7h.4M100.8 33h1.4M100.8 33.8h3.9M100.8 33.6h3.9M102.2 39.3l.2-.1h.9l.2 .1M102.2 39.3v.1h-1.6M102.4 33.1v-.2h.8l.1 .2M102.4 39.2v.2M103.3 39.2l-.1 .2h-.8M103.5 39.3h1.2"/>
<path d="M103.5 33l-.2 .1h-.9l-.2-.1M103.5 39.3v.1h1.2M103.5 33h1.2M104.7 39.2h.2M104.7 32.9v6.5M104.7 32.9h-1.2v.1M104.7 39.4h.1M104.7 33.4h.3l.2 .2v5.1l-.2 .2h-.3M104.7 33.9l.4 .1 .1 .1h-.1M104.8 33.9v4.4M104.8 32.9l.1 .2M104.8 32.9h-.1"/>
<path d="M104.8 32.9l.3-.2 .1 .2-.3 .2M104.9 39.2l-.1 .2M104.9 33.4v.5l.2 .2M104.9 33.1h-.2M104.9 39.2l.3 .2-.1 .2-.3-.2M104.9 32.8l.1 .2M105 39.3l-.1 .2M105.1 34.1v4M105.1 38.1l-.2 .2v.6M105.1 38.1h.1l-.1 .2h-.4M110.9 39.2h.4M110.9 38.6h.4"/>
<path d="M110.9 38.5h.4M110.9 37.7h.4M110.9 34.6h.4M110.9 33.7h.4M110.9 33.6h.4M110.9 39.3l.2 .1M111 37.2l-.1 .2h.1M111 36.7h.2M111 35.6h.2M111 36.6l-.1 .2h.1M111 36l-.1 .3h.1M111 35.4l-.1 .3h.1"/>
<path d="M111 34.9l-.1 .2h.1M111.1 32.9l-.2 .1M111.1 32.9l1.6 .1M111.1 32.9v.1M111.1 39.3v.1M111.2 37.5h.1M111.2 37.5l.1 .2M111.2 35.5v1.3M111.2 36.8h-.2h.2M111.2 34.8h-.2v2.7h.2M111.2 35.5h-.2h.2v1.3M111.2 34.8v.7"/>
<path d="M111.2 36.8v.7M111.3 39.3h-.4v-1.8h.4v1.9M111.3 39.3h1.4M111.3 38.7h4M111.3 38.5h4M111.3 34.6l-.1 .2M111.3 32.9v1.8h-.4v-1.7h.4M111.3 33h1.4M111.3 33.8h4M111.3 33.6h4M112.7 39.3l.2-.1h1l.2 .1M112.7 39.3l-1.6 .1"/>
<path d="M113 33.1v-.2h.8v.2M113 39.2v.2h.8v-.2M114.1 39.3h1.2M114.1 39.3l1.2 .1M114.1 33l-.2 .1h-1l-.2-.1M114.1 33h1.2M114.1 33h.1M115.3 39.2h.1M115.3 32.9v6.5M115.3 32.9l-1.2 .1M115.3 39.4h.1M115.3 33.4h.2l.2 .2v5.1l-.2 .2h-.2"/>
<path d="M115.3 33.9l.3 .1 .1 .1h-.1M115.3 33.9v4.4M115.3 32.9l.1 .2M115.3 32.9h.1M115.3 32.9l.3-.2 .1 .2-.3 .2M115.4 33.4v.5l.2 .2M115.4 33.1h-.1M115.4 39.2l.3 .2-.1 .2-.3-.2M115.4 39.2l-.1 .2M115.4 32.8l.1 .2M115.5 39.3l-.1 .2M115.6 34.1v4"/>
<path d="M115.6 38.1l-.1 .2h-.2M115.6 38.1h.1l-.1 .2h-.2v.6M121.4 39.2h.5M121.4 38.6h.5M121.4 34.6h.5M121.4 33.7h.5M121.4 33.6h.5M121.4 38.5h.5M121.4 37.7h.5M121.4 39.3l.3 .1M121.5 35.4h-.1l.1 .3M121.5 34.9h-.1l.1 .2"/>
<path d="M121.5 36.7h.2M121.5 35.6h.2M121.5 36.6h-.1l.1 .2M121.5 36h-.1l.1 .3M121.5 37.2h-.1l.1 .2M121.7 32.9l-.3 .1M121.7 32.9h1.5v.1M121.7 32.9v.1M121.7 39.3v.1M121.7 37.5h.1M121.8 37.5l.1 .2M121.8 35.5v1.3"/>
<path d="M121.8 34.8h-.3v2.7h.3M121.8 34.8v.7M121.8 36.8v.7M121.8 35.5h-.3h.2v1.3M121.8 36.8h-.3h.2M121.9 32.9v1.8h-.5v-1.7h.5M121.9 34.6l-.1 .2M121.9 39.3h-.5v-1.8h.5v1.9M121.9 39.3h1.3M121.9 38.7h3.9M121.9 33.8h3.9M121.9 33.6h3.9"/>
<path d="M121.9 33h1.3M121.9 38.5h3.9M123.2 39.3v.1h-1.5M123.2 39.3l.2-.1h1l.2 .1M123.5 39.2v.2h.8v-.2M123.5 33.1v-.2h.8v.2M124.6 33l-.2 .1h-1l-.2-.1M124.6 39.3h1.2M124.6 33h1.2M124.6 39.3v.1h1.2M125.8 39.4h.1M125.8 33.9l.4 .1v.1h-.1"/>
<path d="M125.8 39.2h.2M125.8 32.9h-1.2v.1M125.8 33.4h.3l.1 .2v5.1l-.1 .2h-.3M125.8 32.9v6.5M125.8 32.9l.3-.2 .1 .2-.2 .2M125.8 32.9h.1M125.8 32.9l.2 .2M125.8 33.9v4.4M126 33.1h-.2M126 39.2l-.2 .2M126 39.2l.2 .2-.1 .2-.3-.2M126 33.4v.5"/>
<path d="M126 38.3v.6M126 32.8l.1 .2M126 33.9l.1 .2M126.1 39.3l-.1 .2M126.1 38.1l-.1 .2M126.1 38.1h.1v.2h-.4M126.1 34.1v4M132 39.3v-1.8h.4v1.9M132 33.7h.4M132 33.6h.4M132 33h.4M132 39.3h.4"/>
<path d="M132 39.2h.4M132 38.6h.4M132 34.6h.4M132 38.5h.4M132 37.7h.4M132 39.3l.2 .1M132 35.4h-.1v.3h.1M132 34.9h-.1v.2h.1M132 35.6h.2M132 36.6h-.1v.2h.1M132 36h-.1v.3h.1M132 36.7h.2"/>
<path d="M132 37.2h-.1v.2h.1M132.2 32.9l-.2 .1M132.2 32.9h1.6v.1M132.2 32.9v.1M132.2 39.3v.1M132.2 37.5h.1M132.3 37.5h.1v.2M132.3 35.5v1.3M132.3 34.8h-.3v2.7h.3M132.3 34.8v.7M132.3 36.8v.7M132.3 35.5h-.3h.2v1.3"/>
<path d="M132.3 36.8h-.3h.2M132.4 34.6v.1l-.1 .1M132.4 32.9v1.8h-.4v-1.7M132.4 33.8h3.9M132.4 33.6h3.9M132.4 33h1.4M132.4 39.3h1.4M132.4 38.7h3.9M132.4 38.5h3.9M133.8 39.3v.1h-1.6M133.8 39.3l.2-.1h.9l.2 .1M134 33.1v-.2h.8l.1 .2"/>
<path d="M134 39.2v.2h.8l.1-.2M135.1 33h1.2M135.1 33l-.2 .1h-.9l-.2-.1M135.1 39.3h1.2M135.1 39.3v.1h1.2M136.3 39.4h.1M136.3 39.2h.2M136.3 32.9h-1.2v.1M136.3 33.9l.4 .1 .1 .1h-.1M136.3 33.4h.3l.2 .2v5.1l-.2 .2h-.3M136.3 32.9v6.5M136.4 32.9h-.1"/>
<path d="M136.4 32.9l.1 .2M136.4 32.9l.3-.2 .1 .2-.3 .2M136.4 33.9v4.4M136.5 33.1h-.2M136.5 39.2l-.1 .2M136.5 39.2l.3 .2-.1 .2-.3-.2M136.5 33.4v.5l.2 .2M136.5 32.8l.1 .2M136.6 39.3l-.1 .2M136.7 38.1l-.2 .2v.6M136.7 38.1h.1l-.1 .2h-.4M136.7 34.1v4"/>
<path d="M142.5 33.7h.4M142.5 33.6h.4M142.5 39.2h.4M142.5 38.6h.4M142.5 38.5h.4M142.5 34.6h.4M142.5 37.7h.4M142.5 39.3l.2 .1M142.6 36.7h.2M142.6 35.6h.2M142.6 36.6h-.1l.1 .2M142.6 36h-.1l.1 .3"/>
<path d="M142.6 35.4h-.1l.1 .3M142.6 34.9h-.1l.1 .2M142.6 37.2h-.1l.1 .2M142.7 32.9l-.2 .1M142.7 32.9h1.6v.1M142.7 32.9v.1M142.7 39.3v.1M142.8 37.5h.1M142.8 37.5l.1 .2M142.8 35.5v1.3M142.8 34.8v.7M142.8 36.8v.7"/>
<path d="M142.8 35.5h-.2h.2v1.3M142.8 34.8h-.2v2.7h.2M142.8 36.8h-.2h.2M142.9 34.6l-.1 .2M142.9 33.8h4M142.9 33.6h4M142.9 33h1.4M142.9 39.3h-.4v-1.8h.4v1.9M142.9 39.3h1.4M142.9 38.7h4M142.9 32.9v1.8h-.4v-1.7h.4M142.9 38.5h4"/>
<path d="M144.3 39.3v.1h-1.6M144.3 39.3l.2-.1h1l.2 .1M144.6 33.1v-.2h.8v.2M144.6 39.2v.2h.8v-.2M145.7 33h1.2M145.7 39.3h1.2M145.7 33l-.2 .1h-1l-.2-.1M145.7 39.3v.1h1.2M146.9 39.4h.1M146.9 39.2h.1M146.9 32.9h-1.2v.1M146.9 33.9l.3 .1 .1 .1h-.1"/>
<path d="M146.9 33.4h.3l.1 .2v5.1l-.1 .2h-.3M146.9 38.3h.3M146.9 32.9v6.5M146.9 32.9h.1M146.9 32.9l.1 .2M146.9 32.9l.3-.2 .1 .2-.3 .2M146.9 33.9v4.4M147 33.1h-.1M147 39.2l-.1 .2M147 39.2l.3 .2-.1 .2-.3-.2M147 33.4v.5M147 38.3v.6"/>
<path d="M147 32.8l.2 .2M147 33.9l.2 .2M147.1 38.3h-.1M147.2 39.3l-.2 .2M147.2 38.1l-.1 .2M147.2 38.1h.1l-.1 .2M147.2 34.1v4M153 39.3h.5M153 39.2h.5M153 38.6h.5M153 34.6h.5M153 38.5h.5"/>
<path d="M153 39.3v-1.8h.5v1.9M153 33.7h.5M153 33.6h.5M153 33h.5M153 37.7h.5M153 39.3l.3 .1M153.1 35.4l-.1 .3h.1M153.1 34.9l-.1 .2h.1M153.1 36.7h.2M153.1 35.6h.2M153.1 36.6h-.1l.1 .2M153.1 36h-.1l.1 .3"/>
<path d="M153.1 37.2h-.1l.1 .2M153.3 32.9l-.3 .1M153.3 32.9h1.5v.1M153.3 32.9v.1M153.3 39.3v.1M153.3 37.5h.1M153.4 34.8h-.3v2.7h.3M153.4 35.5h-.3h.2v1.3M153.4 34.8v.7M153.4 36.8v.7M153.4 36.8h-.3h.2M153.4 37.5l.1 .2"/>
<path d="M153.4 35.5v1.3M153.5 39.3h1.3M153.5 38.7h3.9M153.5 32.9v1.8h-.5v-1.7M153.5 38.5h3.9M153.5 33.8h3.9M153.5 33.6h3.9M153.5 33h1.3M153.5 34.6l-.1 .2M154.8 39.3v.1h-1.5M154.8 39.3l.2-.1h1l.2 .1M155.1 39.2v.2h.8v-.2"/>
<path d="M155.1 33.1v-.2h.8v.2M156.2 33l-.2 .1h-1l-.2-.1M156.2 39.3h1.2M156.2 39.3v.1h1.2M156.2 33h1.2M157.4 33.9l.4 .1v.1h-.1M157.4 32.9h-1.2v.1M157.4 39.4h.1M157.4 33.4h.3l.1 .2v5.1l-.1 .2h-.3M157.4 39.2h.1M157.4 32.9v6.5M157.4 32.9l.3-.2 .1 .2-.3 .2"/>
<path d="M157.4 32.9l.1 .2M157.4 32.9h.1M157.4 33.9v4.4M157.5 39.2l-.1 .2M157.5 33.1h-.1M157.5 39.2l.3 .2-.1 .2-.3-.2M157.5 33.4v.5M157.5 38.3v.6M157.6 32.8l.1 .2M157.6 33.9l.1 .2M157.7 39.3l-.1 .2M157.7 38.1l-.1 .2"/>
<path d="M157.7 38.1h.1v.2h-.4M157.7 34.1v4M163.5 33.7h.5M163.5 33.6h.5M163.5 39.2h.5M163.5 38.6h.5M163.5 34.6h.5M163.5 38.5h.5M163.5 37.7h.5M163.6 39.3l.2 .1M163.6 35.4h-.1v.3h.1M163.6 34.9h-.1v.2h.1"/>
<path d="M163.6 35.6h.3M163.6 36.6h-.1v.2h.1M163.6 36h-.1v.3h.1M163.6 36.7h.3M163.6 37.2h-.1v.2h.1M163.8 32.9l-.2 .1M163.8 32.9h1.6v.1M163.8 32.9v.1M163.8 39.3v.1M163.9 37.5h.1M163.9 37.5h.1v.2M163.9 35.5v1.3"/>
<path d="M163.9 34.8h-.3v2.7h.3M163.9 34.8v.7M163.9 36.8v.7M163.9 35.5h-.3h.3v1.3M163.9 36.8h-.3h.3M164 34.6v.1l-.1 .1M164 32.9v1.8h-.5v-1.7h.5M164 33.8h3.9M164 33.6h3.9M164 33h1.4M164 39.3h-.5v-1.8h.5v1.9M164 39.3h1.4"/>
<path d="M164 38.7h3.9M164 38.5h3.9M165.4 39.3v.1h-1.6M165.4 39.3l.2-.1h.9l.3 .1M165.7 33.1v-.2h.7l.1 .2M165.7 39.2v.2h.7l.1-.2M166.8 33h1.1M166.8 33l-.3 .1h-.9l-.2-.1M166.8 39.3h1.1M166.8 39.3v.1h1.1M167.9 39.4h.1M167.9 39.2h.2"/>
<path d="M167.9 32.9h-1.1v.1M167.9 33.9h.3M167.9 33.4h.3l.2 .2v5.1l-.2 .2h-.3M167.9 38.3h.3M167.9 32.9v6.5M168 32.9h-.1M168 32.9l.1 .2M168 32.9l.3-.2 .1 .2-.3 .2M168 33.9v4.4M168.1 33.1h-.2M168.1 39.2l-.1 .2M168.1 39.2l.3 .2-.1 .2-.3-.2"/>
<path d="M168.1 33.4v.5M168.1 38.3v.6M168.1 32.8l.1 .2M168.1 33.9l.3 .1v.1h-.1M168.2 34l.1 .1M168.2 38.3h-.1M168.2 39.3l-.1 .2M168.3 38.1l-.1 .2M168.3 38.1h.1l-.2 .2M168.3 34.1v4M174.1 39.3v-1.8h.4v1.9M174.1 33.7h.4"/>
<path d="M174.1 33.6h.4M174.1 33h.4M174.1 39.3h.4M174.1 39.2h.4M174.1 38.6h.4M174.1 38.5h.4M174.1 34.6h.4M174.1 37.7h.4M174.1 39.3l.2 .1M174.2 36.7h.2M174.2 35.6h.2M174.2 36.6h-.1l.1 .2"/>
<path d="M174.2 36h-.1l.1 .3M174.2 35.4h-.1l.1 .3M174.2 34.9h-.1l.1 .2M174.2 37.2h-.1l.1 .2M174.3 32.9l-.2 .1M174.3 32.9h1.6v.1M174.3 32.9v.1M174.3 39.3v.1M174.4 37.5h.1M174.4 37.5l.1 .2M174.4 35.5v1.3M174.4 34.8v.7"/>
<path d="M174.4 36.8v.7M174.4 35.5h-.2h.2v1.3M174.4 34.8h-.2v2.7h.2M174.4 36.8h-.2h.2M174.5 34.6l-.1 .2M174.5 33.8h4M174.5 33.6h4M174.5 33h1.4M174.5 39.3h1.4M174.5 38.7h4M174.5 32.9v1.8h-.4v-1.7M174.5 38.5h4"/>
<path d="M175.9 39.3v.1h-1.6M175.9 39.3l.2-.1h1l.2 .1M176.2 33.1v-.2h.8v.2M176.2 39.2v.2h.8v-.2M177.3 33h1.2M177.3 39.3h1.2M177.3 33l-.2 .1h-1l-.2-.1M177.3 39.3v.1h1.2M178.5 39.4h.1M178.5 39.2h.1M178.5 32.9h-1.2v.1M178.5 33.9l.3 .1 .1 .1h-.1"/>
<path d="M178.5 33.4h.3l.1 .2v5.1l-.1 .2h-.3M178.5 32.9v6.5M178.5 32.9h.1M178.5 32.9l.1 .2M178.5 32.9l.3-.2 .1 .2-.3 .2M178.5 33.9v4.4M178.6 33.1h-.1M178.6 39.2l-.1 .2M178.6 39.2l.3 .2-.1 .2-.3-.2M178.6 33.4v.5M178.6 38.3v.6M178.6 32.8l.2 .2"/>
<path d="M178.6 33.9l.2 .2M178.8 39.3l-.2 .2M178.8 38.1l-.2 .2M178.8 38.1h.1l-.1 .2h-.3M178.8 34.1v4M184.6 39.3h.5M184.6 39.2h.5M184.6 38.6h.5M184.6 38.5h.5M184.6 34.6h.5M184.6 37.7h.5M184.6 39.3v-1.8h.5v1.9"/>
<path d="M184.6 33.7h.5M184.6 33.6h.5M184.6 33h.5M184.6 39.3l.3 .1M184.7 35.4h-.1v.3h.1M184.7 34.9h-.1v.2h.1M184.7 36.7h.2M184.7 35.6h.2M184.7 37.2h-.1v.2h.1M184.7 36.6h-.1v.2h.1M184.7 36h-.1v.3h.1M184.9 32.9l-.3 .1"/>
<path d="M184.9 32.9h1.5v.1M184.9 32.9v.1M184.9 39.3v.1M184.9 37.5h.1M185 34.8h-.3v2.7h.3M185 35.5h-.3h.2v1.3M185 34.8v.7M185 36.8v.7M185 36.8h-.3h.2M185 37.5l.1 .2M185 35.5v1.3M185.1 39.3h1.3"/>
<path d="M185.1 38.7h3.9M185.1 38.5h3.9M185.1 32.9v1.8h-.5v-1.7M185.1 33.8h3.9M185.1 33.6h3.9M185.1 33h1.3M185.1 34.6l-.1 .2M186.4 39.3l.2-.1h1l.2 .1M186.4 39.3v.1h-1.5M186.7 39.2v.2h.8v-.2M186.7 33.1v-.2h.8v.2M187.8 33l-.2 .1h-1l-.2-.1"/>
<path d="M187.8 39.3h1.2M187.8 39.3v.1h1.2M187.8 33h1.2M189 33.9l.4 .1v.1h-.1M189 32.9h-1.2v.1M189 39.4h.1M189 33.4h.3l.1 .2v5.1l-.1 .2h-.3M189 32.9v6.5M189 39.2h.1M189 32.9l.3-.2 .1 .2-.3 .2M189 32.9l.1 .2M189 33.9v4.4"/>
<path d="M189 32.9h.1M189.1 39.2l-.1 .2M189.1 39.2l.3 .2-.1 .2-.3-.2M189.1 33.4v.5M189.1 38.3v.6M189.1 33.1h-.1M189.2 32.8l.1 .2M189.2 33.9l.1 .2M189.3 39.3l-.1 .2M189.3 38.1l-.1 .2M189.3 38.1h.1v.2h-.4M189.3 34.1v4"/>
</g>
<path d="M59.2 24.8h8.7M69.4 24.8h3.5M69.4 23.9v4.4M72.9 23.9v4.4M74.4 24.8h1.5" fill="none" stroke="#4b4b4b" stroke-width=".17"/>
<g fill="#4b4b4b">
<path d="M72.9 24.8l1.5-.2v.5z"/>
<path d="M67.9 24.6l1.5 .2-1.5 .3z"/>
</g>
<path d="M53.8 19.4l-4.5 8.3M47.3 31.4l-.7 1.3M48.6 29l-.6 1.1" fill="none" stroke="#4b4b4b" stroke-width=".17"/>
<g fill="#4b4b4b">
<path d="M48 30.1l-.5 1.4-.4-.2z"/>
<path d="M49.1 27.6l.5 .2-1 1.2z"/>
</g>
<path d="M14.6 28h8.7M15.5 29.5v11.1M23 29.6h1.5M14.6 42.1h8.7" fill="none" stroke="#4b4b4b" stroke-width=".17"/>
<path d="M23.7 28.8v1.5" fill="none" stroke="#000" stroke-width=".25"/>
<g fill="#4b4b4b">
<path d="M15.3 40.6h.5l-.3 1.5z"/>
<path d="M15.5 28l.3 1.5h-.5z"/>
</g>
<path d="M19.7 18v8.6M18.8 28h4.5M18.8 29.6h3.7M19.7 28v1.6M19.7 31v1.5" fill="none" stroke="#4b4b4b" stroke-width=".17"/>
<g fill="#4b4b4b">
<path d="M19.7 29.6l.2 1.4h-.5z"/>
<path d="M19.4 26.6h.5l-.2 1.4z"/>
</g>
<path d="M29 23.5v7.2M30.5 24.5h7.5M39.5 23.5v7.2" fill="none" stroke="#4b4b4b" stroke-width=".17"/>
<g fill="#4b4b4b">
<path d="M29 24.5l1.5-.3v.5z"/>
<path d="M38 24.2l1.5 .3-1.5 .2z"/>
</g>
<g fill="none" stroke="#4b4b4b" stroke-width=".17">
<path d="M26.5 29.6h1.5M27.3 28.8v1.5M29 31.2v3.9M29 35.8v.7M29 37.2v3.8M30 29.6h1.6M30.8 28.8v1.5M33.5 29.6h1.6M34.3 28.8v1.5M37 29.6h1.6M37.8 28.8v1.5M39.5 31.2v3.9"/>
<path d="M39.5 35.8v.7M39.5 37.2v3.8M40.5 29.6h1.6M41.3 28.8v1.5M44 29.6h1.6M44.8 28.8v1.5M47.5 29.6h1.6M48.3 28.8v1.5M50.1 31.2v3.9M50.1 35.8v.7M50.1 37.2v3.8M51.1 29.6h1.5"/>
<path d="M51.8 28.8v1.5M54.6 29.6h1.5M55.4 28.8v1.5M58.1 29.6h1.5M58.9 28.8v1.5M60.6 31.2v3.9M60.6 35.8v.7M60.6 37.2v3.8M61.6 29.6h1.6M62.4 28.8v1.5M65.1 29.6h1.6M65.9 28.8v1.5"/>
<path d="M68.6 29.6h1.6M69.4 28.8v1.5M71.1 31.2v3.9M71.1 35.8v.7M71.1 37.2v3.8M72.1 29.6h1.6M72.9 28.8v1.5M234.4 23.9v3.7M235.9 24.8h23.7M261 23.9v5.9"/>
</g>
<g fill="none" stroke="#000" stroke-width=".17">
<path d="M275.1 28h.3v4.4l3.6 .2v7.1l-3.6 .2v2.2h-.3zM275.1 39.5h3.5M275.1 32.8h3.5M275.1 32.6l3.6 .2v6.7l-3.6 .2M275.3 28l-.2 .2M275.3 39.7l-.2 .2M275.4 28.4l-.3 .3M275.4 28.9l-.3 .3M275.4 29.4l-.3 .2M275.4 29.8l-.3 .3M275.4 30.3l-.3 .3M275.4 30.8l-.3 .2"/>
<path d="M275.4 31.2l-.3 .3M275.4 31.7l-.3 .3M275.4 32.2l-.3 .2M275.6 32.4l-.2 .2M275.8 39.6l-.3 .3M276.1 32.4l-.3 .3M276.3 39.6l-.3 .3M276.5 32.4l-.3 .3M276.8 39.6l-.3 .2M276.9 32.5l-.2 .2M277.3 39.5l-.3 .3M277.4 32.5l-.3 .2"/>
<path d="M277.8 39.5l-.3 .3M277.8 32.5l-.2 .3M278.3 32.5l-.3 .3v6.7M278.3 39.5l-.3 .3M278.7 32.5l-.3 .3M279 32.8l-.3 .2M279 33.2l-.3 .3M279 33.7l-.3 .2M279 34.1l-.3 .3M279 34.6l-.3 .3M279 35.1l-.3 .2M279 35.5l-.3 .3"/>
<path d="M279 36l-.3 .3M279 36.5l-.3 .2M279 36.9l-.3 .3M279 37.4l-.3 .3M279 37.9l-.3 .2M279 38.3l-.3 .3M279 38.8l-.3 .3M279 39.3l-.5 .4M275.4 40.1l-.3 .2M275.4 40.5l-.3 .3M275.4 41l-.3 .3M275.4 41.5l-.3 .2"/>
<path d="M275.4 41.9l-.2 .2"/>
</g>
<g fill="none" stroke="#000" stroke-width=".25">
<path d="M26.2 39.9h2M26.2 32.4l.2 .2M26.2 32.4v7.5M26.2 32.4h2M26.4 32.6h.8l.3-.2 .2 .2M26.4 39.6h.8M26.4 33.9h5.2M26.4 38.3h5.2M26.4 39.6l-.2 .3M26.4 32.6v7M27.2 39.6l.1-.1h.4v.1M27.2 32.6l.1 .2h.4v-.2"/>
<path d="M27.2 39.6l.3 .3 .2-.3M27.3 33.9v4.4M27.7 39.6h.7M27.7 32.6h.7M28.2 32.4v-.3h1.6v.3l-.2 .2M28.2 32.1l.2 .2M28.2 32.4l.2 .2M28.4 39.6v.4M28.4 40h1.2M28.4 40l-.2 .2M28.4 39.6l-.2 .3M28.4 32.3v.3"/>
<path d="M28.4 32.3h1.2M29.6 39.6l.2 .3v.3h-1.6v-.3M29.6 40l.2 .2M29.6 32.3v.3h2M29.8 32.1l-.2 .2M29.8 32.4h2l-.2 .2M30.7 33.9v4.4M31.6 39.6h-2v.4M31.6 39.6l.2 .3h-2M31.6 32.6v7M31.8 32.4v7.5M36.7 32.4h2.1"/>
<path d="M36.7 39.9h2.1M36.7 32.4l.3 .2M36.7 32.4v7.5M37 39.6h.7M37 32.6v7M37 39.6l-.3 .3M37 33.9h5.1M37 38.3h5.1M37.7 32.6l.1 .2h.4l.1-.2M37.7 39.6l.1-.1h.4l.1 .1M37.7 39.6l.3 .3M37.8 33.9v4.4"/>
<path d="M38 32.4l-.3 .2h-.7M38 32.4l.3 .2M38.3 39.6l-.3 .3M38.3 32.6h.7M38.3 39.6h.7M38.8 32.4v-.3h1.5v.3l-.2 .2M38.8 32.1l.2 .2M38.8 32.4l.2 .2M39 32.3v.3M39 39.6v.4M39 40l-.2 .2M39 39.6l-.2 .3"/>
<path d="M39 32.3h1.1M39 40h1.1M40.1 39.6l.2 .3v.3h-1.5v-.3M40.1 40l.2 .2M40.1 32.3v.3h2M40.3 32.1l-.2 .2M40.3 32.4h2l-.2 .2M41.2 33.9v4.4M42.1 39.6h-2v.4M42.1 39.6l.2 .3h-2M42.1 32.6v7M42.3 32.4v7.5"/>
<path d="M47.2 32.4h2.1M47.2 39.9h2.1M47.2 32.4l.3 .2M47.2 32.4v7.5M47.5 39.6h.8M47.5 32.6v7M47.5 39.6l-.3 .3M47.5 33.9h5.1M47.5 38.3h5.1M48.3 32.6l.1 .2h.4v-.2M48.3 39.6v-.1h.4l.1 .1M48.3 39.6l.2 .3"/>
<path d="M48.4 33.9v4.4M48.5 32.4l-.2 .2h-.8M48.6 32.4l.2 .2M48.8 39.6l-.2 .3M48.8 32.6h.7M48.8 39.6h.7M49.3 32.4v-.3h1.6v.3l-.2 .2M49.3 32.1l.2 .2M49.3 32.4l.2 .2M49.5 32.3v.3M49.5 39.6v.4M49.5 40l-.2 .2"/>
<path d="M49.5 39.6l-.2 .3M49.5 32.3h1.2M49.5 40h1.2M50.7 39.6l.2 .3v.3h-1.6v-.3M50.7 40l.2 .2M50.7 32.3v.3h1.9M50.9 32.1l-.2 .2M50.9 32.4h2l-.3 .2M51.8 33.9v4.4M52.6 39.6h-1.9v.4M52.6 39.6l.3 .3h-2M52.6 32.6v7"/>
<path d="M52.9 32.4v7.5M57.8 39.9h2M57.8 32.4l.2 .2M57.8 32.4v7.5M57.8 32.4h2M58 39.6h.8M58 33.9h5.2M58 38.3h5.2M58 39.6l-.2 .3M58 32.6v7M58.8 39.6l.1-.1h.4v.1M58.8 32.6l.1 .2h.4v-.2"/>
<path d="M58.8 39.6l.3 .3M58.9 33.9v4.4M59.1 32.4l-.3 .2h-.8M59.1 32.4l.2 .2M59.3 39.6l-.2 .3M59.3 39.6h.7M59.3 32.6h.7M59.8 32.4v-.3h1.6v.3l-.2 .2M59.8 32.1l.2 .2M59.8 32.4l.2 .2M60 39.6v.4M60 40h1.2"/>
<path d="M60 40l-.2 .2M60 39.6l-.2 .3M60 32.3v.3M60 32.3h1.2M61.2 39.6l.2 .3v.3h-1.6v-.3M61.2 40l.2 .2M61.2 32.3v.3h2M61.4 32.1l-.2 .2M61.4 32.4h2l-.2 .2M62.3 33.9v4.4M63.2 39.6h-2v.4M63.2 39.6l.2 .3h-2"/>
<path d="M63.2 32.6v7M63.4 32.4v7.5M68.3 32.4h2.1M68.3 39.9h2.1M68.3 32.4l.3 .2M68.3 32.4v7.5M68.6 39.6h.7M68.6 32.6v7M68.6 39.6l-.3 .3M69.3 32.6l.1 .2h.4l.1-.2M69.3 39.6l.1-.1h.4l.1 .1M69.3 39.6l.3 .3"/>
<path d="M69.6 32.4l-.3 .2h-.7M69.6 32.4l.3 .2M69.9 39.6l-.3 .3M69.9 32.6h.7M69.9 39.6h.7M70.4 32.4v-.3h1.5v.3l-.2 .2M70.4 32.1l.2 .2M70.4 32.4l.2 .2M70.6 32.3v.3M70.6 39.6v.4M70.6 40l-.2 .2M70.6 39.6l-.2 .3"/>
<path d="M70.6 32.3h1.1M70.6 40h1.1M71.7 39.6l.2 .3v.3h-1.5v-.3M71.7 40l.2 .2M71.7 32.3v.3h2M71.9 32.1l-.2 .2M71.9 32.4h2l-.2 .2M73.7 39.6h-2v.4M73.7 39.6l.2 .3h-2M73.7 32.6v7M73.9 32.4v7.5M76.4 28.9a.66 .66 0 0 0-.6 .7 .66 .66 0 0 0 .6 .6"/>
<path d="M234.4 28.9v-.9h-210.7v.9a.66 .66 0 0 1 .7 .7 .66 .66 0 0 1-.7 .6v11.9h237.3M234.4 30.2v11.9"/>
<circle cx="27.3" cy="29.5" r=".66"/>
<circle cx="30.8" cy="29.6" r=".66"/>
<circle cx="34.3" cy="29.6" r=".66"/>
<circle cx="37.8" cy="29.6" r=".66"/>
<circle cx="41.3" cy="29.6" r=".66"/>
<circle cx="44.8" cy="29.6" r=".66"/>
<circle cx="48.3" cy="29.5" r=".66"/>
<circle cx="51.8" cy="29.5" r=".66"/>
<circle cx="55.3" cy="29.5" r=".66"/>
<circle cx="58.9" cy="29.6" r=".66"/>
<circle cx="62.4" cy="29.6" r=".66"/>
<circle cx="65.9" cy="29.6" r=".66"/>
<circle cx="69.4" cy="29.6" r=".66"/>
<circle cx="72.9" cy="29.6" r=".66"/>
</g>
<g fill="#4b4b4b">
<path d="M234.4 24.8l1.5-.2v.4z"/>
<path d="M259.6 24.6l1.4 .2-1.4 .2z"/>
</g>
<path d="M261.5 30.3h6.5M267.1 31.8v8.8M261.5 42.1h6.5" fill="none" stroke="#4b4b4b" stroke-width=".17"/>
<g fill="#4b4b4b">
<path d="M266.8 40.6h.5l-.2 1.5z"/>
<path d="M267.1 30.3l.2 1.5h-.5z"/>
<path d="M247.5 40.1l1.2 1-.4 .3z"/>
</g>
<path d="M192.3 42.6v13M193.8 54.7h39.1M234.4 42.5v13.1M248.5 41.3l4.4 5" fill="none" stroke="#4b4b4b" stroke-width=".17"/>
<g fill="#4b4b4b">
<path d="M192.3 54.7l1.5-.3v.5z"/>
<path d="M232.9 54.4l1.5 .3-1.5 .2z"/>
</g>
<path d="M65.9 42.6v13M67.4 54.7h123.4M192.3 42.6v13" fill="none" stroke="#4b4b4b" stroke-width=".17"/>
<g fill="#4b4b4b">
<path d="M190.8 54.4l1.5 .3-1.5 .2z"/>
<path d="M65.9 54.7l1.5-.3v.5z"/>
</g>
<path d="M23.7 42.6v13M25.2 54.7h39.2M65.9 42.6v13" fill="none" stroke="#4b4b4b" stroke-width=".17"/>
<g fill="#4b4b4b">
<path d="M23.7 54.7l1.5-.3v.5z"/>
<path d="M64.4 54.4l1.5 .3-1.5 .2z"/>
</g>
<g fill="none" stroke="#4b4b4b" stroke-width=".17">
<path d="M75.6 29.6h1.6M76.4 28.8v1.5M79.1 29.6h1.6M79.9 28.8v1.5M81.7 31.2v3.9M81.7 35.8v.7M81.7 37.2v3.8M82.7 29.6h1.5M83.4 28.8v1.5M86.1 29.6h1.6M87 28.8v1.5M89.7 29.6h1.5"/>
<path d="M90.5 28.8v1.5M92.2 31.2v3.9M92.2 35.8v.7M92.2 37.2v3.8M93.2 29.6h1.6M94 28.8v1.5M96.7 29.6h1.6M97.5 28.8v1.5M100.2 29.6h1.6M101 28.8v1.5M102.7 31.2v3.9M102.7 35.8v.7"/>
<path d="M102.7 37.2v3.8M103.7 29.6h1.6M104.5 28.8v1.5M107.2 29.6h1.6M108 28.8v1.5M110.7 29.6h1.6M111.5 28.8v1.5M113.3 31.2v3.9M113.3 35.8v.7M113.3 37.2v3.8M114.3 29.6h1.5M115 28.8v1.5"/>
<path d="M117.8 29.6h1.5M118.6 28.8v1.5M121.3 29.6h1.6M122.1 28.8v1.5M123.8 31.2v3.9M123.8 35.8v.7M123.8 37.2v3.8M124.8 29.6h1.6M125.6 28.8v1.5M128.3 29.6h1.6M129.1 28.8v1.5M131.8 29.6h1.6"/>
<path d="M132.6 28.8v1.5M134.3 31.2v3.9M134.3 35.8v.7M134.3 37.2v3.8M135.3 29.6h1.6M136.1 28.8v1.5M138.8 29.6h1.6M139.6 28.8v1.5M142.3 29.6h1.6M143.1 28.8v1.5M144.9 31.2v3.9M144.9 35.8v.7"/>
<path d="M144.9 37.2v3.8M145.8 29.6h1.6M146.6 28.8v1.5M149.4 29.6h1.5M150.2 28.8v1.5M152.9 29.6h1.6M153.7 28.8v1.5M155.4 31.2v3.9M155.4 35.8v.7M155.4 37.2v3.8M156.4 29.6h1.6M157.2 28.8v1.5"/>
<path d="M159.9 29.6h1.6M160.7 28.8v1.5M163.4 29.6h1.6M164.2 28.8v1.5M165.9 31.2v3.9M165.9 35.8v.7M165.9 37.2v3.8M166.9 29.6h1.6M167.7 28.8v1.5M170.4 29.6h1.6M171.2 28.8v1.5M173.9 29.6h1.6"/>
<path d="M174.7 28.8v1.5M176.5 31.2v3.9M176.5 35.8v.7M176.5 37.2v3.8M177.4 29.6h1.6M178.2 28.8v1.5M181 29.6h1.5M181.8 28.8v1.5M184.5 29.6h1.6M185.3 28.8v1.5M187 31.2v3.9M187 35.8v.7"/>
<path d="M187 37.2v3.8M188 29.6h1.6M188.8 28.8v1.5M191.5 29.6h1.6M192.3 28.8v1.5M195 29.6h1.6M195.8 28.8v1.5M197.5 31.2v3.9M197.5 35.8v.7M197.5 37.2v3.8M198.5 29.6h1.6M199.3 28.8v1.5"/>
<path d="M202 29.6h1.6M202.8 28.8v1.5M205.5 29.6h1.6M206.3 28.8v1.5M208.1 31.2v3.9M208.1 35.8v.7M208.1 37.2v3.8M209 29.6h1.6M209.8 28.8v1.5M212.6 29.6h1.5M213.4 28.8v1.5M216.1 29.6h1.6"/>
<path d="M216.9 28.8v1.5M218.6 31.2v3.9M218.6 35.8v.7M218.6 37.2v3.8M219.6 29.6h1.6M220.4 28.8v1.5M223.1 29.6h1.6M223.9 28.8v1.5M226.6 29.6h1.6M227.4 28.8v1.5M229.1 31.2v3.9M229.1 35.8v.7"/>
<path d="M229.1 37.2v3.8M230.1 29.6h1.6M230.9 28.8v1.5"/>
</g>
<g fill="none" stroke="#000" stroke-width=".25">
<path d="M23.7 30.3h237.3v11.8M78.8 32.4h2.1M78.8 39.9h2.1M78.8 32.4l.3 .2M78.8 32.4v7.5M79.1 39.6h.8M79.1 32.6v7M79.1 39.6l-.3 .3M79.9 32.6l.1 .2h.4v-.2M79.9 39.6v-.1h.4l.1 .1M79.9 39.6l.2 .3M80.1 32.4l-.2 .2h-.8"/>
<path d="M80.2 32.4l.2 .2M80.4 39.6l-.2 .3M80.4 32.6h.7M80.4 39.6h.7M80.9 32.4v-.3h1.6v.3l-.2 .2M80.9 32.1l.2 .2M80.9 32.4l.2 .2M81.1 32.3v.3M81.1 39.6v.4M81.1 40l-.2 .2M81.1 39.6l-.2 .3M81.1 32.3h1.2"/>
<path d="M81.1 40h1.2M82.3 39.6l.2 .3v.3h-1.6v-.3M82.3 40l.2 .2M82.3 32.3v.3h1.9M82.5 32.1l-.2 .2M82.5 32.4h2l-.3 .2M84.2 39.6h-1.9v.4M84.2 39.6l.3 .3h-2M84.2 32.6v7M84.5 32.4v7.5M89.4 32.4h2M89.4 39.9h2"/>
<path d="M89.4 32.4l.2 .2M89.4 32.4v7.5M89.6 39.6h.8M89.6 32.6v7M89.6 39.6l-.2 .3M90.4 32.6l.1 .2h.4v-.2M90.4 39.6v-.1h.4l.1 .1M90.4 39.6l.3 .3M90.7 32.4l-.3 .2h-.8M90.7 32.4l.2 .2M90.9 39.6l-.2 .3M90.9 32.6h.8"/>
<path d="M90.9 39.6h.8M91.4 32.4v-.3h1.6v.3l-.2 .2M91.4 32.1l.3 .2M91.4 32.4l.3 .2M91.7 32.3v.3M91.7 39.6v.4M91.7 40l-.3 .2M91.7 39.6l-.3 .3M91.7 32.3h1.1M91.7 40h1.1M92.8 39.6l.2 .3v.3h-1.6v-.3M92.8 40l.2 .2"/>
<path d="M92.8 32.3v.3h2M93 32.1l-.2 .2M93 32.4h2l-.2 .2M94.8 39.6h-2v.4M94.8 39.6l.2 .3h-2M94.8 32.6v7M95 32.4v7.5M99.9 39.9h2.1M99.9 32.4l.3 .2M99.9 32.4v7.5M99.9 32.4h2.1M100.2 39.6h.7"/>
<path d="M100.2 39.6l-.3 .3M100.2 32.6v7M100.9 39.6l.1-.1h.4l.1 .1M100.9 32.6l.1 .2h.4l.1-.2M100.9 39.6l.3 .3M101.2 32.4l-.3 .2h-.7M101.2 32.4l.3 .2M101.5 39.6h.7M101.5 39.6l-.3 .3M101.5 32.6h.7M102 32.4v-.3h1.5v.3l-.2 .2M102 32.1l.2 .2"/>
<path d="M102 32.4l.2 .2M102.2 39.6v.4M102.2 40h1.1M102.2 40l-.2 .2M102.2 39.6l-.2 .3M102.2 32.3v.3M102.2 32.3h1.1M103.3 39.6l.2 .3v.3h-1.5v-.3M103.3 40l.2 .2M103.3 32.3v.3h2M103.5 32.1l-.2 .2M103.5 32.4h2l-.2 .2"/>
<path d="M105.3 39.6h-2v.4M105.3 39.6l.2 .3h-2M105.3 32.6v7M105.5 32.4v7.5M110.4 32.4h2.1M110.4 39.9h2.1M110.4 32.4l.3 .2M110.4 32.4v7.5M110.7 39.6h.8M110.7 32.6v7M110.7 39.6l-.3 .3M111.5 32.6v.2h.5v-.2"/>
<path d="M111.5 39.6v-.1h.4l.1 .1M111.5 39.6l.2 .3M111.7 32.4l-.2 .2h-.8M111.7 32.4l.3 .2M112 39.6l-.3 .3M112 32.6h.7M112 39.6h.7M112.5 32.4v-.3h1.6v.3l-.2 .2M112.5 32.1l.2 .2M112.5 32.4l.2 .2M112.7 32.3v.3M112.7 39.6v.4"/>
<path d="M112.7 40l-.2 .2M112.7 39.6l-.2 .3M112.7 32.3h1.2M112.7 40h1.2M113.9 39.6l.2 .3v.3h-1.6v-.3M113.9 40l.2 .2M113.9 32.3v.3h1.9M114.1 32.1l-.2 .2M114.1 32.4h2l-.3 .2M115.8 39.6h-1.9v.4M115.8 39.6l.3 .3h-2M115.8 32.6v7"/>
<path d="M116.1 32.4v7.5M121 32.4v7.5M121 32.4l.2 .2M121 32.4h2M121 39.9h2M121.2 32.6h.8l.3-.2 .2 .2M121.2 32.6v7M121.2 39.6l-.2 .3M121.2 39.6h.8M122 32.6l.1 .2h.4v-.2M122 39.6v-.1h.4l.1 .1M122 39.6l.3 .3 .2-.3"/>
<path d="M122.5 32.6h.8M122.5 39.6h.8M123 32.4v-.3h1.6v.3l-.2 .2M123 32.4l.3 .2M123 32.1l.3 .2M123.3 32.3h1.1M123.3 40h1.1M123.3 39.6l-.3 .3M123.3 32.3v.3M123.3 39.6v.4M123.3 40l-.3 .2M124.4 39.6l.2 .3v.3h-1.6v-.3"/>
<path d="M124.4 40l.2 .2M124.4 32.3v.3h2M124.6 32.1l-.2 .2M124.6 32.4h2l-.2 .2M126.4 32.6v7M126.4 39.6h-2v.4M126.4 39.6l.2 .3h-2M126.6 32.4v7.5M131.5 32.4v7.5M131.5 32.4l.3 .2M131.5 32.4h2.1M131.5 39.9h2.1"/>
<path d="M131.8 32.6v7M131.8 39.6l-.3 .3M131.8 39.6h.7M132.5 32.6l.1 .2h.4l.1-.2M132.5 39.6l.1-.1h.4l.1 .1M132.5 39.6l.3 .3M132.8 32.4l-.3 .2h-.7M132.8 32.4l.3 .2M133.1 39.6l-.3 .3M133.1 32.6h.7M133.1 39.6h.7M133.6 32.4v-.3h1.5v.3l-.2 .2"/>
<path d="M133.6 32.4l.2 .2M133.6 32.1l.2 .2M133.8 32.3h1.1M133.8 40h1.1M133.8 39.6l-.2 .3M133.8 32.3v.3M133.8 39.6v.4M133.8 40l-.2 .2M134.9 39.6l.2 .3v.3h-1.5v-.3M134.9 40l.2 .2M134.9 32.3v.3h2M135.1 32.1l-.2 .2"/>
<path d="M135.1 32.4h2l-.2 .2M136.9 32.6v7M136.9 39.6h-2v.4M136.9 39.6l.2 .3h-2M137.1 32.4v7.5M142 32.4v7.5M142 32.4l.3 .2M142 32.4h2.1M142 39.9h2.1M142.3 39.6l-.3 .3M142.3 32.6v7M142.3 39.6h.8"/>
<path d="M142.3 32.6h.8l.2-.2 .3 .2M143.1 39.6l.1-.1h.4v.1M143.1 32.6l.1 .2h.4v-.2M143.1 39.6l.2 .3 .3-.3M143.6 32.6h.7M143.6 39.6h.7M144.1 32.4v-.3h1.6v.3l-.2 .2M144.1 32.4l.2 .2M144.1 32.1l.2 .2M144.3 32.3h1.2M144.3 40h1.2M144.3 39.6l-.2 .3"/>
<path d="M144.3 32.3v.3M144.3 39.6v.4M144.3 40l-.2 .2M145.5 32.3v.3h1.9M145.5 40l.2 .2M145.5 39.6l.2 .3v.3h-1.6v-.3M145.7 32.1l-.2 .2M145.7 32.4h2l-.3 .2M147.4 32.6v7M147.4 39.6l.3 .3h-2M147.4 39.6h-1.9v.4M147.7 32.4v7.5"/>
<path d="M152.6 32.4l.2 .2M152.6 39.9h2M152.6 32.4v7.5M152.6 32.4h2M152.8 32.6h.8l.3-.2 .2 .2M152.8 39.6l-.2 .3M152.8 39.6h.8M152.8 32.6v7M153.6 32.6l.1 .2h.4v-.2M153.6 39.6v-.1h.5v.1M153.6 39.6l.3 .3 .2-.3M154.1 39.6h.8"/>
<path d="M154.1 32.6h.8M154.6 32.4v-.3h1.6v.3l-.2 .2M154.6 32.4l.3 .2M154.6 32.1l.3 .2M154.9 40h1.1M154.9 39.6l-.3 .3M154.9 39.6v.4M154.9 40l-.3 .2M154.9 32.3h1.1M154.9 32.3v.3M156 39.6l.2 .3v.3h-1.6v-.3M156 40l.2 .2"/>
<path d="M156 32.3v.3h2M156.2 32.1l-.2 .2M156.2 32.4h2l-.2 .2M158 39.6h-2v.4M158 39.6l.2 .3h-2M158 32.6v7M158.2 32.4v7.5M163.1 32.4v7.5M163.1 32.4l.3 .2M163.1 32.4h2.1M163.1 39.9h2.1M163.4 32.6v7"/>
<path d="M163.4 39.6l-.3 .3M163.4 39.6h.7M164.1 32.6l.1 .2h.4l.1-.2M164.1 39.6l.1-.1h.4l.1 .1M164.1 39.6l.3 .3M164.4 32.4l-.3 .2h-.7M164.4 32.4l.3 .2M164.7 39.6l-.3 .3M164.7 32.6h.7M164.7 39.6h.7M165.2 32.4v-.3h1.5v.3l-.2 .2M165.2 32.4l.2 .2"/>
<path d="M165.2 32.1l.2 .2M165.4 32.3h1.1M165.4 40h1.1M165.4 39.6l-.2 .3M165.4 32.3v.3M165.4 39.6v.4M165.4 40l-.2 .2M166.5 39.6l.2 .3v.3h-1.5v-.3M166.5 40l.2 .2M166.5 32.3v.3h2M166.7 32.1l-.2 .2M166.7 32.4h2l-.2 .2"/>
<path d="M168.5 32.6v7M168.5 39.6h-2v.4M168.5 39.6l.2 .3h-2M168.7 32.4v7.5M173.7 32.4v7.5M173.7 32.4l.2 .2M173.7 32.4h2M173.7 39.9h2M173.9 32.6h.8l.2-.2 .3 .2M173.9 32.6v7M173.9 39.6l-.2 .3M173.9 39.6h.8"/>
<path d="M174.7 32.6l.1 .2h.4v-.2M174.7 39.6v-.1h.4l.1 .1M174.7 39.6l.2 .3 .3-.3M175.2 32.6h.7M175.2 39.6h.7M175.7 32.4v-.3h1.6v.3l-.2 .2M175.7 32.4l.2 .2M175.7 32.1l.2 .2M175.9 32.3h1.2M175.9 40h1.2M175.9 39.6l-.2 .3M175.9 32.3v.3"/>
<path d="M175.9 39.6v.4M175.9 40l-.2 .2M177.1 39.6l.2 .3v.3h-1.6v-.3M177.1 40l.2 .2M177.1 32.3v.3h1.9M177.3 32.1l-.2 .2M177.3 32.4h2l-.3 .2M179 32.6v7M179 39.6h-1.9v.4M179 39.6l.3 .3h-2M179.3 32.4v7.5M184.2 32.4l.2 .2"/>
<path d="M184.2 39.9h2M184.2 32.4v7.5M184.2 32.4h2M184.4 39.6l-.2 .3M184.4 39.6h.8M184.4 32.6v7M185.2 39.6l.1-.1h.4v.1M185.2 32.6l.1 .2h.4v-.2M185.2 39.6l.3 .3M185.5 32.4l-.3 .2h-.8M185.5 32.4l.2 .2M185.7 39.6l-.2 .3"/>
<path d="M185.7 39.6h.7M185.7 32.6h.7M186.2 32.4v-.3h1.6v.3l-.2 .2M186.2 32.4l.2 .2M186.2 32.1l.2 .2M186.4 40h1.2M186.4 39.6l-.2 .3M186.4 39.6v.4M186.4 40l-.2 .2M186.4 32.3h1.2M186.4 32.3v.3M187.6 40l.2 .2"/>
<path d="M187.6 39.6l.2 .3v.3h-1.6v-.3M187.6 32.3v.3h2M187.8 32.1l-.2 .2M187.8 32.4h2l-.2 .2M189.6 39.6l.2 .3h-2M189.6 39.6h-2v.4M189.6 32.6v7M189.8 32.4v7.5M194.7 32.4v7.5M194.7 32.4l.3 .2M194.7 32.4h2.1M194.7 39.9h2.1"/>
<path d="M195 39.6h.7M195 33.9h5.1M195 38.3h5.1M195 32.6v7M195 39.6l-.3 .3M195.7 32.6l.1 .2h.4l.1-.2M195.7 39.6l.1-.1h.4l.1 .1M195.7 39.6l.3 .3M195.8 33.9v4.4M196 32.4l-.3 .2h-.7M196 32.4l.3 .2M196.3 39.6l-.3 .3"/>
<path d="M196.3 32.6h.7M196.3 39.6h.7M196.8 32.4v-.3h1.5v.3l-.2 .2M196.8 32.4l.2 .2M196.8 32.1l.2 .2M197 32.3h1.1M197 40h1.1M197 39.6l-.2 .3M197 32.3v.3M197 39.6v.4M197 40l-.2 .2M198.1 39.6l.2 .3v.3h-1.5v-.3"/>
<path d="M198.1 40l.2 .2M198.1 32.3v.3h2M198.3 32.1l-.2 .2M198.3 32.4h2l-.2 .2M199.2 33.9v4.4M200.1 32.6v7M200.1 39.6h-2v.4M200.1 39.6l.2 .3h-2M200.3 32.4v7.5M205.3 39.9h2M205.3 32.4v7.5M205.3 32.4l.2 .2"/>
<path d="M205.3 32.4h2M205.5 39.6h.8M205.5 33.9h5.2M205.5 38.3h5.2M205.5 32.6v7M205.5 39.6l-.2 .3M206.3 39.6v-.1h.4l.1 .1M206.3 32.6l.1 .2h.4v-.2M206.3 39.6l.2 .3M206.4 33.9v4.4M206.5 32.4l-.2 .2h-.8M206.5 32.4l.3 .2"/>
<path d="M206.8 39.6l-.3 .3M206.8 39.6h.7M206.8 32.6h.7M207.3 32.4l.2 .2M207.3 32.1l.2 .2M207.3 32.4v-.3h1.6v.3l-.2 .2M207.5 40h1.2M207.5 39.6l-.2 .3M207.5 39.6v.4M207.5 40l-.2 .2M207.5 32.3h1.2M207.5 32.3v.3"/>
<path d="M208.7 32.3v.3h2M208.7 39.6l.2 .3v.3h-1.6v-.3M208.7 40l.2 .2M208.9 32.4h2l-.2 .2M208.9 32.1l-.2 .2M209.8 33.9v4.4M210.7 39.6l.2 .3h-2M210.7 32.6v7M210.7 39.6h-2v.4M210.9 32.4v7.5M215.8 32.4h2M215.8 32.4v7.5"/>
<path d="M215.8 32.4l.2 .2M215.8 39.9h2M216 33.9h5.2M216 38.3h5.2M216 39.6l-.2 .3M216 32.6v7M216 39.6h.8M216.8 39.6l.1-.1h.4v.1M216.8 32.6l.1 .2h.4v-.2M216.8 39.6l.3 .3M216.9 33.9v4.4M217.1 32.4l-.3 .2h-.8"/>
<path d="M217.1 32.4l.2 .2M217.3 32.6h.7M217.3 39.6l-.2 .3M217.3 39.6h.7M217.8 32.4l.2 .2M217.8 32.1l.2 .2M217.8 32.4v-.3h1.6v.3l-.2 .2M218 32.3h1.2M218 32.3v.3M218 39.6l-.2 .3M218 40l-.2 .2M218 40h1.2"/>
<path d="M218 39.6v.4M219.2 32.3v.3h2M219.2 40l.2 .2M219.2 39.6l.2 .3v.3h-1.6v-.3M219.4 32.4h2l-.2 .2M219.4 32.1l-.2 .2M220.3 33.9v4.4M221.2 39.6h-2v.4M221.2 32.6v7M221.2 39.6l.2 .3h-2M221.4 32.4v7.5M226.3 32.4v7.5"/>
<path d="M226.3 32.4l.3 .2M226.3 39.9h2.1M226.3 32.4h2.1M226.6 32.6v7M226.6 39.6l-.3 .3M226.6 33.9h5.1M226.6 38.3h5.1M226.6 39.6h.7M227.3 32.6l.1 .2h.4l.1-.2M227.3 39.6l.1-.1h.4l.1 .1M227.3 39.6l.3 .3M227.4 33.9v4.4"/>
<path d="M227.6 32.4l-.3 .2h-.7M227.6 32.4l.3 .2M227.9 39.6h.7M227.9 39.6l-.3 .3M227.9 32.6h.7M228.4 32.4l.2 .2M228.4 32.1l.2 .2M228.4 32.4v-.3h1.5v.3l-.2 .2M228.6 40h1.1M228.6 39.6l-.2 .3M228.6 39.6v.4M228.6 40l-.2 .2"/>
<path d="M228.6 32.3h1.1M228.6 32.3v.3M229.7 32.3v.3h2M229.7 39.6l.2 .3v.3h-1.5v-.3M229.7 40l.2 .2M229.9 32.4h2l-.2 .2M229.9 32.1l-.2 .2M230.8 33.9v4.4M231.7 39.6l.2 .3h-2M231.7 32.6v7M231.7 39.6h-2v.4M231.9 32.4v7.5"/>
<path d="M261.4 182.5a4.4 4.4 0 0 1 7.1 .6l-1.3 .8a2.88 2.88 0 0 0-4.5-.7 2.88 2.88 0 0 0 .5 4.6 2.88 2.88 0 0 0 4.3-1.8h-1.9a1.17 1.17 0 0 1-2-.3 1.12 1.12 0 0 1 1.1-1.5l.6 .1 .3 .2h3.4a4.4 4.4 0 0 1-5.5 5 4.4 4.4 0 0 1-2.1-7zM261.8 185.2l-1.3 1.3M261.8 185.4l-1.3 1.3M261.8 185.6l-1.2 1.2M261.8 184.9l-1.4 1.4M261.9 185.8l-1.3 1.2M261.9 184.6l-1.5 1.5M261.9 186l-1.2 1.1M261.9 186.1l-1.1 1.2M262 181.8l-.7 .8M262 184.3l-1.6 1.6M262 186.3l-1.1 1.1"/>
<path d="M262 186.5l-1 1.1M262.1 186.6l-1.1 1.1M262.1 183.9l-1.8 1.8M262.2 186.8l-1.1 1M262.3 186.9l-1.1 1.1M262.4 187l-1.1 1.1M262.5 187.1l-1.1 1.1M262.6 187.3l-1.1 1M262.6 181.4l-1.8 1.8M262.7 187.4l-1.1 1M262.8 187.5l-1 1M262.9 187.6l-1 1"/>
<path d="M263 181.2l-2.4 2.4M263.1 187.7l-1.1 1M263.2 187.8l-1.1 1M263.4 187.8l-1.1 1.1M263.4 181.1l-2.9 2.9M263.5 187.9l-1.1 1.1M263.7 188l-1.2 1.1M263.7 181l-3.3 3.3M263.8 188l-1.1 1.2M264 181l-3.6 3.6M264 188.1l-1.2 1.1M264.2 188.1l-1.2 1.2"/>
<path d="M264.2 180.9l-3.8 3.9M264.3 184.2l-.7 .7M264.4 188.2l-1.3 1.2M264.5 180.9l-4.2 4.2M264.6 188.2l-1.3 1.2M264.6 184.2l-1.1 1M264.7 180.9l-4.4 4.4M264.8 188.2l-1.3 1.3M264.8 184.2l-1.3 1.2M264.9 180.9l-4.6 4.6M265 184.2l-1.4 1.4M265 188.2l-1.3 1.3"/>
<path d="M265.1 180.9l-1.8 1.9M265.2 184.2l-1.5 1.6M265.3 184.3l-1.6 1.6M265.3 181l-1.6 1.6M265.3 188.1l-1.5 1.5M265.4 184.4l-1.6 1.6M265.5 181l-1.5 1.5M265.5 184.5l-1.6 1.6M265.6 188l-1.6 1.6M265.7 181l-1.4 1.4M265.7 184.5l-1.6 1.7M265.9 181.1l-1.4 1.3"/>
<path d="M266 184.5l-1.8 1.8M266 187.8l-1.8 1.8M266 181.1l-1.2 1.3M266.2 184.5l-1.8 1.9M266.2 181.2l-1.2 1.2M266.4 181.3l-1.2 1.1M266.4 184.5l-1.9 1.9M266.5 181.3l-1.1 1.2M266.6 184.5a2.01 2.01 0 0 0-3.1-.8 2.01 2.01 0 0 0 0 3.2 2.01 2.01 0 0 0 3.1-.9M266.6 184.5l-1.8 1.9M266.7 181.4l-1.2 1.1M266.8 181.5l-1.1 1.1"/>
<path d="M266.9 184.5l-1.9 1.9M267 181.6l-1.1 1.1M267.1 184.5l-1.5 1.5M267.1 181.6l-1.1 1.1M267.2 181.7l-1.1 1.1M267.3 184.5l-1.5 1.5M267.4 181.8l-1.1 1.1M267.5 181.9l-1.1 1.1M267.5 184.5l-1.5 1.5M267.6 182l-1 1.1M267.7 182.1l-1 1.1M267.8 184.5l-1.5 1.5"/>
<path d="M267.8 182.3l-1 1M267.9 182.4l-1 1M268 184.5l-1.5 1.5M268 182.5l-1 1M268.1 182.6l-1 1.1M268.2 187.9l-.9 .9M268.2 184.5l-1.5 1.5M268.2 182.7l-1 1.1M268.3 182.9l-.8 .7M268.4 184.5l-1.5 1.5M268.4 183l-.3 .4M268.6 187.3l-1.9 1.9"/>
<path d="M268.6 184.5l-1.4 1.5M268.8 186.9l-2.5 2.4M268.9 186.5l-2.9 3M268.9 184.5l-1.5 1.5M268.9 186.3l-3.3 3.3M269 184.6l-1.6 1.6M269 186l-3.6 3.6M269 184.8l-1.7 1.8M269 185.7l-3.9 3.9M269 185.3l-4.4 4.4M269 185l-4.6 4.7M269 185.5l-4.1 4.2"/>
<path d="M270.7 182.4a4.4 4.4 0 0 1 6.3-.2l-1.1 1a2.88 2.88 0 0 0-4 0 2.88 2.88 0 0 0 0 4.1 2.88 2.88 0 0 0 4 0l1.1 1.1a4.4 4.4 0 0 1-6.1 0 4.4 4.4 0 0 1-.2-6zM271 185.3l-1.3 1.3M271 185.5l-1.2 1.2M271 185l-1.3 1.4M271.1 185.7l-1.2 1.2M271.1 184.8l-1.5 1.4M271.1 185.9l-1.2 1.2M271.1 184.5l-1.5 1.5M271.1 186.1l-1.1 1.1M271.2 186.2l-1.1 1.2M271.3 186.4l-1.1 1.1M271.3 184.2l-1.7 1.6"/>
<path d="M271.3 186.5l-1.1 1.1M271.4 186.7l-1.1 1.1M271.5 186.8l-1.1 1.1M271.5 183.7l-1.9 1.9M271.6 187l-1.1 1M271.6 181.6l-1.4 1.4M271.7 187.1l-1.1 1M271.8 187.2l-1.1 1.1M271.9 187.3l-1.1 1.1M272 187.4l-1 1.1M272.1 181.3l-2.2 2.2M272.1 187.5l-1 1.1"/>
<path d="M272.2 187.6l-1 1.1M272.4 187.7l-1.1 1.1M272.5 181.2l-2.7 2.6M272.5 187.8l-1.1 1.1M272.7 187.9l-1.1 1.1M272.8 181.1l-3.1 3.1M272.8 187.9l-1.1 1.1M273 188l-1.1 1.1M273.1 181l-3.5 3.5M273.2 188.1l-1.2 1.1M273.3 188.1l-1.1 1.2M273.3 181l-3.7 3.7"/>
<path d="M273.5 188.1l-1.2 1.2M273.6 180.9l-4 4.1M273.7 188.2l-1.2 1.2M273.8 180.9l-4.2 4.3M273.9 188.2l-1.3 1.2M274 180.9l-4.4 4.5M274.2 188.2l-1.4 1.3M274.3 180.9l-2 2M274.4 188.1l-1.4 1.5M274.5 181l-1.7 1.6M274.7 181l-1.6 1.5M274.7 188.1l-1.5 1.5"/>
<path d="M274.8 181l-1.4 1.4M275 181.1l-1.3 1.3M275.1 187.9l-1.7 1.7M275.2 181.1l-1.3 1.3M275.4 181.2l-1.3 1.2M275.5 181.2l-1.2 1.2M275.6 187.6l-2 2M275.7 181.3l-1.2 1.2M275.8 181.4l-1.1 1.1M276 181.4l-1.1 1.2M276 187.4l-2.2 2.2M276.1 181.5l-1.1 1.1"/>
<path d="M276.1 187.5l-2.1 2.1M276.2 187.6l-1.9 2M276.3 181.6l-1.1 1.1M276.4 187.7l-1.9 1.9M276.4 181.7l-1.1 1.1M276.5 187.9l-1.7 1.7M276.5 181.8l-1 1M276.6 188l-1.5 1.5M276.6 181.9l-1 1.1M276.7 188.1l-1.3 1.3M276.8 182l-1.1 1M276.8 188.2l-1 1"/>
<path d="M276.9 182.1l-1.1 1M276.9 188.3l-.6 .6M277.5 181h7.2v1.5h-2.9v7h-1.5v-7h-2.8zM277.5 181h.1M277.7 181l-.2 .3M278 181l-.5 .5M278.2 181l-.7 .7M278.4 181l-.9 .9M278.6 181l-1.1 1.1M278.9 181l-1.4 1.4M279.1 181l-1.5 1.5M279.3 181l-1.5 1.5"/>
<path d="M279.5 181l-1.5 1.5M279.8 181l-1.5 1.5M280 181l-1.5 1.5M280.2 181l-1.5 1.5M280.4 181l-1.5 1.5M280.6 181l-1.4 1.5M280.9 181l-1.5 1.5M281.1 181l-1.5 1.5M281.3 181l-1.5 1.5M281.5 181l-1.4 1.5M281.8 181l-1.5 1.5M281.8 189.4l-.1 .1"/>
<path d="M281.8 189.2l-.3 .3M281.8 189l-.5 .5M281.8 188.5l-1 1M281.8 188.8l-.7 .7M281.8 188.1l-1.4 1.4M281.8 188.3l-1.2 1.2M281.8 182.7l-1.5 1.5M281.8 183l-1.5 1.4M281.8 183.2l-1.5 1.5M281.8 183.4l-1.5 1.5M281.8 183.6l-1.5 1.5M281.8 183.8l-1.5 1.5"/>
<path d="M281.8 184.1l-1.5 1.5M281.8 184.3l-1.5 1.5M281.8 184.5l-1.5 1.5M281.8 184.7l-1.5 1.5M281.8 185l-1.5 1.4M281.8 185.2l-1.5 1.5M281.8 185.4l-1.5 1.5M281.8 185.6l-1.5 1.5M281.8 185.9l-1.5 1.4M281.8 186.1l-1.5 1.5M281.8 186.3l-1.5 1.5M281.8 186.5l-1.5 1.5"/>
<path d="M281.8 186.7l-1.5 1.5M281.8 187l-1.5 1.5M281.8 187.2l-1.5 1.5M281.8 187.4l-1.5 1.5M281.8 187.6l-1.5 1.5M281.8 187.9l-1.5 1.4M282 181l-1.7 1.7M282.2 181l-1.9 1.9M282.4 181l-2.1 2.1M282.7 181l-2.4 2.3M282.9 181l-2.6 2.5M283.1 181l-2.8 2.8"/>
<path d="M283.3 181l-3 3M283.5 181l-1.4 1.5M283.8 181l-1.5 1.5M284 181l-1.5 1.5M284.2 181l-1.5 1.5M284.4 181l-1.4 1.5M284.6 181l-1.4 1.5M284.7 181.7l-.9 .8M284.7 181.4l-1.1 1.1M284.7 182.3l-.2 .2M284.7 181.2l-1.3 1.3M284.7 182.1l-.4 .4"/>
<path d="M284.7 181.9l-.6 .6"/>
<circle cx="76.4" cy="29.5" r=".66"/>
<circle cx="79.9" cy="29.5" r=".66"/>
<circle cx="83.4" cy="29.5" r=".66"/>
<circle cx="87" cy="29.5" r=".66"/>
<circle cx="90.5" cy="29.6" r=".66"/>
<circle cx="94" cy="29.6" r=".66"/>
<circle cx="97.5" cy="29.6" r=".66"/>
<circle cx="101" cy="29.6" r=".66"/>
<circle cx="104.5" cy="29.6" r=".66"/>
<circle cx="108" cy="29.6" r=".66"/>
<circle cx="111.5" cy="29.5" r=".66"/>
<circle cx="115" cy="29.5" r=".66"/>
<circle cx="118.6" cy="29.6" r=".66"/>
<circle cx="122.1" cy="29.6" r=".66"/>
<circle cx="125.6" cy="29.6" r=".66"/>
<circle cx="129.1" cy="29.6" r=".66"/>
<circle cx="132.6" cy="29.6" r=".66"/>
<circle cx="136.1" cy="29.5" r=".66"/>
<circle cx="139.6" cy="29.5" r=".66"/>
<circle cx="143.1" cy="29.5" r=".66"/>
<circle cx="146.6" cy="29.5" r=".66"/>
<circle cx="150.2" cy="29.6" r=".66"/>
<circle cx="153.7" cy="29.6" r=".66"/>
<circle cx="157.2" cy="29.6" r=".66"/>
<circle cx="160.7" cy="29.6" r=".66"/>
<circle cx="164.2" cy="29.5" r=".66"/>
<circle cx="167.7" cy="29.6" r=".66"/>
<circle cx="171.2" cy="29.5" r=".66"/>
<circle cx="174.7" cy="29.5" r=".66"/>
<circle cx="178.2" cy="29.6" r=".66"/>
<circle cx="181.8" cy="29.6" r=".66"/>
<circle cx="185.3" cy="29.6" r=".66"/>
<circle cx="188.8" cy="29.6" r=".66"/>
<circle cx="192.3" cy="29.6" r=".66"/>
<circle cx="195.8" cy="29.5" r=".66"/>
<circle cx="199.3" cy="29.5" r=".66"/>
<circle cx="202.8" cy="29.5" r=".66"/>
<circle cx="206.3" cy="29.5" r=".66"/>
<circle cx="209.8" cy="29.6" r=".66"/>
<circle cx="213.4" cy="29.6" r=".66"/>
<circle cx="216.9" cy="29.6" r=".66"/>
<circle cx="220.4" cy="29.6" r=".66"/>
<circle cx="223.9" cy="29.5" r=".66"/>
<circle cx="227.4" cy="29.5" r=".66"/>
<circle cx="230.9" cy="29.5" r=".66"/>
</g>
<g fill="none" stroke="#000" stroke-width=".17">
<path d="M10 4.7h-4.8v4.8M10 9.5h277v191.1h-277zM44.3 7.1v2.4M78.5 7.1v2.4M112.8 7.1v2.4M147.1 7.1v2.4M181.4 7.1v2.4M215.7 7.1v2.4M250 7.1v2.4M287 4.7h4.8v4.8M7.6 33.3h2.4M234.4 28.9a.66 .66 0 0 0-.6 .7 .66 .66 0 0 0 .6 .6"/>
<path d="M287 33.3h2.4M7.6 57.2h2.4M287 57.2h2.4M7.6 81.1h2.4M287 81.1h2.4M7.6 105h4.8M284.6 105h4.8M7.6 128.9h2.4M287 128.9h2.4M7.6 152.8h2.4M287 152.8h2.4M7.6 176.7h2.4"/>
<path d="M194.8 178.6v10.3M257.9 178.6v22M287 176.7h2.4M287 178.6h-124.1v22M162.9 181h95M162.9 188.9h95M162.9 191.5h20.6M162.9 196.1h20.6M162.9 186.2h31.9M162.9 183.8h31.9M162.9 198.3h20.6M171.5 188.9v11.7"/>
<path d="M183.5 188.9v11.7M183.5 192.7h21.5M194.1 192.7v7.9M205 188.9v11.7M205 194.7h11.4M207.1 196.9h.9M208.2 196.9h.2M208.3 195.7v.8M208.3 196.7v.3M208.3 197.2v.8M208.7 196.9h.8M209.8 196.9h4.9"/>
<path d="M210.4 196.3l3.3-.4v1.9l-3.3-.4zM216.4 188.9v11.7M218.1 197.1v.2a1.26 1.26 0 0 0 1.3 .3h6.6M225 198.4l.4-.2 .2 .2 .2-.3a1.43 1.43 0 0 1 1.1-1l.1 .1-1.2 1.7a.4 .4 0 0 1-.5 .3 .4 .4 0 0 1-.3-.5zM226.8 197.1v-6a.62 .62 0 0 0-.8-.7h-7a.73 .73 0 0 0-1 .5v7.4a1.27 1.27 0 0 0 .3 1.2l.5 .2h6.3a1.98 1.98 0 0 0 1.6-.3l.1-1.9M228.5 188.9v11.7M257.9 195.3h29.1M266.3 195.3v5.3M276.5 195.3v5.3M5.2 200.6v4.7h4.8M44.3 200.6v2.4M78.5 200.6v2.4"/>
<path d="M112.8 200.6v2.4M147.1 200.6v2.4M181.4 200.6v2.4M215.7 200.6v2.4M250 200.6v2.4M291.8 200.6v4.7h-4.8"/>
<circle cx="208.3" cy="196.9" r=".96"/>
<circle cx="208.3" cy="196.9" r=".59"/>
<circle cx="231.8" cy="194.6" r="2.2"/>
</g>
<g fill="#000" stroke="#000" stroke-width=".17">
<path d="M218.9 196.2l.3-.1-.1 .2h-.2z" fill-rule="evenodd"/>
<path d="M218.7 198.1h.4l.2 .2h-.5v.7h.5l-.1 .2h-.5z" fill-rule="evenodd"/>
<path d="M218.9 194.5l.4-.1 .2 .1h-.3l-.2 .2v.5l.5 .1-.2 .2-.3-.1-.2-.2v-.4z" fill-rule="evenodd"/>
<path d="M219 196.1h.5v.3l-.4 .5h.4v.1h-.6l.4-.7v-.1l-.4-.1z" fill-rule="evenodd"/>
<path d="M218.9 198.3h.5l-.1 .7h-.5h.4v-.3v-.3z" fill-rule="evenodd"/>
<path d="M219.4 195.1h.2l-.1 .2h-.3z" fill-rule="evenodd"/>
<path d="M219.2 194.5h.3l.1 .2h-.2z" fill-rule="evenodd"/>
<path d="M219.5 198.6h.3l-.1 .1h.4v.1h-.4l.1 .2 .2 .1a.29 .29 0 0 1-.5-.1z" fill-rule="evenodd"/>
<path d="M218.9 191.3h1.1l.3 .1 .2 .2-1.2 .1v.6l1.1 .1-.4 .3h-.7v1.1h-.4z" fill-rule="evenodd"/>
<path d="M219.8 194.5h.3l-.2 .2v.4l.1 .2h.4l-.1 .1-.3 .1-.2-.2-.1-.3z" fill-rule="evenodd"/>
<path d="M219.6 198.5l.3-.1 .2 .3h-.4h.2l-.1-.1h-.3z" fill-rule="evenodd"/>
<path d="M219.8 199h.3z" fill-rule="evenodd"/>
<path d="M219.8 196.1l.3-.1 .1 .1-.3 .1-.1 .1 .1 .5 .3 .1a.32 .32 0 0 1-.4 .1 .32 .32 0 0 1-.2-.3z" fill-rule="evenodd"/>
<path d="M219.4 192.7h.6l.2 .2 .5 .9h-.5a1.45 1.45 0 0 0-.8-1.1z" fill-rule="evenodd"/>
<path d="M219.8 194.5a.42 .42 0 0 1 .4-.1 .42 .42 0 0 1 .3 .4v.5h-.4a.41 .41 0 0 0 .2-.4 .41 .41 0 0 0-.2-.4z" fill-rule="evenodd"/>
<path d="M220 196.1l.2 .1v.7h-.2l.1-.3z" fill-rule="evenodd"/>
<path d="M220.2 198.6h.3l-.1 .1v.2l.1 .1h.2l-.1 .2-.3-.1z" fill-rule="evenodd"/>
<path d="M219.6 191.7l.9-.1v.3l-.1 .5-1.1-.1h.4a.34 .34 0 0 0 .4-.2 .34 .34 0 0 0-.2-.4z" fill-rule="evenodd"/>
<path d="M220.5 196.2l.2 .1-.2 .1z" fill-rule="evenodd"/>
<path d="M220.3 198.5l.3-.1 .2 .2z" fill-rule="evenodd"/>
<path d="M220.6 198.9l.2 .1h-.3z" fill-rule="evenodd"/>
<path d="M220.5 196.2l.4-.2v1h-.2v-.7z" fill-rule="evenodd"/>
<path d="M220.9 199.1h.4l-.3 .1z" fill-rule="evenodd"/>
<path d="M220.7 194.4h.2l-.1 .2v.9h-.1z" fill-rule="evenodd"/>
<path d="M220.9 194.4l.2 .7-.1 .4-.2-.9z" fill-rule="evenodd"/>
<path d="M220.9 198.8h.4l-.2 .1-.1 .1 .4 .1v.1l-.5-.1z" fill-rule="evenodd"/>
<path d="M221 198.4h.3l.1 .2-.4 .1-.1-.1z" fill-rule="evenodd"/>
<path d="M221.2 196.2l.3 .1-.3 .1z" fill-rule="evenodd"/>
<path d="M221.1 198.6h.3v.5h-.3l.2-.3h-.4l.4-.1z" fill-rule="evenodd"/>
<path d="M221.2 194.4h.3l-.4 1.1h-.1z" fill-rule="evenodd"/>
<path d="M221.5 194.4v1.1h-.2v-.9z" fill-rule="evenodd"/>
<path d="M221.2 192l.6-.1 .3 .4h-.6a.62 .62 0 0 0-.4 .6 .62 .62 0 0 0 .4 .5h-.6a1.27 1.27 0 0 1 .3-1.4z" fill-rule="evenodd"/>
<path d="M221.6 198.7h.3v.2h-.3z" fill-rule="evenodd"/>
<path d="M221.2 196.2l.4-.2v1h-.1v-.7z" fill-rule="evenodd"/>
<path d="M222.1 196h.1l-.2 1.1h-.1z" fill-rule="evenodd"/>
<path d="M221.7 194.4h.5l.1 .1-.5 .1v.3h.5l-.1 .1-.4 .1v.4h-.1z" fill-rule="evenodd"/>
<path d="M221.5 192.3h.6a.95 .95 0 0 1-.7 1.5l-.5-.4h.6l.3-.1 .1-.7z" fill-rule="evenodd"/>
<path d="M221.9 194.6l.4-.1v.4h-.5l.3-.1v-.2z" fill-rule="evenodd"/>
<path d="M222 198.1h.5l.2 .2h-.5v.3h.4h-.1l.2 .1h-.5v.3h.5l-.1 .1-.6 .1z" fill-rule="evenodd"/>
<path d="M222.4 196.1l.4-.1 .1 .1-.4 .1v.2l.4 .1h-.4v.3l.2 .1h-.3l-.1-.1z" fill-rule="evenodd"/>
<path d="M222.3 198.3h.4l-.1 .3h-.4l.3-.2z" fill-rule="evenodd"/>
<path d="M222.5 194.4h.2v.9h.4v.2h-.6z" fill-rule="evenodd"/>
<path d="M222.5 196.4l.4 .1z" fill-rule="evenodd"/>
<path d="M222.3 198.7h.4v.3h-.5l.3-.1v-.2z" fill-rule="evenodd"/>
<path d="M222.7 196.5l.2 .1v.3l-.2 .2-.3-.2 .4-.1z" fill-rule="evenodd"/>
<path d="M222.7 196.1h.2v.1l-.1 .1z" fill-rule="evenodd"/>
<path d="M222.6 191.3h.4v1l.8 .4h-.8v1.1h-.4z" fill-rule="evenodd"/>
<path d="M222.9 198.1h.4l.2 .2h-.5v.7h.5l-.1 .2h-.5z" fill-rule="evenodd"/>
<path d="M223.2 194.4h.2v1.1h-.2z" fill-rule="evenodd"/>
<path d="M223.1 196.8l.5 .1a.31 .31 0 0 1-.3 .2 .31 .31 0 0 1-.2-.3z" fill-rule="evenodd"/>
<path d="M223.3 196.4h.3z" fill-rule="evenodd"/>
<path d="M223.1 198.3h.4l.1 .3-.1 .4h-.5h.3l.1-.2v-.4z" fill-rule="evenodd"/>
<path d="M223.4 196.5h.3v.1v.3h-.3a.21 .21 0 0 0 .1-.2 .21 .21 0 0 0-.1-.2z" fill-rule="evenodd"/>
<path d="M223.2 196h.5v.2h-.4v.2l.4 .1h-.6z" fill-rule="evenodd"/>
<path d="M224 196h.2l-.3 1.1h-.1z" fill-rule="evenodd"/>
<path d="M223.8 194.4h.2l-.2 .6 .3 .2h-.4v.3h-.2z" fill-rule="evenodd"/>
<path d="M224 194.4l.3 1.1h-.1l-.1-.3-.3-.2h.2l-.1-.4z" fill-rule="evenodd"/>
<path d="M223.8 191.3h.3v2.5h-.3v-1.1l-.8-.4h.8z" fill-rule="evenodd"/>
<path d="M223.8 198.1h.6v.2h-.5v.2h.5v.2h-.5v.3h.5v.2h-.6z" fill-rule="evenodd"/>
<path d="M224.5 194.4h.1v1.1h-.1z" fill-rule="evenodd"/>
<path d="M224.6 194.4l.4 .7v.4l-.4-.7z" fill-rule="evenodd"/>
<path d="M224.5 193l.3-.1 .1 .3 .4 .2h-.7z" fill-rule="evenodd"/>
<path d="M224.2 196h.8v.2h-.5v.2h.4v.2h-.4v.3h.5v.1h-.8z" fill-rule="evenodd"/>
<path d="M225 194.4h.1v1.1h-.1z" fill-rule="evenodd"/>
<path d="M224.7 191.4a.78 .78 0 0 1 1.2 .2l-.9 .1v.4l.3 .1a.83 .83 0 0 1 .6 1.3l-.2 .2a.86 .86 0 0 1-1.1-.3h.7a.37 .37 0 0 0 .3-.4 .37 .37 0 0 0-.5-.3 .75 .75 0 0 1-.6-.9z" fill-rule="evenodd"/>
<path d="M225.1 196h.3v.7l.2 .2-.4-.1z" fill-rule="evenodd"/>
<path d="M225.2 191.7l.7-.1 .1 .4h-.4l-.2-.3z" fill-rule="evenodd"/>
<path d="M225.7 196h.2v.9l-.2 .1h-.3l-.2-.1 .5-.1z" fill-rule="evenodd"/>
<path d="M225.3 194.4h.7v.2h-.3v.9h-.2v-.9h-.2z" fill-rule="evenodd"/>
</g>
<use href="#words"/>
</svg>
